VERSION 5.7 ;
  NOWIREEXTENSIONATPIN ON ;
  DIVIDERCHAR "/" ;
  BUSBITCHARS "[]" ;
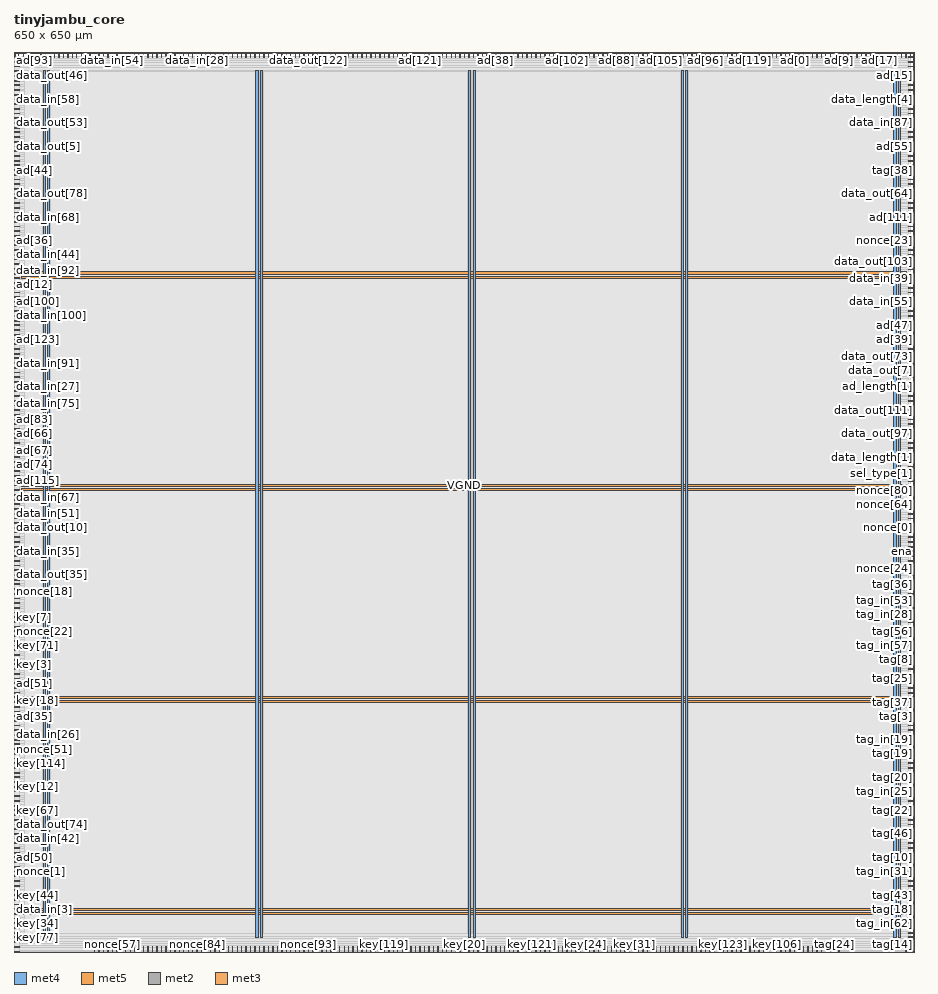
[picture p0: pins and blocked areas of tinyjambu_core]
MACRO tinyjambu_core
  CLASS BLOCK ;
  FOREIGN tinyjambu_core ;
  ORIGIN 0.000 0.000 ;
  SIZE 650.000 BY 650.000 ;
  PIN VGND
    DIRECTION INOUT ;
    USE GROUND ;
    PORT
      LAYER met4 ;
        RECT 24.340 10.640 25.940 636.720 ;
    END
    PORT
      LAYER met4 ;
        RECT 177.940 10.640 179.540 636.720 ;
    END
    PORT
      LAYER met4 ;
        RECT 331.540 10.640 333.140 636.720 ;
    END
    PORT
      LAYER met4 ;
        RECT 485.140 10.640 486.740 636.720 ;
    END
    PORT
      LAYER met4 ;
        RECT 638.740 10.640 640.340 636.720 ;
    END
    PORT
      LAYER met5 ;
        RECT 5.280 30.030 644.700 31.630 ;
    END
    PORT
      LAYER met5 ;
        RECT 5.280 183.210 644.700 184.810 ;
    END
    PORT
      LAYER met5 ;
        RECT 5.280 336.390 644.700 337.990 ;
    END
    PORT
      LAYER met5 ;
        RECT 5.280 489.570 644.700 491.170 ;
    END
  END VGND
  PIN VPWR
    DIRECTION INOUT ;
    USE POWER ;
    PORT
      LAYER met4 ;
        RECT 21.040 10.640 22.640 636.720 ;
    END
    PORT
      LAYER met4 ;
        RECT 174.640 10.640 176.240 636.720 ;
    END
    PORT
      LAYER met4 ;
        RECT 328.240 10.640 329.840 636.720 ;
    END
    PORT
      LAYER met4 ;
        RECT 481.840 10.640 483.440 636.720 ;
    END
    PORT
      LAYER met4 ;
        RECT 635.440 10.640 637.040 636.720 ;
    END
    PORT
      LAYER met5 ;
        RECT 5.280 26.730 644.700 28.330 ;
    END
    PORT
      LAYER met5 ;
        RECT 5.280 179.910 644.700 181.510 ;
    END
    PORT
      LAYER met5 ;
        RECT 5.280 333.090 644.700 334.690 ;
    END
    PORT
      LAYER met5 ;
        RECT 5.280 486.270 644.700 487.870 ;
    END
  END VPWR
  PIN ad[0]
    DIRECTION INPUT ;
    USE SIGNAL ;
    ANTENNAGATEAREA 0.196500 ;
    PORT
      LAYER met2 ;
        RECT 563.590 646.000 563.870 650.000 ;
    END
  END ad[0]
  PIN ad[100]
    DIRECTION INPUT ;
    USE SIGNAL ;
    ANTENNAGATEAREA 0.196500 ;
    PORT
      LAYER met3 ;
        RECT 0.000 469.240 4.000 469.840 ;
    END
  END ad[100]
  PIN ad[101]
    DIRECTION INPUT ;
    USE SIGNAL ;
    ANTENNAGATEAREA 0.196500 ;
    PORT
      LAYER met2 ;
        RECT 45.170 646.000 45.450 650.000 ;
    END
  END ad[101]
  PIN ad[102]
    DIRECTION INPUT ;
    USE SIGNAL ;
    ANTENNAGATEAREA 0.196500 ;
    PORT
      LAYER met2 ;
        RECT 399.370 646.000 399.650 650.000 ;
    END
  END ad[102]
  PIN ad[103]
    DIRECTION INPUT ;
    USE SIGNAL ;
    ANTENNAGATEAREA 0.196500 ;
    PORT
      LAYER met3 ;
        RECT 646.000 544.040 650.000 544.640 ;
    END
  END ad[103]
  PIN ad[104]
    DIRECTION INPUT ;
    USE SIGNAL ;
    ANTENNAGATEAREA 0.196500 ;
    PORT
      LAYER met2 ;
        RECT 444.450 646.000 444.730 650.000 ;
    END
  END ad[104]
  PIN ad[105]
    DIRECTION INPUT ;
    USE SIGNAL ;
    ANTENNAGATEAREA 0.196500 ;
    PORT
      LAYER met2 ;
        RECT 466.990 646.000 467.270 650.000 ;
    END
  END ad[105]
  PIN ad[106]
    DIRECTION INPUT ;
    USE SIGNAL ;
    ANTENNAGATEAREA 0.196500 ;
    PORT
      LAYER met3 ;
        RECT 0.000 411.440 4.000 412.040 ;
    END
  END ad[106]
  PIN ad[107]
    DIRECTION INPUT ;
    USE SIGNAL ;
    ANTENNAGATEAREA 0.196500 ;
    PORT
      LAYER met3 ;
        RECT 0.000 428.440 4.000 429.040 ;
    END
  END ad[107]
  PIN ad[108]
    DIRECTION INPUT ;
    USE SIGNAL ;
    ANTENNAGATEAREA 0.196500 ;
    PORT
      LAYER met3 ;
        RECT 0.000 544.040 4.000 544.640 ;
    END
  END ad[108]
  PIN ad[109]
    DIRECTION INPUT ;
    USE SIGNAL ;
    ANTENNAGATEAREA 0.196500 ;
    PORT
      LAYER met2 ;
        RECT 157.870 646.000 158.150 650.000 ;
    END
  END ad[109]
  PIN ad[10]
    DIRECTION INPUT ;
    USE SIGNAL ;
    ANTENNAGATEAREA 0.213000 ;
    PORT
      LAYER met3 ;
        RECT 0.000 6.840 4.000 7.440 ;
    END
  END ad[10]
  PIN ad[110]
    DIRECTION INPUT ;
    USE SIGNAL ;
    ANTENNAGATEAREA 0.196500 ;
    PORT
      LAYER met2 ;
        RECT 328.530 646.000 328.810 650.000 ;
    END
  END ad[110]
  PIN ad[111]
    DIRECTION INPUT ;
    USE SIGNAL ;
    ANTENNAGATEAREA 0.196500 ;
    PORT
      LAYER met3 ;
        RECT 646.000 530.440 650.000 531.040 ;
    END
  END ad[111]
  PIN ad[112]
    DIRECTION INPUT ;
    USE SIGNAL ;
    ANTENNAGATEAREA 0.196500 ;
    PORT
      LAYER met2 ;
        RECT 418.690 646.000 418.970 650.000 ;
    END
  END ad[112]
  PIN ad[113]
    DIRECTION INPUT ;
    USE SIGNAL ;
    ANTENNAGATEAREA 0.196500 ;
    PORT
      LAYER met2 ;
        RECT 608.670 646.000 608.950 650.000 ;
    END
  END ad[113]
  PIN ad[114]
    DIRECTION INPUT ;
    USE SIGNAL ;
    ANTENNAGATEAREA 0.196500 ;
    PORT
      LAYER met2 ;
        RECT 228.710 646.000 228.990 650.000 ;
    END
  END ad[114]
  PIN ad[115]
    DIRECTION INPUT ;
    USE SIGNAL ;
    ANTENNAGATEAREA 0.196500 ;
    PORT
      LAYER met3 ;
        RECT 0.000 340.040 4.000 340.640 ;
    END
  END ad[115]
  PIN ad[116]
    DIRECTION INPUT ;
    USE SIGNAL ;
    ANTENNAGATEAREA 0.196500 ;
    PORT
      LAYER met2 ;
        RECT 0.090 646.000 0.370 650.000 ;
    END
  END ad[116]
  PIN ad[117]
    DIRECTION INPUT ;
    USE SIGNAL ;
    ANTENNAGATEAREA 0.196500 ;
    PORT
      LAYER met2 ;
        RECT 83.810 646.000 84.090 650.000 ;
    END
  END ad[117]
  PIN ad[118]
    DIRECTION INPUT ;
    USE SIGNAL ;
    ANTENNAGATEAREA 0.196500 ;
    PORT
      LAYER met2 ;
        RECT 344.630 646.000 344.910 650.000 ;
    END
  END ad[118]
  PIN ad[119]
    DIRECTION INPUT ;
    USE SIGNAL ;
    ANTENNAGATEAREA 0.196500 ;
    PORT
      LAYER met2 ;
        RECT 531.390 646.000 531.670 650.000 ;
    END
  END ad[119]
  PIN ad[11]
    DIRECTION INPUT ;
    USE SIGNAL ;
    ANTENNAGATEAREA 0.196500 ;
    PORT
      LAYER met3 ;
        RECT 0.000 414.840 4.000 415.440 ;
    END
  END ad[11]
  PIN ad[120]
    DIRECTION INPUT ;
    USE SIGNAL ;
    ANTENNAGATEAREA 0.196500 ;
    PORT
      LAYER met2 ;
        RECT 412.250 646.000 412.530 650.000 ;
    END
  END ad[120]
  PIN ad[121]
    DIRECTION INPUT ;
    USE SIGNAL ;
    ANTENNAGATEAREA 0.196500 ;
    PORT
      LAYER met2 ;
        RECT 293.110 646.000 293.390 650.000 ;
    END
  END ad[121]
  PIN ad[122]
    DIRECTION INPUT ;
    USE SIGNAL ;
    ANTENNAGATEAREA 0.196500 ;
    PORT
      LAYER met2 ;
        RECT 58.050 646.000 58.330 650.000 ;
    END
  END ad[122]
  PIN ad[123]
    DIRECTION INPUT ;
    USE SIGNAL ;
    ANTENNAGATEAREA 0.196500 ;
    PORT
      LAYER met3 ;
        RECT 0.000 442.040 4.000 442.640 ;
    END
  END ad[123]
  PIN ad[124]
    DIRECTION INPUT ;
    USE SIGNAL ;
    ANTENNAGATEAREA 0.196500 ;
    PORT
      LAYER met2 ;
        RECT 106.350 646.000 106.630 650.000 ;
    END
  END ad[124]
  PIN ad[125]
    DIRECTION INPUT ;
    USE SIGNAL ;
    ANTENNAGATEAREA 0.196500 ;
    PORT
      LAYER met2 ;
        RECT 103.130 646.000 103.410 650.000 ;
    END
  END ad[125]
  PIN ad[126]
    DIRECTION INPUT ;
    USE SIGNAL ;
    ANTENNAGATEAREA 0.196500 ;
    PORT
      LAYER met2 ;
        RECT 373.610 646.000 373.890 650.000 ;
    END
  END ad[126]
  PIN ad[127]
    DIRECTION INPUT ;
    USE SIGNAL ;
    ANTENNAGATEAREA 0.196500 ;
    PORT
      LAYER met2 ;
        RECT 537.830 646.000 538.110 650.000 ;
    END
  END ad[127]
  PIN ad[12]
    DIRECTION INPUT ;
    USE SIGNAL ;
    ANTENNAGATEAREA 0.196500 ;
    PORT
      LAYER met3 ;
        RECT 0.000 476.040 4.000 476.640 ;
    END
  END ad[12]
  PIN ad[13]
    DIRECTION INPUT ;
    USE SIGNAL ;
    ANTENNAGATEAREA 0.196500 ;
    PORT
      LAYER met2 ;
        RECT 99.910 646.000 100.190 650.000 ;
    END
  END ad[13]
  PIN ad[14]
    DIRECTION INPUT ;
    USE SIGNAL ;
    ANTENNAGATEAREA 0.196500 ;
    PORT
      LAYER met2 ;
        RECT 322.090 646.000 322.370 650.000 ;
    END
  END ad[14]
  PIN ad[15]
    DIRECTION INPUT ;
    USE SIGNAL ;
    ANTENNAGATEAREA 0.196500 ;
    PORT
      LAYER met3 ;
        RECT 646.000 632.440 650.000 633.040 ;
    END
  END ad[15]
  PIN ad[16]
    DIRECTION INPUT ;
    USE SIGNAL ;
    ANTENNAGATEAREA 0.196500 ;
    PORT
      LAYER met2 ;
        RECT 576.470 646.000 576.750 650.000 ;
    END
  END ad[16]
  PIN ad[17]
    DIRECTION INPUT ;
    USE SIGNAL ;
    ANTENNAGATEAREA 0.196500 ;
    PORT
      LAYER met2 ;
        RECT 624.770 646.000 625.050 650.000 ;
    END
  END ad[17]
  PIN ad[18]
    DIRECTION INPUT ;
    USE SIGNAL ;
    ANTENNAGATEAREA 0.213000 ;
    PORT
      LAYER met2 ;
        RECT 270.570 646.000 270.850 650.000 ;
    END
  END ad[18]
  PIN ad[19]
    DIRECTION INPUT ;
    USE SIGNAL ;
    ANTENNAGATEAREA 0.196500 ;
    PORT
      LAYER met3 ;
        RECT 0.000 319.640 4.000 320.240 ;
    END
  END ad[19]
  PIN ad[1]
    DIRECTION INPUT ;
    USE SIGNAL ;
    ANTENNAGATEAREA 0.196500 ;
    PORT
      LAYER met2 ;
        RECT 309.210 646.000 309.490 650.000 ;
    END
  END ad[1]
  PIN ad[20]
    DIRECTION INPUT ;
    USE SIGNAL ;
    ANTENNAGATEAREA 0.196500 ;
    PORT
      LAYER met2 ;
        RECT 3.310 646.000 3.590 650.000 ;
    END
  END ad[20]
  PIN ad[21]
    DIRECTION INPUT ;
    USE SIGNAL ;
    ANTENNAGATEAREA 0.196500 ;
    PORT
      LAYER met2 ;
        RECT 183.630 646.000 183.910 650.000 ;
    END
  END ad[21]
  PIN ad[22]
    DIRECTION INPUT ;
    USE SIGNAL ;
    ANTENNAGATEAREA 0.196500 ;
    PORT
      LAYER met2 ;
        RECT 296.330 646.000 296.610 650.000 ;
    END
  END ad[22]
  PIN ad[23]
    DIRECTION INPUT ;
    USE SIGNAL ;
    ANTENNAGATEAREA 0.196500 ;
    PORT
      LAYER met3 ;
        RECT 646.000 642.640 650.000 643.240 ;
    END
  END ad[23]
  PIN ad[24]
    DIRECTION INPUT ;
    USE SIGNAL ;
    ANTENNAGATEAREA 0.196500 ;
    PORT
      LAYER met2 ;
        RECT 528.170 646.000 528.450 650.000 ;
    END
  END ad[24]
  PIN ad[25]
    DIRECTION INPUT ;
    USE SIGNAL ;
    ANTENNAGATEAREA 0.196500 ;
    PORT
      LAYER met2 ;
        RECT 277.010 646.000 277.290 650.000 ;
    END
  END ad[25]
  PIN ad[26]
    DIRECTION INPUT ;
    USE SIGNAL ;
    ANTENNAGATEAREA 0.213000 ;
    PORT
      LAYER met3 ;
        RECT 0.000 0.040 4.000 0.640 ;
    END
  END ad[26]
  PIN ad[27]
    DIRECTION INPUT ;
    USE SIGNAL ;
    ANTENNAGATEAREA 0.196500 ;
    PORT
      LAYER met3 ;
        RECT 0.000 387.640 4.000 388.240 ;
    END
  END ad[27]
  PIN ad[28]
    DIRECTION INPUT ;
    USE SIGNAL ;
    ANTENNAGATEAREA 0.196500 ;
    PORT
      LAYER met2 ;
        RECT 173.970 646.000 174.250 650.000 ;
    END
  END ad[28]
  PIN ad[29]
    DIRECTION INPUT ;
    USE SIGNAL ;
    ANTENNAGATEAREA 0.196500 ;
    PORT
      LAYER met2 ;
        RECT 48.390 646.000 48.670 650.000 ;
    END
  END ad[29]
  PIN ad[2]
    DIRECTION INPUT ;
    USE SIGNAL ;
    ANTENNAGATEAREA 0.196500 ;
    PORT
      LAYER met3 ;
        RECT 0.000 329.840 4.000 330.440 ;
    END
  END ad[2]
  PIN ad[30]
    DIRECTION INPUT ;
    USE SIGNAL ;
    ANTENNAGATEAREA 0.126000 ;
    PORT
      LAYER met2 ;
        RECT 495.970 646.000 496.250 650.000 ;
    END
  END ad[30]
  PIN ad[31]
    DIRECTION INPUT ;
    USE SIGNAL ;
    ANTENNAGATEAREA 0.196500 ;
    PORT
      LAYER met3 ;
        RECT 646.000 635.840 650.000 636.440 ;
    END
  END ad[31]
  PIN ad[32]
    DIRECTION INPUT ;
    USE SIGNAL ;
    ANTENNAGATEAREA 0.196500 ;
    PORT
      LAYER met2 ;
        RECT 460.550 646.000 460.830 650.000 ;
    END
  END ad[32]
  PIN ad[33]
    DIRECTION INPUT ;
    USE SIGNAL ;
    ANTENNAGATEAREA 0.196500 ;
    PORT
      LAYER met2 ;
        RECT 637.650 646.000 637.930 650.000 ;
    END
  END ad[33]
  PIN ad[34]
    DIRECTION INPUT ;
    USE SIGNAL ;
    ANTENNAGATEAREA 0.196500 ;
    PORT
      LAYER met3 ;
        RECT 0.000 326.440 4.000 327.040 ;
    END
  END ad[34]
  PIN ad[35]
    DIRECTION INPUT ;
    USE SIGNAL ;
    ANTENNAGATEAREA 0.196500 ;
    PORT
      LAYER met3 ;
        RECT 0.000 170.040 4.000 170.640 ;
    END
  END ad[35]
  PIN ad[36]
    DIRECTION INPUT ;
    USE SIGNAL ;
    ANTENNAGATEAREA 0.196500 ;
    PORT
      LAYER met3 ;
        RECT 0.000 513.440 4.000 514.040 ;
    END
  END ad[36]
  PIN ad[37]
    DIRECTION INPUT ;
    USE SIGNAL ;
    ANTENNAGATEAREA 0.196500 ;
    PORT
      LAYER met2 ;
        RECT 77.370 646.000 77.650 650.000 ;
    END
  END ad[37]
  PIN ad[38]
    DIRECTION INPUT ;
    USE SIGNAL ;
    ANTENNAGATEAREA 0.196500 ;
    PORT
      LAYER met2 ;
        RECT 347.850 646.000 348.130 650.000 ;
    END
  END ad[38]
  PIN ad[39]
    DIRECTION INPUT ;
    USE SIGNAL ;
    ANTENNAGATEAREA 0.196500 ;
    PORT
      LAYER met3 ;
        RECT 646.000 442.040 650.000 442.640 ;
    END
  END ad[39]
  PIN ad[3]
    DIRECTION INPUT ;
    USE SIGNAL ;
    ANTENNAGATEAREA 0.196500 ;
    PORT
      LAYER met3 ;
        RECT 0.000 278.840 4.000 279.440 ;
    END
  END ad[3]
  PIN ad[40]
    DIRECTION INPUT ;
    USE SIGNAL ;
    ANTENNAGATEAREA 0.196500 ;
    PORT
      LAYER met2 ;
        RECT 524.950 646.000 525.230 650.000 ;
    END
  END ad[40]
  PIN ad[41]
    DIRECTION INPUT ;
    USE SIGNAL ;
    ANTENNAGATEAREA 0.213000 ;
    PORT
      LAYER met2 ;
        RECT 634.430 646.000 634.710 650.000 ;
    END
  END ad[41]
  PIN ad[42]
    DIRECTION INPUT ;
    USE SIGNAL ;
    ANTENNAGATEAREA 0.196500 ;
    PORT
      LAYER met3 ;
        RECT 0.000 343.440 4.000 344.040 ;
    END
  END ad[42]
  PIN ad[43]
    DIRECTION INPUT ;
    USE SIGNAL ;
    ANTENNAGATEAREA 0.126000 ;
    PORT
      LAYER met3 ;
        RECT 0.000 612.040 4.000 612.640 ;
    END
  END ad[43]
  PIN ad[44]
    DIRECTION INPUT ;
    USE SIGNAL ;
    ANTENNAGATEAREA 0.196500 ;
    PORT
      LAYER met3 ;
        RECT 0.000 564.440 4.000 565.040 ;
    END
  END ad[44]
  PIN ad[45]
    DIRECTION INPUT ;
    USE SIGNAL ;
    ANTENNAGATEAREA 0.196500 ;
    PORT
      LAYER met2 ;
        RECT 128.890 646.000 129.170 650.000 ;
    END
  END ad[45]
  PIN ad[46]
    DIRECTION INPUT ;
    USE SIGNAL ;
    ANTENNAGATEAREA 0.196500 ;
    PORT
      LAYER met2 ;
        RECT 206.170 646.000 206.450 650.000 ;
    END
  END ad[46]
  PIN ad[47]
    DIRECTION INPUT ;
    USE SIGNAL ;
    ANTENNAGATEAREA 0.196500 ;
    PORT
      LAYER met3 ;
        RECT 646.000 452.240 650.000 452.840 ;
    END
  END ad[47]
  PIN ad[48]
    DIRECTION INPUT ;
    USE SIGNAL ;
    ANTENNAGATEAREA 0.196500 ;
    PORT
      LAYER met2 ;
        RECT 450.890 646.000 451.170 650.000 ;
    END
  END ad[48]
  PIN ad[49]
    DIRECTION INPUT ;
    USE SIGNAL ;
    ANTENNAGATEAREA 0.196500 ;
    PORT
      LAYER met2 ;
        RECT 508.850 646.000 509.130 650.000 ;
    END
  END ad[49]
  PIN ad[4]
    DIRECTION INPUT ;
    USE SIGNAL ;
    ANTENNAGATEAREA 0.196500 ;
    PORT
      LAYER met3 ;
        RECT 0.000 462.440 4.000 463.040 ;
    END
  END ad[4]
  PIN ad[50]
    DIRECTION INPUT ;
    USE SIGNAL ;
    ANTENNAGATEAREA 0.213000 ;
    PORT
      LAYER met3 ;
        RECT 0.000 68.040 4.000 68.640 ;
    END
  END ad[50]
  PIN ad[51]
    DIRECTION INPUT ;
    USE SIGNAL ;
    ANTENNAGATEAREA 0.196500 ;
    PORT
      LAYER met3 ;
        RECT 0.000 193.840 4.000 194.440 ;
    END
  END ad[51]
  PIN ad[52]
    DIRECTION INPUT ;
    USE SIGNAL ;
    ANTENNAGATEAREA 0.196500 ;
    PORT
      LAYER met2 ;
        RECT 54.830 646.000 55.110 650.000 ;
    END
  END ad[52]
  PIN ad[53]
    DIRECTION INPUT ;
    USE SIGNAL ;
    ANTENNAGATEAREA 0.196500 ;
    PORT
      LAYER met2 ;
        RECT 61.270 646.000 61.550 650.000 ;
    END
  END ad[53]
  PIN ad[54]
    DIRECTION INPUT ;
    USE SIGNAL ;
    ANTENNAGATEAREA 0.196500 ;
    PORT
      LAYER met2 ;
        RECT 22.630 646.000 22.910 650.000 ;
    END
  END ad[54]
  PIN ad[55]
    DIRECTION INPUT ;
    USE SIGNAL ;
    ANTENNAGATEAREA 0.196500 ;
    PORT
      LAYER met3 ;
        RECT 646.000 581.440 650.000 582.040 ;
    END
  END ad[55]
  PIN ad[56]
    DIRECTION INPUT ;
    USE SIGNAL ;
    ANTENNAGATEAREA 0.196500 ;
    PORT
      LAYER met2 ;
        RECT 582.910 646.000 583.190 650.000 ;
    END
  END ad[56]
  PIN ad[57]
    DIRECTION INPUT ;
    USE SIGNAL ;
    ANTENNAGATEAREA 0.196500 ;
    PORT
      LAYER met2 ;
        RECT 222.270 646.000 222.550 650.000 ;
    END
  END ad[57]
  PIN ad[58]
    DIRECTION INPUT ;
    USE SIGNAL ;
    ANTENNAGATEAREA 0.196500 ;
    PORT
      LAYER met3 ;
        RECT 0.000 642.640 4.000 643.240 ;
    END
  END ad[58]
  PIN ad[59]
    DIRECTION INPUT ;
    USE SIGNAL ;
    ANTENNAGATEAREA 0.196500 ;
    PORT
      LAYER met3 ;
        RECT 0.000 448.840 4.000 449.440 ;
    END
  END ad[59]
  PIN ad[5]
    DIRECTION INPUT ;
    USE SIGNAL ;
    ANTENNAGATEAREA 0.196500 ;
    PORT
      LAYER met2 ;
        RECT 19.410 646.000 19.690 650.000 ;
    END
  END ad[5]
  PIN ad[60]
    DIRECTION INPUT ;
    USE SIGNAL ;
    ANTENNAGATEAREA 0.126000 ;
    PORT
      LAYER met2 ;
        RECT 154.650 646.000 154.930 650.000 ;
    END
  END ad[60]
  PIN ad[61]
    DIRECTION INPUT ;
    USE SIGNAL ;
    ANTENNAGATEAREA 0.196500 ;
    PORT
      LAYER met2 ;
        RECT 116.010 646.000 116.290 650.000 ;
    END
  END ad[61]
  PIN ad[62]
    DIRECTION INPUT ;
    USE SIGNAL ;
    ANTENNAGATEAREA 0.196500 ;
    PORT
      LAYER met2 ;
        RECT 392.930 646.000 393.210 650.000 ;
    END
  END ad[62]
  PIN ad[63]
    DIRECTION INPUT ;
    USE SIGNAL ;
    ANTENNAGATEAREA 0.196500 ;
    PORT
      LAYER met2 ;
        RECT 479.870 646.000 480.150 650.000 ;
    END
  END ad[63]
  PIN ad[64]
    DIRECTION INPUT ;
    USE SIGNAL ;
    ANTENNAGATEAREA 0.196500 ;
    PORT
      LAYER met2 ;
        RECT 483.090 646.000 483.370 650.000 ;
    END
  END ad[64]
  PIN ad[65]
    DIRECTION INPUT ;
    USE SIGNAL ;
    ANTENNAGATEAREA 0.196500 ;
    PORT
      LAYER met2 ;
        RECT 315.650 646.000 315.930 650.000 ;
    END
  END ad[65]
  PIN ad[66]
    DIRECTION INPUT ;
    USE SIGNAL ;
    ANTENNAGATEAREA 0.196500 ;
    PORT
      LAYER met3 ;
        RECT 0.000 374.040 4.000 374.640 ;
    END
  END ad[66]
  PIN ad[67]
    DIRECTION INPUT ;
    USE SIGNAL ;
    ANTENNAGATEAREA 0.196500 ;
    PORT
      LAYER met3 ;
        RECT 0.000 367.240 4.000 367.840 ;
    END
  END ad[67]
  PIN ad[68]
    DIRECTION INPUT ;
    USE SIGNAL ;
    ANTENNAGATEAREA 0.196500 ;
    PORT
      LAYER met2 ;
        RECT 67.710 646.000 67.990 650.000 ;
    END
  END ad[68]
  PIN ad[69]
    DIRECTION INPUT ;
    USE SIGNAL ;
    ANTENNAGATEAREA 0.196500 ;
    PORT
      LAYER met2 ;
        RECT 219.050 646.000 219.330 650.000 ;
    END
  END ad[69]
  PIN ad[6]
    DIRECTION INPUT ;
    USE SIGNAL ;
    ANTENNAGATEAREA 0.196500 ;
    PORT
      LAYER met2 ;
        RECT 383.270 646.000 383.550 650.000 ;
    END
  END ad[6]
  PIN ad[70]
    DIRECTION INPUT ;
    USE SIGNAL ;
    ANTENNAGATEAREA 0.196500 ;
    PORT
      LAYER met2 ;
        RECT 354.290 646.000 354.570 650.000 ;
    END
  END ad[70]
  PIN ad[71]
    DIRECTION INPUT ;
    USE SIGNAL ;
    ANTENNAGATEAREA 0.196500 ;
    PORT
      LAYER met3 ;
        RECT 646.000 455.640 650.000 456.240 ;
    END
  END ad[71]
  PIN ad[72]
    DIRECTION INPUT ;
    USE SIGNAL ;
    ANTENNAGATEAREA 0.196500 ;
    PORT
      LAYER met2 ;
        RECT 470.210 646.000 470.490 650.000 ;
    END
  END ad[72]
  PIN ad[73]
    DIRECTION INPUT ;
    USE SIGNAL ;
    ANTENNAGATEAREA 0.196500 ;
    PORT
      LAYER met2 ;
        RECT 547.490 646.000 547.770 650.000 ;
    END
  END ad[73]
  PIN ad[74]
    DIRECTION INPUT ;
    USE SIGNAL ;
    ANTENNAGATEAREA 0.196500 ;
    PORT
      LAYER met3 ;
        RECT 0.000 357.040 4.000 357.640 ;
    END
  END ad[74]
  PIN ad[75]
    DIRECTION INPUT ;
    USE SIGNAL ;
    ANTENNAGATEAREA 0.196500 ;
    PORT
      LAYER met3 ;
        RECT 0.000 554.240 4.000 554.840 ;
    END
  END ad[75]
  PIN ad[76]
    DIRECTION INPUT ;
    USE SIGNAL ;
    ANTENNAGATEAREA 0.196500 ;
    PORT
      LAYER met3 ;
        RECT 0.000 496.440 4.000 497.040 ;
    END
  END ad[76]
  PIN ad[77]
    DIRECTION INPUT ;
    USE SIGNAL ;
    ANTENNAGATEAREA 0.196500 ;
    PORT
      LAYER met2 ;
        RECT 29.070 646.000 29.350 650.000 ;
    END
  END ad[77]
  PIN ad[78]
    DIRECTION INPUT ;
    USE SIGNAL ;
    ANTENNAGATEAREA 0.196500 ;
    PORT
      LAYER met2 ;
        RECT 283.450 646.000 283.730 650.000 ;
    END
  END ad[78]
  PIN ad[79]
    DIRECTION INPUT ;
    USE SIGNAL ;
    ANTENNAGATEAREA 0.196500 ;
    PORT
      LAYER met3 ;
        RECT 646.000 584.840 650.000 585.440 ;
    END
  END ad[79]
  PIN ad[7]
    DIRECTION INPUT ;
    USE SIGNAL ;
    ANTENNAGATEAREA 0.196500 ;
    PORT
      LAYER met3 ;
        RECT 646.000 428.440 650.000 429.040 ;
    END
  END ad[7]
  PIN ad[80]
    DIRECTION INPUT ;
    USE SIGNAL ;
    ANTENNAGATEAREA 0.196500 ;
    PORT
      LAYER met2 ;
        RECT 441.230 646.000 441.510 650.000 ;
    END
  END ad[80]
  PIN ad[81]
    DIRECTION INPUT ;
    USE SIGNAL ;
    ANTENNAGATEAREA 0.196500 ;
    PORT
      LAYER met2 ;
        RECT 605.450 646.000 605.730 650.000 ;
    END
  END ad[81]
  PIN ad[82]
    DIRECTION INPUT ;
    USE SIGNAL ;
    ANTENNAGATEAREA 0.213000 ;
    PORT
      LAYER met2 ;
        RECT 148.210 646.000 148.490 650.000 ;
    END
  END ad[82]
  PIN ad[83]
    DIRECTION INPUT ;
    USE SIGNAL ;
    ANTENNAGATEAREA 0.196500 ;
    PORT
      LAYER met3 ;
        RECT 0.000 384.240 4.000 384.840 ;
    END
  END ad[83]
  PIN ad[84]
    DIRECTION INPUT ;
    USE SIGNAL ;
    ANTENNAGATEAREA 0.196500 ;
    PORT
      LAYER met2 ;
        RECT 74.150 646.000 74.430 650.000 ;
    END
  END ad[84]
  PIN ad[85]
    DIRECTION INPUT ;
    USE SIGNAL ;
    ANTENNAGATEAREA 0.196500 ;
    PORT
      LAYER met2 ;
        RECT 193.290 646.000 193.570 650.000 ;
    END
  END ad[85]
  PIN ad[86]
    DIRECTION INPUT ;
    USE SIGNAL ;
    ANTENNAGATEAREA 0.196500 ;
    PORT
      LAYER met2 ;
        RECT 402.590 646.000 402.870 650.000 ;
    END
  END ad[86]
  PIN ad[87]
    DIRECTION INPUT ;
    USE SIGNAL ;
    ANTENNAGATEAREA 0.196500 ;
    PORT
      LAYER met3 ;
        RECT 646.000 588.240 650.000 588.840 ;
    END
  END ad[87]
  PIN ad[88]
    DIRECTION INPUT ;
    USE SIGNAL ;
    ANTENNAGATEAREA 0.196500 ;
    PORT
      LAYER met2 ;
        RECT 434.790 646.000 435.070 650.000 ;
    END
  END ad[88]
  PIN ad[89]
    DIRECTION INPUT ;
    USE SIGNAL ;
    ANTENNAGATEAREA 0.196500 ;
    PORT
      LAYER met2 ;
        RECT 299.550 646.000 299.830 650.000 ;
    END
  END ad[89]
  PIN ad[8]
    DIRECTION INPUT ;
    USE SIGNAL ;
    ANTENNAGATEAREA 0.196500 ;
    PORT
      LAYER met2 ;
        RECT 454.110 646.000 454.390 650.000 ;
    END
  END ad[8]
  PIN ad[90]
    DIRECTION INPUT ;
    USE SIGNAL ;
    ANTENNAGATEAREA 0.213000 ;
    PORT
      LAYER met2 ;
        RECT 238.370 646.000 238.650 650.000 ;
    END
  END ad[90]
  PIN ad[91]
    DIRECTION INPUT ;
    USE SIGNAL ;
    ANTENNAGATEAREA 0.126000 ;
    PORT
      LAYER met3 ;
        RECT 0.000 605.240 4.000 605.840 ;
    END
  END ad[91]
  PIN ad[92]
    DIRECTION INPUT ;
    USE SIGNAL ;
    ANTENNAGATEAREA 0.196500 ;
    PORT
      LAYER met3 ;
        RECT 0.000 482.840 4.000 483.440 ;
    END
  END ad[92]
  PIN ad[93]
    DIRECTION INPUT ;
    USE SIGNAL ;
    ANTENNAGATEAREA 0.196500 ;
    PORT
      LAYER met2 ;
        RECT 12.970 646.000 13.250 650.000 ;
    END
  END ad[93]
  PIN ad[94]
    DIRECTION INPUT ;
    USE SIGNAL ;
    ANTENNAGATEAREA 0.196500 ;
    PORT
      LAYER met2 ;
        RECT 357.510 646.000 357.790 650.000 ;
    END
  END ad[94]
  PIN ad[95]
    DIRECTION INPUT ;
    USE SIGNAL ;
    ANTENNAGATEAREA 0.196500 ;
    PORT
      LAYER met2 ;
        RECT 560.370 646.000 560.650 650.000 ;
    END
  END ad[95]
  PIN ad[96]
    DIRECTION INPUT ;
    USE SIGNAL ;
    ANTENNAGATEAREA 0.196500 ;
    PORT
      LAYER met2 ;
        RECT 499.190 646.000 499.470 650.000 ;
    END
  END ad[96]
  PIN ad[97]
    DIRECTION INPUT ;
    USE SIGNAL ;
    ANTENNAGATEAREA 0.196500 ;
    PORT
      LAYER met2 ;
        RECT 615.110 646.000 615.390 650.000 ;
    END
  END ad[97]
  PIN ad[98]
    DIRECTION INPUT ;
    USE SIGNAL ;
    ANTENNAGATEAREA 0.126000 ;
    PORT
      LAYER met3 ;
        RECT 0.000 591.640 4.000 592.240 ;
    END
  END ad[98]
  PIN ad[99]
    DIRECTION INPUT ;
    USE SIGNAL ;
    ANTENNAGATEAREA 0.196500 ;
    PORT
      LAYER met3 ;
        RECT 0.000 404.640 4.000 405.240 ;
    END
  END ad[99]
  PIN ad[9]
    DIRECTION INPUT ;
    USE SIGNAL ;
    ANTENNAGATEAREA 0.196500 ;
    PORT
      LAYER met2 ;
        RECT 595.790 646.000 596.070 650.000 ;
    END
  END ad[9]
  PIN ad_length[0]
    DIRECTION INPUT ;
    USE SIGNAL ;
    ANTENNAGATEAREA 0.213000 ;
    PORT
      LAYER met3 ;
        RECT 646.000 608.640 650.000 609.240 ;
    END
  END ad_length[0]
  PIN ad_length[1]
    DIRECTION INPUT ;
    USE SIGNAL ;
    ANTENNAGATEAREA 0.213000 ;
    PORT
      LAYER met3 ;
        RECT 646.000 408.040 650.000 408.640 ;
    END
  END ad_length[1]
  PIN ad_length[2]
    DIRECTION INPUT ;
    USE SIGNAL ;
    ANTENNAGATEAREA 0.213000 ;
    PORT
      LAYER met3 ;
        RECT 646.000 567.840 650.000 568.440 ;
    END
  END ad_length[2]
  PIN ad_length[3]
    DIRECTION INPUT ;
    USE SIGNAL ;
    ANTENNAGATEAREA 0.213000 ;
    PORT
      LAYER met3 ;
        RECT 646.000 377.440 650.000 378.040 ;
    END
  END ad_length[3]
  PIN ad_length[4]
    DIRECTION INPUT ;
    USE SIGNAL ;
    ANTENNAGATEAREA 0.126000 ;
    PORT
      LAYER met3 ;
        RECT 646.000 380.840 650.000 381.440 ;
    END
  END ad_length[4]
  PIN clk
    DIRECTION INPUT ;
    USE SIGNAL ;
    ANTENNAGATEAREA 0.852000 ;
    PORT
      LAYER met2 ;
        RECT 595.790 0.000 596.070 4.000 ;
    END
  END clk
  PIN data_in[0]
    DIRECTION INPUT ;
    USE SIGNAL ;
    ANTENNAGATEAREA 0.196500 ;
    PORT
      LAYER met2 ;
        RECT 541.050 646.000 541.330 650.000 ;
    END
  END data_in[0]
  PIN data_in[100]
    DIRECTION INPUT ;
    USE SIGNAL ;
    ANTENNAGATEAREA 0.196500 ;
    PORT
      LAYER met3 ;
        RECT 0.000 459.040 4.000 459.640 ;
    END
  END data_in[100]
  PIN data_in[101]
    DIRECTION INPUT ;
    USE SIGNAL ;
    ANTENNAGATEAREA 0.196500 ;
    PORT
      LAYER met2 ;
        RECT 186.850 646.000 187.130 650.000 ;
    END
  END data_in[101]
  PIN data_in[102]
    DIRECTION INPUT ;
    USE SIGNAL ;
    ANTENNAGATEAREA 0.196500 ;
    PORT
      LAYER met2 ;
        RECT 370.390 646.000 370.670 650.000 ;
    END
  END data_in[102]
  PIN data_in[103]
    DIRECTION INPUT ;
    USE SIGNAL ;
    ANTENNAGATEAREA 0.196500 ;
    PORT
      LAYER met3 ;
        RECT 646.000 591.640 650.000 592.240 ;
    END
  END data_in[103]
  PIN data_in[104]
    DIRECTION INPUT ;
    USE SIGNAL ;
    ANTENNAGATEAREA 0.196500 ;
    PORT
      LAYER met2 ;
        RECT 447.670 646.000 447.950 650.000 ;
    END
  END data_in[104]
  PIN data_in[105]
    DIRECTION INPUT ;
    USE SIGNAL ;
    ANTENNAGATEAREA 0.196500 ;
    PORT
      LAYER met2 ;
        RECT 589.350 646.000 589.630 650.000 ;
    END
  END data_in[105]
  PIN data_in[106]
    DIRECTION INPUT ;
    USE SIGNAL ;
    ANTENNAGATEAREA 0.196500 ;
    PORT
      LAYER met3 ;
        RECT 0.000 394.440 4.000 395.040 ;
    END
  END data_in[106]
  PIN data_in[107]
    DIRECTION INPUT ;
    USE SIGNAL ;
    ANTENNAGATEAREA 0.196500 ;
    PORT
      LAYER met3 ;
        RECT 0.000 561.040 4.000 561.640 ;
    END
  END data_in[107]
  PIN data_in[108]
    DIRECTION INPUT ;
    USE SIGNAL ;
    ANTENNAGATEAREA 0.196500 ;
    PORT
      LAYER met3 ;
        RECT 0.000 472.640 4.000 473.240 ;
    END
  END data_in[108]
  PIN data_in[109]
    DIRECTION INPUT ;
    USE SIGNAL ;
    ANTENNAGATEAREA 0.196500 ;
    PORT
      LAYER met2 ;
        RECT 251.250 646.000 251.530 650.000 ;
    END
  END data_in[109]
  PIN data_in[10]
    DIRECTION INPUT ;
    USE SIGNAL ;
    ANTENNAGATEAREA 0.213000 ;
    PORT
      LAYER met3 ;
        RECT 0.000 3.440 4.000 4.040 ;
    END
  END data_in[10]
  PIN data_in[110]
    DIRECTION INPUT ;
    USE SIGNAL ;
    ANTENNAGATEAREA 0.213000 ;
    PORT
      LAYER met2 ;
        RECT 518.510 646.000 518.790 650.000 ;
    END
  END data_in[110]
  PIN data_in[111]
    DIRECTION INPUT ;
    USE SIGNAL ;
    ANTENNAGATEAREA 0.196500 ;
    PORT
      LAYER met3 ;
        RECT 646.000 520.240 650.000 520.840 ;
    END
  END data_in[111]
  PIN data_in[112]
    DIRECTION INPUT ;
    USE SIGNAL ;
    ANTENNAGATEAREA 0.196500 ;
    PORT
      LAYER met2 ;
        RECT 473.430 646.000 473.710 650.000 ;
    END
  END data_in[112]
  PIN data_in[113]
    DIRECTION INPUT ;
    USE SIGNAL ;
    ANTENNAGATEAREA 0.196500 ;
    PORT
      LAYER met2 ;
        RECT 573.250 646.000 573.530 650.000 ;
    END
  END data_in[113]
  PIN data_in[114]
    DIRECTION INPUT ;
    USE SIGNAL ;
    ANTENNAGATEAREA 0.213000 ;
    PORT
      LAYER met2 ;
        RECT 264.130 646.000 264.410 650.000 ;
    END
  END data_in[114]
  PIN data_in[115]
    DIRECTION INPUT ;
    USE SIGNAL ;
    ANTENNAGATEAREA 0.196500 ;
    PORT
      LAYER met3 ;
        RECT 0.000 363.840 4.000 364.440 ;
    END
  END data_in[115]
  PIN data_in[116]
    DIRECTION INPUT ;
    USE SIGNAL ;
    ANTENNAGATEAREA 0.196500 ;
    PORT
      LAYER met2 ;
        RECT 138.550 646.000 138.830 650.000 ;
    END
  END data_in[116]
  PIN data_in[117]
    DIRECTION INPUT ;
    USE SIGNAL ;
    ANTENNAGATEAREA 0.196500 ;
    PORT
      LAYER met2 ;
        RECT 125.670 646.000 125.950 650.000 ;
    END
  END data_in[117]
  PIN data_in[118]
    DIRECTION INPUT ;
    USE SIGNAL ;
    ANTENNAGATEAREA 0.196500 ;
    PORT
      LAYER met2 ;
        RECT 334.970 646.000 335.250 650.000 ;
    END
  END data_in[118]
  PIN data_in[119]
    DIRECTION INPUT ;
    USE SIGNAL ;
    ANTENNAGATEAREA 0.196500 ;
    PORT
      LAYER met2 ;
        RECT 534.610 646.000 534.890 650.000 ;
    END
  END data_in[119]
  PIN data_in[11]
    DIRECTION INPUT ;
    USE SIGNAL ;
    ANTENNAGATEAREA 0.126000 ;
    PORT
      LAYER met3 ;
        RECT 0.000 584.840 4.000 585.440 ;
    END
  END data_in[11]
  PIN data_in[120]
    DIRECTION INPUT ;
    USE SIGNAL ;
    ANTENNAGATEAREA 0.196500 ;
    PORT
      LAYER met2 ;
        RECT 409.030 646.000 409.310 650.000 ;
    END
  END data_in[120]
  PIN data_in[121]
    DIRECTION INPUT ;
    USE SIGNAL ;
    ANTENNAGATEAREA 0.196500 ;
    PORT
      LAYER met2 ;
        RECT 286.670 646.000 286.950 650.000 ;
    END
  END data_in[121]
  PIN data_in[122]
    DIRECTION INPUT ;
    USE SIGNAL ;
    ANTENNAGATEAREA 0.196500 ;
    PORT
      LAYER met2 ;
        RECT 199.730 646.000 200.010 650.000 ;
    END
  END data_in[122]
  PIN data_in[123]
    DIRECTION INPUT ;
    USE SIGNAL ;
    ANTENNAGATEAREA 0.196500 ;
    PORT
      LAYER met3 ;
        RECT 0.000 438.640 4.000 439.240 ;
    END
  END data_in[123]
  PIN data_in[124]
    DIRECTION INPUT ;
    USE SIGNAL ;
    ANTENNAGATEAREA 0.196500 ;
    PORT
      LAYER met2 ;
        RECT 112.790 646.000 113.070 650.000 ;
    END
  END data_in[124]
  PIN data_in[125]
    DIRECTION INPUT ;
    USE SIGNAL ;
    ANTENNAGATEAREA 0.196500 ;
    PORT
      LAYER met2 ;
        RECT 215.830 646.000 216.110 650.000 ;
    END
  END data_in[125]
  PIN data_in[126]
    DIRECTION INPUT ;
    USE SIGNAL ;
    ANTENNAGATEAREA 0.196500 ;
    PORT
      LAYER met2 ;
        RECT 363.950 646.000 364.230 650.000 ;
    END
  END data_in[126]
  PIN data_in[127]
    DIRECTION INPUT ;
    USE SIGNAL ;
    ANTENNAGATEAREA 0.196500 ;
    PORT
      LAYER met2 ;
        RECT 415.470 646.000 415.750 650.000 ;
    END
  END data_in[127]
  PIN data_in[12]
    DIRECTION INPUT ;
    USE SIGNAL ;
    ANTENNAGATEAREA 0.196500 ;
    PORT
      LAYER met3 ;
        RECT 0.000 499.840 4.000 500.440 ;
    END
  END data_in[12]
  PIN data_in[13]
    DIRECTION INPUT ;
    USE SIGNAL ;
    ANTENNAGATEAREA 0.126000 ;
    PORT
      LAYER met2 ;
        RECT 51.610 646.000 51.890 650.000 ;
    END
  END data_in[13]
  PIN data_in[14]
    DIRECTION INPUT ;
    USE SIGNAL ;
    ANTENNAGATEAREA 0.196500 ;
    PORT
      LAYER met2 ;
        RECT 260.910 646.000 261.190 650.000 ;
    END
  END data_in[14]
  PIN data_in[15]
    DIRECTION INPUT ;
    USE SIGNAL ;
    ANTENNAGATEAREA 0.196500 ;
    PORT
      LAYER met3 ;
        RECT 646.000 397.840 650.000 398.440 ;
    END
  END data_in[15]
  PIN data_in[16]
    DIRECTION INPUT ;
    USE SIGNAL ;
    ANTENNAGATEAREA 0.196500 ;
    PORT
      LAYER met2 ;
        RECT 579.690 646.000 579.970 650.000 ;
    END
  END data_in[16]
  PIN data_in[17]
    DIRECTION INPUT ;
    USE SIGNAL ;
    ANTENNAGATEAREA 0.196500 ;
    PORT
      LAYER met2 ;
        RECT 640.870 646.000 641.150 650.000 ;
    END
  END data_in[17]
  PIN data_in[18]
    DIRECTION INPUT ;
    USE SIGNAL ;
    ANTENNAGATEAREA 0.213000 ;
    PORT
      LAYER met2 ;
        RECT 289.890 646.000 290.170 650.000 ;
    END
  END data_in[18]
  PIN data_in[19]
    DIRECTION INPUT ;
    USE SIGNAL ;
    ANTENNAGATEAREA 0.196500 ;
    PORT
      LAYER met3 ;
        RECT 0.000 309.440 4.000 310.040 ;
    END
  END data_in[19]
  PIN data_in[1]
    DIRECTION INPUT ;
    USE SIGNAL ;
    ANTENNAGATEAREA 0.196500 ;
    PORT
      LAYER met2 ;
        RECT 267.350 646.000 267.630 650.000 ;
    END
  END data_in[1]
  PIN data_in[20]
    DIRECTION INPUT ;
    USE SIGNAL ;
    ANTENNAGATEAREA 0.196500 ;
    PORT
      LAYER met2 ;
        RECT 80.590 646.000 80.870 650.000 ;
    END
  END data_in[20]
  PIN data_in[21]
    DIRECTION INPUT ;
    USE SIGNAL ;
    ANTENNAGATEAREA 0.196500 ;
    PORT
      LAYER met2 ;
        RECT 196.510 646.000 196.790 650.000 ;
    END
  END data_in[21]
  PIN data_in[22]
    DIRECTION INPUT ;
    USE SIGNAL ;
    ANTENNAGATEAREA 0.196500 ;
    PORT
      LAYER met2 ;
        RECT 280.230 646.000 280.510 650.000 ;
    END
  END data_in[22]
  PIN data_in[23]
    DIRECTION INPUT ;
    USE SIGNAL ;
    ANTENNAGATEAREA 0.196500 ;
    PORT
      LAYER met3 ;
        RECT 646.000 489.640 650.000 490.240 ;
    END
  END data_in[23]
  PIN data_in[24]
    DIRECTION INPUT ;
    USE SIGNAL ;
    ANTENNAGATEAREA 0.196500 ;
    PORT
      LAYER met2 ;
        RECT 438.010 646.000 438.290 650.000 ;
    END
  END data_in[24]
  PIN data_in[25]
    DIRECTION INPUT ;
    USE SIGNAL ;
    ANTENNAGATEAREA 0.196500 ;
    PORT
      LAYER met2 ;
        RECT 241.590 646.000 241.870 650.000 ;
    END
  END data_in[25]
  PIN data_in[26]
    DIRECTION INPUT ;
    USE SIGNAL ;
    ANTENNAGATEAREA 0.196500 ;
    PORT
      LAYER met3 ;
        RECT 0.000 156.440 4.000 157.040 ;
    END
  END data_in[26]
  PIN data_in[27]
    DIRECTION INPUT ;
    USE SIGNAL ;
    ANTENNAGATEAREA 0.196500 ;
    PORT
      LAYER met3 ;
        RECT 0.000 408.040 4.000 408.640 ;
    END
  END data_in[27]
  PIN data_in[28]
    DIRECTION INPUT ;
    USE SIGNAL ;
    ANTENNAGATEAREA 0.196500 ;
    PORT
      LAYER met2 ;
        RECT 132.110 646.000 132.390 650.000 ;
    END
  END data_in[28]
  PIN data_in[29]
    DIRECTION INPUT ;
    USE SIGNAL ;
    ANTENNAGATEAREA 0.196500 ;
    PORT
      LAYER met2 ;
        RECT 190.070 646.000 190.350 650.000 ;
    END
  END data_in[29]
  PIN data_in[2]
    DIRECTION INPUT ;
    USE SIGNAL ;
    ANTENNAGATEAREA 0.196500 ;
    PORT
      LAYER met3 ;
        RECT 0.000 346.840 4.000 347.440 ;
    END
  END data_in[2]
  PIN data_in[30]
    DIRECTION INPUT ;
    USE SIGNAL ;
    ANTENNAGATEAREA 0.196500 ;
    PORT
      LAYER met2 ;
        RECT 331.750 646.000 332.030 650.000 ;
    END
  END data_in[30]
  PIN data_in[31]
    DIRECTION INPUT ;
    USE SIGNAL ;
    ANTENNAGATEAREA 0.196500 ;
    PORT
      LAYER met2 ;
        RECT 476.650 646.000 476.930 650.000 ;
    END
  END data_in[31]
  PIN data_in[32]
    DIRECTION INPUT ;
    USE SIGNAL ;
    ANTENNAGATEAREA 0.196500 ;
    PORT
      LAYER met2 ;
        RECT 463.770 646.000 464.050 650.000 ;
    END
  END data_in[32]
  PIN data_in[33]
    DIRECTION INPUT ;
    USE SIGNAL ;
    ANTENNAGATEAREA 0.196500 ;
    PORT
      LAYER met2 ;
        RECT 644.090 646.000 644.370 650.000 ;
    END
  END data_in[33]
  PIN data_in[34]
    DIRECTION INPUT ;
    USE SIGNAL ;
    ANTENNAGATEAREA 0.213000 ;
    PORT
      LAYER met3 ;
        RECT 0.000 122.440 4.000 123.040 ;
    END
  END data_in[34]
  PIN data_in[35]
    DIRECTION INPUT ;
    USE SIGNAL ;
    ANTENNAGATEAREA 0.196500 ;
    PORT
      LAYER met3 ;
        RECT 0.000 289.040 4.000 289.640 ;
    END
  END data_in[35]
  PIN data_in[36]
    DIRECTION INPUT ;
    USE SIGNAL ;
    ANTENNAGATEAREA 0.196500 ;
    PORT
      LAYER met3 ;
        RECT 0.000 516.840 4.000 517.440 ;
    END
  END data_in[36]
  PIN data_in[37]
    DIRECTION INPUT ;
    USE SIGNAL ;
    ANTENNAGATEAREA 0.196500 ;
    PORT
      LAYER met2 ;
        RECT 6.530 646.000 6.810 650.000 ;
    END
  END data_in[37]
  PIN data_in[38]
    DIRECTION INPUT ;
    USE SIGNAL ;
    ANTENNAGATEAREA 0.196500 ;
    PORT
      LAYER met2 ;
        RECT 341.410 646.000 341.690 650.000 ;
    END
  END data_in[38]
  PIN data_in[39]
    DIRECTION INPUT ;
    USE SIGNAL ;
    ANTENNAGATEAREA 0.196500 ;
    PORT
      LAYER met3 ;
        RECT 646.000 486.240 650.000 486.840 ;
    END
  END data_in[39]
  PIN data_in[3]
    DIRECTION INPUT ;
    USE SIGNAL ;
    ANTENNAGATEAREA 0.213000 ;
    PORT
      LAYER met3 ;
        RECT 0.000 30.640 4.000 31.240 ;
    END
  END data_in[3]
  PIN data_in[40]
    DIRECTION INPUT ;
    USE SIGNAL ;
    ANTENNAGATEAREA 0.196500 ;
    PORT
      LAYER met2 ;
        RECT 557.150 646.000 557.430 650.000 ;
    END
  END data_in[40]
  PIN data_in[41]
    DIRECTION INPUT ;
    USE SIGNAL ;
    ANTENNAGATEAREA 0.196500 ;
    PORT
      LAYER met2 ;
        RECT 312.430 646.000 312.710 650.000 ;
    END
  END data_in[41]
  PIN data_in[42]
    DIRECTION INPUT ;
    USE SIGNAL ;
    ANTENNAGATEAREA 0.213000 ;
    PORT
      LAYER met3 ;
        RECT 0.000 81.640 4.000 82.240 ;
    END
  END data_in[42]
  PIN data_in[43]
    DIRECTION INPUT ;
    USE SIGNAL ;
    ANTENNAGATEAREA 0.196500 ;
    PORT
      LAYER met3 ;
        RECT 0.000 452.240 4.000 452.840 ;
    END
  END data_in[43]
  PIN data_in[44]
    DIRECTION INPUT ;
    USE SIGNAL ;
    ANTENNAGATEAREA 0.196500 ;
    PORT
      LAYER met3 ;
        RECT 0.000 503.240 4.000 503.840 ;
    END
  END data_in[44]
  PIN data_in[45]
    DIRECTION INPUT ;
    USE SIGNAL ;
    ANTENNAGATEAREA 0.196500 ;
    PORT
      LAYER met2 ;
        RECT 257.690 646.000 257.970 650.000 ;
    END
  END data_in[45]
  PIN data_in[46]
    DIRECTION INPUT ;
    USE SIGNAL ;
    ANTENNAGATEAREA 0.196500 ;
    PORT
      LAYER met2 ;
        RECT 144.990 646.000 145.270 650.000 ;
    END
  END data_in[46]
  PIN data_in[47]
    DIRECTION INPUT ;
    USE SIGNAL ;
    ANTENNAGATEAREA 0.196500 ;
    PORT
      LAYER met3 ;
        RECT 646.000 571.240 650.000 571.840 ;
    END
  END data_in[47]
  PIN data_in[48]
    DIRECTION INPUT ;
    USE SIGNAL ;
    ANTENNAGATEAREA 0.196500 ;
    PORT
      LAYER met2 ;
        RECT 521.730 646.000 522.010 650.000 ;
    END
  END data_in[48]
  PIN data_in[49]
    DIRECTION INPUT ;
    USE SIGNAL ;
    ANTENNAGATEAREA 0.196500 ;
    PORT
      LAYER met2 ;
        RECT 611.890 646.000 612.170 650.000 ;
    END
  END data_in[49]
  PIN data_in[4]
    DIRECTION INPUT ;
    USE SIGNAL ;
    ANTENNAGATEAREA 0.196500 ;
    PORT
      LAYER met3 ;
        RECT 0.000 455.640 4.000 456.240 ;
    END
  END data_in[4]
  PIN data_in[50]
    DIRECTION INPUT ;
    USE SIGNAL ;
    ANTENNAGATEAREA 0.159000 ;
    PORT
      LAYER met3 ;
        RECT 0.000 17.040 4.000 17.640 ;
    END
  END data_in[50]
  PIN data_in[51]
    DIRECTION INPUT ;
    USE SIGNAL ;
    ANTENNAGATEAREA 0.196500 ;
    PORT
      LAYER met3 ;
        RECT 0.000 316.240 4.000 316.840 ;
    END
  END data_in[51]
  PIN data_in[52]
    DIRECTION INPUT ;
    USE SIGNAL ;
    ANTENNAGATEAREA 0.196500 ;
    PORT
      LAYER met2 ;
        RECT 32.290 646.000 32.570 650.000 ;
    END
  END data_in[52]
  PIN data_in[53]
    DIRECTION INPUT ;
    USE SIGNAL ;
    ANTENNAGATEAREA 0.126000 ;
    PORT
      LAYER met2 ;
        RECT 209.390 646.000 209.670 650.000 ;
    END
  END data_in[53]
  PIN data_in[54]
    DIRECTION INPUT ;
    USE SIGNAL ;
    ANTENNAGATEAREA 0.196500 ;
    PORT
      LAYER met2 ;
        RECT 70.930 646.000 71.210 650.000 ;
    END
  END data_in[54]
  PIN data_in[55]
    DIRECTION INPUT ;
    USE SIGNAL ;
    ANTENNAGATEAREA 0.196500 ;
    PORT
      LAYER met3 ;
        RECT 646.000 469.240 650.000 469.840 ;
    END
  END data_in[55]
  PIN data_in[56]
    DIRECTION INPUT ;
    USE SIGNAL ;
    ANTENNAGATEAREA 0.126000 ;
    PORT
      LAYER met2 ;
        RECT 431.570 646.000 431.850 650.000 ;
    END
  END data_in[56]
  PIN data_in[57]
    DIRECTION INPUT ;
    USE SIGNAL ;
    ANTENNAGATEAREA 0.196500 ;
    PORT
      LAYER met2 ;
        RECT 96.690 646.000 96.970 650.000 ;
    END
  END data_in[57]
  PIN data_in[58]
    DIRECTION INPUT ;
    USE SIGNAL ;
    ANTENNAGATEAREA 0.196500 ;
    PORT
      LAYER met3 ;
        RECT 0.000 615.440 4.000 616.040 ;
    END
  END data_in[58]
  PIN data_in[59]
    DIRECTION INPUT ;
    USE SIGNAL ;
    ANTENNAGATEAREA 0.196500 ;
    PORT
      LAYER met3 ;
        RECT 0.000 578.040 4.000 578.640 ;
    END
  END data_in[59]
  PIN data_in[5]
    DIRECTION INPUT ;
    USE SIGNAL ;
    ANTENNAGATEAREA 0.196500 ;
    PORT
      LAYER met2 ;
        RECT 93.470 646.000 93.750 650.000 ;
    END
  END data_in[5]
  PIN data_in[60]
    DIRECTION INPUT ;
    USE SIGNAL ;
    ANTENNAGATEAREA 0.213000 ;
    PORT
      LAYER met2 ;
        RECT 167.530 646.000 167.810 650.000 ;
    END
  END data_in[60]
  PIN data_in[61]
    DIRECTION INPUT ;
    USE SIGNAL ;
    ANTENNAGATEAREA 0.196500 ;
    PORT
      LAYER met2 ;
        RECT 177.190 646.000 177.470 650.000 ;
    END
  END data_in[61]
  PIN data_in[62]
    DIRECTION INPUT ;
    USE SIGNAL ;
    ANTENNAGATEAREA 0.196500 ;
    PORT
      LAYER met2 ;
        RECT 396.150 646.000 396.430 650.000 ;
    END
  END data_in[62]
  PIN data_in[63]
    DIRECTION INPUT ;
    USE SIGNAL ;
    ANTENNAGATEAREA 0.196500 ;
    PORT
      LAYER met2 ;
        RECT 502.410 646.000 502.690 650.000 ;
    END
  END data_in[63]
  PIN data_in[64]
    DIRECTION INPUT ;
    USE SIGNAL ;
    ANTENNAGATEAREA 0.196500 ;
    PORT
      LAYER met2 ;
        RECT 505.630 646.000 505.910 650.000 ;
    END
  END data_in[64]
  PIN data_in[65]
    DIRECTION INPUT ;
    USE SIGNAL ;
    ANTENNAGATEAREA 0.196500 ;
    PORT
      LAYER met2 ;
        RECT 305.990 646.000 306.270 650.000 ;
    END
  END data_in[65]
  PIN data_in[66]
    DIRECTION INPUT ;
    USE SIGNAL ;
    ANTENNAGATEAREA 0.213000 ;
    PORT
      LAYER met3 ;
        RECT 0.000 34.040 4.000 34.640 ;
    END
  END data_in[66]
  PIN data_in[67]
    DIRECTION INPUT ;
    USE SIGNAL ;
    ANTENNAGATEAREA 0.196500 ;
    PORT
      LAYER met3 ;
        RECT 0.000 333.240 4.000 333.840 ;
    END
  END data_in[67]
  PIN data_in[68]
    DIRECTION INPUT ;
    USE SIGNAL ;
    ANTENNAGATEAREA 0.196500 ;
    PORT
      LAYER met3 ;
        RECT 0.000 530.440 4.000 531.040 ;
    END
  END data_in[68]
  PIN data_in[69]
    DIRECTION INPUT ;
    USE SIGNAL ;
    ANTENNAGATEAREA 0.196500 ;
    PORT
      LAYER met2 ;
        RECT 119.230 646.000 119.510 650.000 ;
    END
  END data_in[69]
  PIN data_in[6]
    DIRECTION INPUT ;
    USE SIGNAL ;
    ANTENNAGATEAREA 0.196500 ;
    PORT
      LAYER met2 ;
        RECT 376.830 646.000 377.110 650.000 ;
    END
  END data_in[6]
  PIN data_in[70]
    DIRECTION INPUT ;
    USE SIGNAL ;
    ANTENNAGATEAREA 0.196500 ;
    PORT
      LAYER met2 ;
        RECT 367.170 646.000 367.450 650.000 ;
    END
  END data_in[70]
  PIN data_in[71]
    DIRECTION INPUT ;
    USE SIGNAL ;
    ANTENNAGATEAREA 0.196500 ;
    PORT
      LAYER met3 ;
        RECT 646.000 540.640 650.000 541.240 ;
    END
  END data_in[71]
  PIN data_in[72]
    DIRECTION INPUT ;
    USE SIGNAL ;
    ANTENNAGATEAREA 0.196500 ;
    PORT
      LAYER met2 ;
        RECT 592.570 646.000 592.850 650.000 ;
    END
  END data_in[72]
  PIN data_in[73]
    DIRECTION INPUT ;
    USE SIGNAL ;
    ANTENNAGATEAREA 0.196500 ;
    PORT
      LAYER met2 ;
        RECT 586.130 646.000 586.410 650.000 ;
    END
  END data_in[73]
  PIN data_in[74]
    DIRECTION INPUT ;
    USE SIGNAL ;
    ANTENNAGATEAREA 0.196500 ;
    PORT
      LAYER met3 ;
        RECT 0.000 350.240 4.000 350.840 ;
    END
  END data_in[74]
  PIN data_in[75]
    DIRECTION INPUT ;
    USE SIGNAL ;
    ANTENNAGATEAREA 0.196500 ;
    PORT
      LAYER met3 ;
        RECT 0.000 401.240 4.000 401.840 ;
    END
  END data_in[75]
  PIN data_in[76]
    DIRECTION INPUT ;
    USE SIGNAL ;
    ANTENNAGATEAREA 0.196500 ;
    PORT
      LAYER met3 ;
        RECT 0.000 489.640 4.000 490.240 ;
    END
  END data_in[76]
  PIN data_in[77]
    DIRECTION INPUT ;
    USE SIGNAL ;
    ANTENNAGATEAREA 0.196500 ;
    PORT
      LAYER met2 ;
        RECT 231.930 646.000 232.210 650.000 ;
    END
  END data_in[77]
  PIN data_in[78]
    DIRECTION INPUT ;
    USE SIGNAL ;
    ANTENNAGATEAREA 0.196500 ;
    PORT
      LAYER met2 ;
        RECT 235.150 646.000 235.430 650.000 ;
    END
  END data_in[78]
  PIN data_in[79]
    DIRECTION INPUT ;
    USE SIGNAL ;
    ANTENNAGATEAREA 0.196500 ;
    PORT
      LAYER met3 ;
        RECT 646.000 448.840 650.000 449.440 ;
    END
  END data_in[79]
  PIN data_in[7]
    DIRECTION INPUT ;
    USE SIGNAL ;
    ANTENNAGATEAREA 0.196500 ;
    PORT
      LAYER met3 ;
        RECT 646.000 421.640 650.000 422.240 ;
    END
  END data_in[7]
  PIN data_in[80]
    DIRECTION INPUT ;
    USE SIGNAL ;
    ANTENNAGATEAREA 0.196500 ;
    PORT
      LAYER met2 ;
        RECT 425.130 646.000 425.410 650.000 ;
    END
  END data_in[80]
  PIN data_in[81]
    DIRECTION INPUT ;
    USE SIGNAL ;
    ANTENNAGATEAREA 0.196500 ;
    PORT
      LAYER met2 ;
        RECT 512.070 646.000 512.350 650.000 ;
    END
  END data_in[81]
  PIN data_in[82]
    DIRECTION INPUT ;
    USE SIGNAL ;
    ANTENNAGATEAREA 0.159000 ;
    PORT
      LAYER met2 ;
        RECT 244.810 646.000 245.090 650.000 ;
    END
  END data_in[82]
  PIN data_in[83]
    DIRECTION INPUT ;
    USE SIGNAL ;
    ANTENNAGATEAREA 0.196500 ;
    PORT
      LAYER met3 ;
        RECT 0.000 377.440 4.000 378.040 ;
    END
  END data_in[83]
  PIN data_in[84]
    DIRECTION INPUT ;
    USE SIGNAL ;
    ANTENNAGATEAREA 0.196500 ;
    PORT
      LAYER met2 ;
        RECT 90.250 646.000 90.530 650.000 ;
    END
  END data_in[84]
  PIN data_in[85]
    DIRECTION INPUT ;
    USE SIGNAL ;
    ANTENNAGATEAREA 0.196500 ;
    PORT
      LAYER met2 ;
        RECT 122.450 646.000 122.730 650.000 ;
    END
  END data_in[85]
  PIN data_in[86]
    DIRECTION INPUT ;
    USE SIGNAL ;
    ANTENNAGATEAREA 0.196500 ;
    PORT
      LAYER met2 ;
        RECT 318.870 646.000 319.150 650.000 ;
    END
  END data_in[86]
  PIN data_in[87]
    DIRECTION INPUT ;
    USE SIGNAL ;
    ANTENNAGATEAREA 0.196500 ;
    PORT
      LAYER met3 ;
        RECT 646.000 598.440 650.000 599.040 ;
    END
  END data_in[87]
  PIN data_in[88]
    DIRECTION INPUT ;
    USE SIGNAL ;
    ANTENNAGATEAREA 0.196500 ;
    PORT
      LAYER met2 ;
        RECT 428.350 646.000 428.630 650.000 ;
    END
  END data_in[88]
  PIN data_in[89]
    DIRECTION INPUT ;
    USE SIGNAL ;
    ANTENNAGATEAREA 0.196500 ;
    PORT
      LAYER met2 ;
        RECT 273.790 646.000 274.070 650.000 ;
    END
  END data_in[89]
  PIN data_in[8]
    DIRECTION INPUT ;
    USE SIGNAL ;
    ANTENNAGATEAREA 0.196500 ;
    PORT
      LAYER met2 ;
        RECT 457.330 646.000 457.610 650.000 ;
    END
  END data_in[8]
  PIN data_in[90]
    DIRECTION INPUT ;
    USE SIGNAL ;
    ANTENNAGATEAREA 0.196500 ;
    PORT
      LAYER met2 ;
        RECT 38.730 646.000 39.010 650.000 ;
    END
  END data_in[90]
  PIN data_in[91]
    DIRECTION INPUT ;
    USE SIGNAL ;
    ANTENNAGATEAREA 0.196500 ;
    PORT
      LAYER met3 ;
        RECT 0.000 425.040 4.000 425.640 ;
    END
  END data_in[91]
  PIN data_in[92]
    DIRECTION INPUT ;
    USE SIGNAL ;
    ANTENNAGATEAREA 0.196500 ;
    PORT
      LAYER met3 ;
        RECT 0.000 486.240 4.000 486.840 ;
    END
  END data_in[92]
  PIN data_in[93]
    DIRECTION INPUT ;
    USE SIGNAL ;
    ANTENNAGATEAREA 0.196500 ;
    PORT
      LAYER met2 ;
        RECT 161.090 646.000 161.370 650.000 ;
    END
  END data_in[93]
  PIN data_in[94]
    DIRECTION INPUT ;
    USE SIGNAL ;
    ANTENNAGATEAREA 0.196500 ;
    PORT
      LAYER met2 ;
        RECT 360.730 646.000 361.010 650.000 ;
    END
  END data_in[94]
  PIN data_in[95]
    DIRECTION INPUT ;
    USE SIGNAL ;
    ANTENNAGATEAREA 0.196500 ;
    PORT
      LAYER met2 ;
        RECT 544.270 646.000 544.550 650.000 ;
    END
  END data_in[95]
  PIN data_in[96]
    DIRECTION INPUT ;
    USE SIGNAL ;
    ANTENNAGATEAREA 0.196500 ;
    PORT
      LAYER met2 ;
        RECT 621.550 646.000 621.830 650.000 ;
    END
  END data_in[96]
  PIN data_in[97]
    DIRECTION INPUT ;
    USE SIGNAL ;
    ANTENNAGATEAREA 0.196500 ;
    PORT
      LAYER met2 ;
        RECT 627.990 646.000 628.270 650.000 ;
    END
  END data_in[97]
  PIN data_in[98]
    DIRECTION INPUT ;
    USE SIGNAL ;
    ANTENNAGATEAREA 0.196500 ;
    PORT
      LAYER met3 ;
        RECT 0.000 380.840 4.000 381.440 ;
    END
  END data_in[98]
  PIN data_in[99]
    DIRECTION INPUT ;
    USE SIGNAL ;
    ANTENNAGATEAREA 0.196500 ;
    PORT
      LAYER met3 ;
        RECT 0.000 391.040 4.000 391.640 ;
    END
  END data_in[99]
  PIN data_in[9]
    DIRECTION INPUT ;
    USE SIGNAL ;
    ANTENNAGATEAREA 0.196500 ;
    PORT
      LAYER met2 ;
        RECT 486.310 646.000 486.590 650.000 ;
    END
  END data_in[9]
  PIN data_length[0]
    DIRECTION INPUT ;
    USE SIGNAL ;
    ANTENNAGATEAREA 0.213000 ;
    PORT
      LAYER met3 ;
        RECT 646.000 353.640 650.000 354.240 ;
    END
  END data_length[0]
  PIN data_length[1]
    DIRECTION INPUT ;
    USE SIGNAL ;
    ANTENNAGATEAREA 0.126000 ;
    PORT
      LAYER met3 ;
        RECT 646.000 357.040 650.000 357.640 ;
    END
  END data_length[1]
  PIN data_length[2]
    DIRECTION INPUT ;
    USE SIGNAL ;
    ANTENNAGATEAREA 0.213000 ;
    PORT
      LAYER met3 ;
        RECT 646.000 465.840 650.000 466.440 ;
    END
  END data_length[2]
  PIN data_length[3]
    DIRECTION INPUT ;
    USE SIGNAL ;
    ANTENNAGATEAREA 0.213000 ;
    PORT
      LAYER met3 ;
        RECT 646.000 360.440 650.000 361.040 ;
    END
  END data_length[3]
  PIN data_length[4]
    DIRECTION INPUT ;
    USE SIGNAL ;
    ANTENNAGATEAREA 0.213000 ;
    PORT
      LAYER met3 ;
        RECT 646.000 615.440 650.000 616.040 ;
    END
  END data_length[4]
  PIN data_out[0]
    DIRECTION OUTPUT ;
    USE SIGNAL ;
    ANTENNADIFFAREA 0.445500 ;
    PORT
      LAYER met2 ;
        RECT 489.530 646.000 489.810 650.000 ;
    END
  END data_out[0]
  PIN data_out[100]
    DIRECTION OUTPUT ;
    USE SIGNAL ;
    ANTENNADIFFAREA 0.445500 ;
    PORT
      LAYER met3 ;
        RECT 0.000 608.640 4.000 609.240 ;
    END
  END data_out[100]
  PIN data_out[101]
    DIRECTION OUTPUT ;
    USE SIGNAL ;
    ANTENNADIFFAREA 0.445500 ;
    PORT
      LAYER met2 ;
        RECT 202.950 646.000 203.230 650.000 ;
    END
  END data_out[101]
  PIN data_out[102]
    DIRECTION OUTPUT ;
    USE SIGNAL ;
    ANTENNADIFFAREA 0.445500 ;
    PORT
      LAYER met2 ;
        RECT 380.050 646.000 380.330 650.000 ;
    END
  END data_out[102]
  PIN data_out[103]
    DIRECTION OUTPUT ;
    USE SIGNAL ;
    ANTENNADIFFAREA 0.445500 ;
    PORT
      LAYER met3 ;
        RECT 646.000 493.040 650.000 493.640 ;
    END
  END data_out[103]
  PIN data_out[104]
    DIRECTION OUTPUT ;
    USE SIGNAL ;
    ANTENNADIFFAREA 0.445500 ;
    PORT
      LAYER met2 ;
        RECT 515.290 646.000 515.570 650.000 ;
    END
  END data_out[104]
  PIN data_out[105]
    DIRECTION OUTPUT ;
    USE SIGNAL ;
    ANTENNADIFFAREA 0.445500 ;
    PORT
      LAYER met2 ;
        RECT 492.750 646.000 493.030 650.000 ;
    END
  END data_out[105]
  PIN data_out[106]
    DIRECTION OUTPUT ;
    USE SIGNAL ;
    ANTENNADIFFAREA 0.445500 ;
    PORT
      LAYER met3 ;
        RECT 0.000 312.840 4.000 313.440 ;
    END
  END data_out[106]
  PIN data_out[107]
    DIRECTION OUTPUT ;
    USE SIGNAL ;
    ANTENNADIFFAREA 0.445500 ;
    PORT
      LAYER met3 ;
        RECT 0.000 431.840 4.000 432.440 ;
    END
  END data_out[107]
  PIN data_out[108]
    DIRECTION OUTPUT ;
    USE SIGNAL ;
    ANTENNADIFFAREA 0.445500 ;
    PORT
      LAYER met3 ;
        RECT 0.000 479.440 4.000 480.040 ;
    END
  END data_out[108]
  PIN data_out[109]
    DIRECTION OUTPUT ;
    USE SIGNAL ;
    ANTENNADIFFAREA 0.445500 ;
    PORT
      LAYER met2 ;
        RECT 135.330 646.000 135.610 650.000 ;
    END
  END data_out[109]
  PIN data_out[10]
    DIRECTION OUTPUT ;
    USE SIGNAL ;
    ANTENNADIFFAREA 0.445500 ;
    PORT
      LAYER met3 ;
        RECT 0.000 306.040 4.000 306.640 ;
    END
  END data_out[10]
  PIN data_out[110]
    DIRECTION OUTPUT ;
    USE SIGNAL ;
    ANTENNADIFFAREA 0.445500 ;
    PORT
      LAYER met2 ;
        RECT 325.310 646.000 325.590 650.000 ;
    END
  END data_out[110]
  PIN data_out[111]
    DIRECTION OUTPUT ;
    USE SIGNAL ;
    ANTENNADIFFAREA 0.445500 ;
    PORT
      LAYER met3 ;
        RECT 646.000 391.040 650.000 391.640 ;
    END
  END data_out[111]
  PIN data_out[112]
    DIRECTION OUTPUT ;
    USE SIGNAL ;
    ANTENNADIFFAREA 0.445500 ;
    PORT
      LAYER met2 ;
        RECT 570.030 646.000 570.310 650.000 ;
    END
  END data_out[112]
  PIN data_out[113]
    DIRECTION OUTPUT ;
    USE SIGNAL ;
    ANTENNADIFFAREA 0.445500 ;
    PORT
      LAYER met2 ;
        RECT 618.330 646.000 618.610 650.000 ;
    END
  END data_out[113]
  PIN data_out[114]
    DIRECTION OUTPUT ;
    USE SIGNAL ;
    ANTENNADIFFAREA 0.445500 ;
    PORT
      LAYER met2 ;
        RECT 25.850 646.000 26.130 650.000 ;
    END
  END data_out[114]
  PIN data_out[115]
    DIRECTION OUTPUT ;
    USE SIGNAL ;
    ANTENNADIFFAREA 0.445500 ;
    PORT
      LAYER met3 ;
        RECT 0.000 71.440 4.000 72.040 ;
    END
  END data_out[115]
  PIN data_out[116]
    DIRECTION OUTPUT ;
    USE SIGNAL ;
    ANTENNADIFFAREA 0.445500 ;
    PORT
      LAYER met2 ;
        RECT 151.430 646.000 151.710 650.000 ;
    END
  END data_out[116]
  PIN data_out[117]
    DIRECTION OUTPUT ;
    USE SIGNAL ;
    ANTENNADIFFAREA 0.445500 ;
    PORT
      LAYER met2 ;
        RECT 170.750 646.000 171.030 650.000 ;
    END
  END data_out[117]
  PIN data_out[118]
    DIRECTION OUTPUT ;
    USE SIGNAL ;
    ANTENNADIFFAREA 0.445500 ;
    PORT
      LAYER met2 ;
        RECT 389.710 646.000 389.990 650.000 ;
    END
  END data_out[118]
  PIN data_out[119]
    DIRECTION OUTPUT ;
    USE SIGNAL ;
    ANTENNADIFFAREA 0.445500 ;
    PORT
      LAYER met2 ;
        RECT 599.010 646.000 599.290 650.000 ;
    END
  END data_out[119]
  PIN data_out[11]
    DIRECTION OUTPUT ;
    USE SIGNAL ;
    ANTENNADIFFAREA 0.445500 ;
    PORT
      LAYER met3 ;
        RECT 0.000 421.640 4.000 422.240 ;
    END
  END data_out[11]
  PIN data_out[120]
    DIRECTION OUTPUT ;
    USE SIGNAL ;
    ANTENNADIFFAREA 0.445500 ;
    PORT
      LAYER met2 ;
        RECT 405.810 646.000 406.090 650.000 ;
    END
  END data_out[120]
  PIN data_out[121]
    DIRECTION OUTPUT ;
    USE SIGNAL ;
    ANTENNADIFFAREA 0.445500 ;
    PORT
      LAYER met2 ;
        RECT 254.470 646.000 254.750 650.000 ;
    END
  END data_out[121]
  PIN data_out[122]
    DIRECTION OUTPUT ;
    USE SIGNAL ;
    ANTENNADIFFAREA 0.445500 ;
    PORT
      LAYER met2 ;
        RECT 212.610 646.000 212.890 650.000 ;
    END
  END data_out[122]
  PIN data_out[123]
    DIRECTION OUTPUT ;
    USE SIGNAL ;
    ANTENNADIFFAREA 0.445500 ;
    PORT
      LAYER met3 ;
        RECT 0.000 622.240 4.000 622.840 ;
    END
  END data_out[123]
  PIN data_out[124]
    DIRECTION OUTPUT ;
    USE SIGNAL ;
    ANTENNADIFFAREA 0.445500 ;
    PORT
      LAYER met2 ;
        RECT 35.510 646.000 35.790 650.000 ;
    END
  END data_out[124]
  PIN data_out[125]
    DIRECTION OUTPUT ;
    USE SIGNAL ;
    ANTENNADIFFAREA 0.445500 ;
    PORT
      LAYER met2 ;
        RECT 87.030 646.000 87.310 650.000 ;
    END
  END data_out[125]
  PIN data_out[126]
    DIRECTION OUTPUT ;
    USE SIGNAL ;
    ANTENNADIFFAREA 0.445500 ;
    PORT
      LAYER met2 ;
        RECT 386.490 646.000 386.770 650.000 ;
    END
  END data_out[126]
  PIN data_out[127]
    DIRECTION OUTPUT ;
    USE SIGNAL ;
    ANTENNADIFFAREA 0.445500 ;
    PORT
      LAYER met2 ;
        RECT 602.230 646.000 602.510 650.000 ;
    END
  END data_out[127]
  PIN data_out[12]
    DIRECTION OUTPUT ;
    USE SIGNAL ;
    ANTENNADIFFAREA 0.445500 ;
    PORT
      LAYER met3 ;
        RECT 0.000 523.640 4.000 524.240 ;
    END
  END data_out[12]
  PIN data_out[13]
    DIRECTION OUTPUT ;
    USE SIGNAL ;
    ANTENNADIFFAREA 0.445500 ;
    PORT
      LAYER met2 ;
        RECT 225.490 646.000 225.770 650.000 ;
    END
  END data_out[13]
  PIN data_out[14]
    DIRECTION OUTPUT ;
    USE SIGNAL ;
    ANTENNADIFFAREA 0.445500 ;
    PORT
      LAYER met2 ;
        RECT 16.190 646.000 16.470 650.000 ;
    END
  END data_out[14]
  PIN data_out[15]
    DIRECTION OUTPUT ;
    USE SIGNAL ;
    ANTENNADIFFAREA 0.445500 ;
    PORT
      LAYER met3 ;
        RECT 646.000 523.640 650.000 524.240 ;
    END
  END data_out[15]
  PIN data_out[16]
    DIRECTION OUTPUT ;
    USE SIGNAL ;
    ANTENNADIFFAREA 0.445500 ;
    PORT
      LAYER met2 ;
        RECT 421.910 646.000 422.190 650.000 ;
    END
  END data_out[16]
  PIN data_out[17]
    DIRECTION OUTPUT ;
    USE SIGNAL ;
    ANTENNADIFFAREA 0.445500 ;
    PORT
      LAYER met2 ;
        RECT 631.210 646.000 631.490 650.000 ;
    END
  END data_out[17]
  PIN data_out[18]
    DIRECTION OUTPUT ;
    USE SIGNAL ;
    ANTENNADIFFAREA 0.445500 ;
    PORT
      LAYER met2 ;
        RECT 9.750 646.000 10.030 650.000 ;
    END
  END data_out[18]
  PIN data_out[19]
    DIRECTION OUTPUT ;
    USE SIGNAL ;
    ANTENNADIFFAREA 0.445500 ;
    PORT
      LAYER met3 ;
        RECT 0.000 44.240 4.000 44.840 ;
    END
  END data_out[19]
  PIN data_out[1]
    DIRECTION OUTPUT ;
    USE SIGNAL ;
    ANTENNADIFFAREA 0.445500 ;
    PORT
      LAYER met2 ;
        RECT 302.770 646.000 303.050 650.000 ;
    END
  END data_out[1]
  PIN data_out[20]
    DIRECTION OUTPUT ;
    USE SIGNAL ;
    ANTENNADIFFAREA 0.445500 ;
    PORT
      LAYER met2 ;
        RECT 164.310 646.000 164.590 650.000 ;
    END
  END data_out[20]
  PIN data_out[21]
    DIRECTION OUTPUT ;
    USE SIGNAL ;
    ANTENNADIFFAREA 0.445500 ;
    PORT
      LAYER met2 ;
        RECT 64.490 646.000 64.770 650.000 ;
    END
  END data_out[21]
  PIN data_out[22]
    DIRECTION OUTPUT ;
    USE SIGNAL ;
    ANTENNADIFFAREA 0.445500 ;
    PORT
      LAYER met2 ;
        RECT 109.570 646.000 109.850 650.000 ;
    END
  END data_out[22]
  PIN data_out[23]
    DIRECTION OUTPUT ;
    USE SIGNAL ;
    ANTENNADIFFAREA 0.445500 ;
    PORT
      LAYER met3 ;
        RECT 646.000 431.840 650.000 432.440 ;
    END
  END data_out[23]
  PIN data_out[24]
    DIRECTION OUTPUT ;
    USE SIGNAL ;
    ANTENNADIFFAREA 0.445500 ;
    PORT
      LAYER met2 ;
        RECT 566.810 646.000 567.090 650.000 ;
    END
  END data_out[24]
  PIN data_out[25]
    DIRECTION OUTPUT ;
    USE SIGNAL ;
    ANTENNADIFFAREA 0.445500 ;
    PORT
      LAYER met2 ;
        RECT 248.030 646.000 248.310 650.000 ;
    END
  END data_out[25]
  PIN data_out[26]
    DIRECTION OUTPUT ;
    USE SIGNAL ;
    ANTENNADIFFAREA 0.445500 ;
    PORT
      LAYER met3 ;
        RECT 0.000 295.840 4.000 296.440 ;
    END
  END data_out[26]
  PIN data_out[27]
    DIRECTION OUTPUT ;
    USE SIGNAL ;
    ANTENNADIFFAREA 0.445500 ;
    PORT
      LAYER met3 ;
        RECT 0.000 601.840 4.000 602.440 ;
    END
  END data_out[27]
  PIN data_out[28]
    DIRECTION OUTPUT ;
    USE SIGNAL ;
    ANTENNADIFFAREA 0.445500 ;
    PORT
      LAYER met2 ;
        RECT 141.770 646.000 142.050 650.000 ;
    END
  END data_out[28]
  PIN data_out[29]
    DIRECTION OUTPUT ;
    USE SIGNAL ;
    ANTENNADIFFAREA 0.445500 ;
    PORT
      LAYER met2 ;
        RECT 180.410 646.000 180.690 650.000 ;
    END
  END data_out[29]
  PIN data_out[2]
    DIRECTION OUTPUT ;
    USE SIGNAL ;
    ANTENNADIFFAREA 0.445500 ;
    PORT
      LAYER met3 ;
        RECT 0.000 285.640 4.000 286.240 ;
    END
  END data_out[2]
  PIN data_out[30]
    DIRECTION OUTPUT ;
    USE SIGNAL ;
    ANTENNADIFFAREA 0.445500 ;
    PORT
      LAYER met2 ;
        RECT 338.190 646.000 338.470 650.000 ;
    END
  END data_out[30]
  PIN data_out[31]
    DIRECTION OUTPUT ;
    USE SIGNAL ;
    ANTENNADIFFAREA 0.445500 ;
    PORT
      LAYER met2 ;
        RECT 553.930 646.000 554.210 650.000 ;
    END
  END data_out[31]
  PIN data_out[32]
    DIRECTION OUTPUT ;
    USE SIGNAL ;
    ANTENNADIFFAREA 0.445500 ;
    PORT
      LAYER met2 ;
        RECT 550.710 646.000 550.990 650.000 ;
    END
  END data_out[32]
  PIN data_out[33]
    DIRECTION OUTPUT ;
    USE SIGNAL ;
    ANTENNADIFFAREA 0.445500 ;
    PORT
      LAYER met2 ;
        RECT 647.310 646.000 647.590 650.000 ;
    END
  END data_out[33]
  PIN data_out[34]
    DIRECTION OUTPUT ;
    USE SIGNAL ;
    ANTENNADIFFAREA 0.445500 ;
    PORT
      LAYER met3 ;
        RECT 0.000 336.640 4.000 337.240 ;
    END
  END data_out[34]
  PIN data_out[35]
    DIRECTION OUTPUT ;
    USE SIGNAL ;
    ANTENNADIFFAREA 0.445500 ;
    PORT
      LAYER met3 ;
        RECT 0.000 272.040 4.000 272.640 ;
    END
  END data_out[35]
  PIN data_out[36]
    DIRECTION OUTPUT ;
    USE SIGNAL ;
    ANTENNADIFFAREA 0.445500 ;
    PORT
      LAYER met3 ;
        RECT 0.000 520.240 4.000 520.840 ;
    END
  END data_out[36]
  PIN data_out[37]
    DIRECTION OUTPUT ;
    USE SIGNAL ;
    ANTENNADIFFAREA 0.445500 ;
    PORT
      LAYER met2 ;
        RECT 41.950 646.000 42.230 650.000 ;
    END
  END data_out[37]
  PIN data_out[38]
    DIRECTION OUTPUT ;
    USE SIGNAL ;
    ANTENNADIFFAREA 0.445500 ;
    PORT
      LAYER met2 ;
        RECT 351.070 646.000 351.350 650.000 ;
    END
  END data_out[38]
  PIN data_out[39]
    DIRECTION OUTPUT ;
    USE SIGNAL ;
    ANTENNADIFFAREA 0.445500 ;
    PORT
      LAYER met3 ;
        RECT 646.000 445.440 650.000 446.040 ;
    END
  END data_out[39]
  PIN data_out[3]
    DIRECTION OUTPUT ;
    USE SIGNAL ;
    ANTENNADIFFAREA 0.445500 ;
    PORT
      LAYER met3 ;
        RECT 0.000 323.040 4.000 323.640 ;
    END
  END data_out[3]
  PIN data_out[40]
    DIRECTION OUTPUT ;
    USE SIGNAL ;
    ANTENNADIFFAREA 0.445500 ;
    PORT
      LAYER met3 ;
        RECT 646.000 499.840 650.000 500.440 ;
    END
  END data_out[40]
  PIN data_out[41]
    DIRECTION OUTPUT ;
    USE SIGNAL ;
    ANTENNADIFFAREA 0.445500 ;
    PORT
      LAYER met3 ;
        RECT 0.000 635.840 4.000 636.440 ;
    END
  END data_out[41]
  PIN data_out[42]
    DIRECTION OUTPUT ;
    USE SIGNAL ;
    ANTENNADIFFAREA 0.445500 ;
    PORT
      LAYER met3 ;
        RECT 0.000 299.240 4.000 299.840 ;
    END
  END data_out[42]
  PIN data_out[43]
    DIRECTION OUTPUT ;
    USE SIGNAL ;
    ANTENNADIFFAREA 0.445500 ;
    PORT
      LAYER met3 ;
        RECT 0.000 435.240 4.000 435.840 ;
    END
  END data_out[43]
  PIN data_out[44]
    DIRECTION OUTPUT ;
    USE SIGNAL ;
    ANTENNADIFFAREA 0.445500 ;
    PORT
      LAYER met3 ;
        RECT 0.000 506.640 4.000 507.240 ;
    END
  END data_out[44]
  PIN data_out[45]
    DIRECTION OUTPUT ;
    USE SIGNAL ;
    ANTENNADIFFAREA 0.445500 ;
    PORT
      LAYER met3 ;
        RECT 0.000 571.240 4.000 571.840 ;
    END
  END data_out[45]
  PIN data_out[46]
    DIRECTION OUTPUT ;
    USE SIGNAL ;
    ANTENNADIFFAREA 0.445500 ;
    PORT
      LAYER met3 ;
        RECT 0.000 632.440 4.000 633.040 ;
    END
  END data_out[46]
  PIN data_out[47]
    DIRECTION OUTPUT ;
    USE SIGNAL ;
    ANTENNADIFFAREA 0.445500 ;
    PORT
      LAYER met3 ;
        RECT 646.000 404.640 650.000 405.240 ;
    END
  END data_out[47]
  PIN data_out[48]
    DIRECTION OUTPUT ;
    USE SIGNAL ;
    ANTENNADIFFAREA 0.445500 ;
    PORT
      LAYER met3 ;
        RECT 646.000 557.640 650.000 558.240 ;
    END
  END data_out[48]
  PIN data_out[49]
    DIRECTION OUTPUT ;
    USE SIGNAL ;
    ANTENNADIFFAREA 0.445500 ;
    PORT
      LAYER met3 ;
        RECT 646.000 401.240 650.000 401.840 ;
    END
  END data_out[49]
  PIN data_out[4]
    DIRECTION OUTPUT ;
    USE SIGNAL ;
    ANTENNADIFFAREA 0.445500 ;
    PORT
      LAYER met3 ;
        RECT 0.000 465.840 4.000 466.440 ;
    END
  END data_out[4]
  PIN data_out[50]
    DIRECTION OUTPUT ;
    USE SIGNAL ;
    ANTENNADIFFAREA 0.445500 ;
    PORT
      LAYER met3 ;
        RECT 0.000 360.440 4.000 361.040 ;
    END
  END data_out[50]
  PIN data_out[51]
    DIRECTION OUTPUT ;
    USE SIGNAL ;
    ANTENNADIFFAREA 0.445500 ;
    PORT
      LAYER met3 ;
        RECT 0.000 64.640 4.000 65.240 ;
    END
  END data_out[51]
  PIN data_out[52]
    DIRECTION OUTPUT ;
    USE SIGNAL ;
    ANTENNADIFFAREA 0.445500 ;
    PORT
      LAYER met3 ;
        RECT 0.000 537.240 4.000 537.840 ;
    END
  END data_out[52]
  PIN data_out[53]
    DIRECTION OUTPUT ;
    USE SIGNAL ;
    ANTENNADIFFAREA 0.445500 ;
    PORT
      LAYER met3 ;
        RECT 0.000 598.440 4.000 599.040 ;
    END
  END data_out[53]
  PIN data_out[54]
    DIRECTION OUTPUT ;
    USE SIGNAL ;
    ANTENNADIFFAREA 0.445500 ;
    PORT
      LAYER met3 ;
        RECT 0.000 557.640 4.000 558.240 ;
    END
  END data_out[54]
  PIN data_out[55]
    DIRECTION OUTPUT ;
    USE SIGNAL ;
    ANTENNADIFFAREA 0.445500 ;
    PORT
      LAYER met3 ;
        RECT 646.000 537.240 650.000 537.840 ;
    END
  END data_out[55]
  PIN data_out[56]
    DIRECTION OUTPUT ;
    USE SIGNAL ;
    ANTENNADIFFAREA 0.445500 ;
    PORT
      LAYER met3 ;
        RECT 646.000 503.240 650.000 503.840 ;
    END
  END data_out[56]
  PIN data_out[57]
    DIRECTION OUTPUT ;
    USE SIGNAL ;
    ANTENNADIFFAREA 0.445500 ;
    PORT
      LAYER met3 ;
        RECT 0.000 639.240 4.000 639.840 ;
    END
  END data_out[57]
  PIN data_out[58]
    DIRECTION OUTPUT ;
    USE SIGNAL ;
    ANTENNADIFFAREA 0.445500 ;
    PORT
      LAYER met3 ;
        RECT 0.000 618.840 4.000 619.440 ;
    END
  END data_out[58]
  PIN data_out[59]
    DIRECTION OUTPUT ;
    USE SIGNAL ;
    ANTENNADIFFAREA 0.445500 ;
    PORT
      LAYER met3 ;
        RECT 0.000 445.440 4.000 446.040 ;
    END
  END data_out[59]
  PIN data_out[5]
    DIRECTION OUTPUT ;
    USE SIGNAL ;
    ANTENNADIFFAREA 0.445500 ;
    PORT
      LAYER met3 ;
        RECT 0.000 581.440 4.000 582.040 ;
    END
  END data_out[5]
  PIN data_out[60]
    DIRECTION OUTPUT ;
    USE SIGNAL ;
    ANTENNADIFFAREA 0.445500 ;
    PORT
      LAYER met3 ;
        RECT 0.000 510.040 4.000 510.640 ;
    END
  END data_out[60]
  PIN data_out[61]
    DIRECTION OUTPUT ;
    USE SIGNAL ;
    ANTENNADIFFAREA 0.445500 ;
    PORT
      LAYER met3 ;
        RECT 0.000 567.840 4.000 568.440 ;
    END
  END data_out[61]
  PIN data_out[62]
    DIRECTION OUTPUT ;
    USE SIGNAL ;
    ANTENNADIFFAREA 0.445500 ;
    PORT
      LAYER met3 ;
        RECT 646.000 482.840 650.000 483.440 ;
    END
  END data_out[62]
  PIN data_out[63]
    DIRECTION OUTPUT ;
    USE SIGNAL ;
    ANTENNADIFFAREA 0.445500 ;
    PORT
      LAYER met3 ;
        RECT 646.000 601.840 650.000 602.440 ;
    END
  END data_out[63]
  PIN data_out[64]
    DIRECTION OUTPUT ;
    USE SIGNAL ;
    ANTENNADIFFAREA 0.445500 ;
    PORT
      LAYER met3 ;
        RECT 646.000 547.440 650.000 548.040 ;
    END
  END data_out[64]
  PIN data_out[65]
    DIRECTION OUTPUT ;
    USE SIGNAL ;
    ANTENNADIFFAREA 0.445500 ;
    PORT
      LAYER met3 ;
        RECT 0.000 370.640 4.000 371.240 ;
    END
  END data_out[65]
  PIN data_out[66]
    DIRECTION OUTPUT ;
    USE SIGNAL ;
    ANTENNADIFFAREA 0.445500 ;
    PORT
      LAYER met3 ;
        RECT 0.000 95.240 4.000 95.840 ;
    END
  END data_out[66]
  PIN data_out[67]
    DIRECTION OUTPUT ;
    USE SIGNAL ;
    ANTENNADIFFAREA 0.445500 ;
    PORT
      LAYER met3 ;
        RECT 0.000 54.440 4.000 55.040 ;
    END
  END data_out[67]
  PIN data_out[68]
    DIRECTION OUTPUT ;
    USE SIGNAL ;
    ANTENNADIFFAREA 0.445500 ;
    PORT
      LAYER met3 ;
        RECT 0.000 533.840 4.000 534.440 ;
    END
  END data_out[68]
  PIN data_out[69]
    DIRECTION OUTPUT ;
    USE SIGNAL ;
    ANTENNADIFFAREA 0.445500 ;
    PORT
      LAYER met3 ;
        RECT 0.000 588.240 4.000 588.840 ;
    END
  END data_out[69]
  PIN data_out[6]
    DIRECTION OUTPUT ;
    USE SIGNAL ;
    ANTENNADIFFAREA 0.445500 ;
    PORT
      LAYER met3 ;
        RECT 646.000 605.240 650.000 605.840 ;
    END
  END data_out[6]
  PIN data_out[70]
    DIRECTION OUTPUT ;
    USE SIGNAL ;
    ANTENNADIFFAREA 0.445500 ;
    PORT
      LAYER met3 ;
        RECT 646.000 550.840 650.000 551.440 ;
    END
  END data_out[70]
  PIN data_out[71]
    DIRECTION OUTPUT ;
    USE SIGNAL ;
    ANTENNADIFFAREA 0.445500 ;
    PORT
      LAYER met3 ;
        RECT 646.000 438.640 650.000 439.240 ;
    END
  END data_out[71]
  PIN data_out[72]
    DIRECTION OUTPUT ;
    USE SIGNAL ;
    ANTENNADIFFAREA 0.445500 ;
    PORT
      LAYER met3 ;
        RECT 646.000 510.040 650.000 510.640 ;
    END
  END data_out[72]
  PIN data_out[73]
    DIRECTION OUTPUT ;
    USE SIGNAL ;
    ANTENNADIFFAREA 0.445500 ;
    PORT
      LAYER met3 ;
        RECT 646.000 435.240 650.000 435.840 ;
    END
  END data_out[73]
  PIN data_out[74]
    DIRECTION OUTPUT ;
    USE SIGNAL ;
    ANTENNADIFFAREA 0.445500 ;
    PORT
      LAYER met3 ;
        RECT 0.000 91.840 4.000 92.440 ;
    END
  END data_out[74]
  PIN data_out[75]
    DIRECTION OUTPUT ;
    USE SIGNAL ;
    ANTENNADIFFAREA 0.445500 ;
    PORT
      LAYER met3 ;
        RECT 0.000 397.840 4.000 398.440 ;
    END
  END data_out[75]
  PIN data_out[76]
    DIRECTION OUTPUT ;
    USE SIGNAL ;
    ANTENNADIFFAREA 0.445500 ;
    PORT
      LAYER met3 ;
        RECT 0.000 493.040 4.000 493.640 ;
    END
  END data_out[76]
  PIN data_out[77]
    DIRECTION OUTPUT ;
    USE SIGNAL ;
    ANTENNADIFFAREA 0.445500 ;
    PORT
      LAYER met3 ;
        RECT 0.000 625.640 4.000 626.240 ;
    END
  END data_out[77]
  PIN data_out[78]
    DIRECTION OUTPUT ;
    USE SIGNAL ;
    ANTENNADIFFAREA 0.445500 ;
    PORT
      LAYER met3 ;
        RECT 0.000 547.440 4.000 548.040 ;
    END
  END data_out[78]
  PIN data_out[79]
    DIRECTION OUTPUT ;
    USE SIGNAL ;
    ANTENNADIFFAREA 0.445500 ;
    PORT
      LAYER met3 ;
        RECT 646.000 612.040 650.000 612.640 ;
    END
  END data_out[79]
  PIN data_out[7]
    DIRECTION OUTPUT ;
    USE SIGNAL ;
    ANTENNADIFFAREA 0.445500 ;
    PORT
      LAYER met3 ;
        RECT 646.000 425.040 650.000 425.640 ;
    END
  END data_out[7]
  PIN data_out[80]
    DIRECTION OUTPUT ;
    USE SIGNAL ;
    ANTENNADIFFAREA 0.445500 ;
    PORT
      LAYER met3 ;
        RECT 646.000 554.240 650.000 554.840 ;
    END
  END data_out[80]
  PIN data_out[81]
    DIRECTION OUTPUT ;
    USE SIGNAL ;
    ANTENNADIFFAREA 0.445500 ;
    PORT
      LAYER met3 ;
        RECT 646.000 411.440 650.000 412.040 ;
    END
  END data_out[81]
  PIN data_out[82]
    DIRECTION OUTPUT ;
    USE SIGNAL ;
    ANTENNADIFFAREA 0.445500 ;
    PORT
      LAYER met3 ;
        RECT 0.000 353.640 4.000 354.240 ;
    END
  END data_out[82]
  PIN data_out[83]
    DIRECTION OUTPUT ;
    USE SIGNAL ;
    ANTENNADIFFAREA 0.445500 ;
    PORT
      LAYER met3 ;
        RECT 0.000 61.240 4.000 61.840 ;
    END
  END data_out[83]
  PIN data_out[84]
    DIRECTION OUTPUT ;
    USE SIGNAL ;
    ANTENNADIFFAREA 0.445500 ;
    PORT
      LAYER met3 ;
        RECT 0.000 574.640 4.000 575.240 ;
    END
  END data_out[84]
  PIN data_out[85]
    DIRECTION OUTPUT ;
    USE SIGNAL ;
    ANTENNADIFFAREA 0.445500 ;
    PORT
      LAYER met3 ;
        RECT 0.000 540.640 4.000 541.240 ;
    END
  END data_out[85]
  PIN data_out[86]
    DIRECTION OUTPUT ;
    USE SIGNAL ;
    ANTENNADIFFAREA 0.445500 ;
    PORT
      LAYER met3 ;
        RECT 0.000 629.040 4.000 629.640 ;
    END
  END data_out[86]
  PIN data_out[87]
    DIRECTION OUTPUT ;
    USE SIGNAL ;
    ANTENNADIFFAREA 0.445500 ;
    PORT
      LAYER met3 ;
        RECT 646.000 476.040 650.000 476.640 ;
    END
  END data_out[87]
  PIN data_out[88]
    DIRECTION OUTPUT ;
    USE SIGNAL ;
    ANTENNADIFFAREA 0.445500 ;
    PORT
      LAYER met3 ;
        RECT 646.000 516.840 650.000 517.440 ;
    END
  END data_out[88]
  PIN data_out[89]
    DIRECTION OUTPUT ;
    USE SIGNAL ;
    ANTENNADIFFAREA 0.445500 ;
    PORT
      LAYER met3 ;
        RECT 0.000 646.040 4.000 646.640 ;
    END
  END data_out[89]
  PIN data_out[8]
    DIRECTION OUTPUT ;
    USE SIGNAL ;
    ANTENNADIFFAREA 0.445500 ;
    PORT
      LAYER met3 ;
        RECT 646.000 629.040 650.000 629.640 ;
    END
  END data_out[8]
  PIN data_out[90]
    DIRECTION OUTPUT ;
    USE SIGNAL ;
    ANTENNADIFFAREA 0.445500 ;
    PORT
      LAYER met3 ;
        RECT 0.000 550.840 4.000 551.440 ;
    END
  END data_out[90]
  PIN data_out[91]
    DIRECTION OUTPUT ;
    USE SIGNAL ;
    ANTENNADIFFAREA 0.445500 ;
    PORT
      LAYER met3 ;
        RECT 0.000 418.240 4.000 418.840 ;
    END
  END data_out[91]
  PIN data_out[92]
    DIRECTION OUTPUT ;
    USE SIGNAL ;
    ANTENNADIFFAREA 0.445500 ;
    PORT
      LAYER met3 ;
        RECT 0.000 527.040 4.000 527.640 ;
    END
  END data_out[92]
  PIN data_out[93]
    DIRECTION OUTPUT ;
    USE SIGNAL ;
    ANTENNADIFFAREA 0.445500 ;
    PORT
      LAYER met3 ;
        RECT 0.000 595.040 4.000 595.640 ;
    END
  END data_out[93]
  PIN data_out[94]
    DIRECTION OUTPUT ;
    USE SIGNAL ;
    ANTENNADIFFAREA 0.445500 ;
    PORT
      LAYER met3 ;
        RECT 646.000 506.640 650.000 507.240 ;
    END
  END data_out[94]
  PIN data_out[95]
    DIRECTION OUTPUT ;
    USE SIGNAL ;
    ANTENNADIFFAREA 0.445500 ;
    PORT
      LAYER met3 ;
        RECT 646.000 459.040 650.000 459.640 ;
    END
  END data_out[95]
  PIN data_out[96]
    DIRECTION OUTPUT ;
    USE SIGNAL ;
    ANTENNADIFFAREA 0.445500 ;
    PORT
      LAYER met3 ;
        RECT 646.000 527.040 650.000 527.640 ;
    END
  END data_out[96]
  PIN data_out[97]
    DIRECTION OUTPUT ;
    USE SIGNAL ;
    ANTENNADIFFAREA 0.445500 ;
    PORT
      LAYER met3 ;
        RECT 646.000 374.040 650.000 374.640 ;
    END
  END data_out[97]
  PIN data_out[98]
    DIRECTION OUTPUT ;
    USE SIGNAL ;
    ANTENNADIFFAREA 0.445500 ;
    PORT
      LAYER met3 ;
        RECT 0.000 261.840 4.000 262.440 ;
    END
  END data_out[98]
  PIN data_out[99]
    DIRECTION OUTPUT ;
    USE SIGNAL ;
    ANTENNADIFFAREA 0.445500 ;
    PORT
      LAYER met3 ;
        RECT 0.000 13.640 4.000 14.240 ;
    END
  END data_out[99]
  PIN data_out[9]
    DIRECTION OUTPUT ;
    USE SIGNAL ;
    ANTENNADIFFAREA 0.445500 ;
    PORT
      LAYER met3 ;
        RECT 646.000 462.440 650.000 463.040 ;
    END
  END data_out[9]
  PIN done
    DIRECTION OUTPUT ;
    USE SIGNAL ;
    ANTENNADIFFAREA 0.445500 ;
    PORT
      LAYER met3 ;
        RECT 646.000 312.840 650.000 313.440 ;
    END
  END done
  PIN ena
    DIRECTION INPUT ;
    USE SIGNAL ;
    ANTENNAGATEAREA 0.213000 ;
    PORT
      LAYER met3 ;
        RECT 646.000 289.040 650.000 289.640 ;
    END
  END ena
  PIN key[0]
    DIRECTION INPUT ;
    USE SIGNAL ;
    ANTENNAGATEAREA 0.213000 ;
    PORT
      LAYER met2 ;
        RECT 582.910 0.000 583.190 4.000 ;
    END
  END key[0]
  PIN key[100]
    DIRECTION INPUT ;
    USE SIGNAL ;
    ANTENNAGATEAREA 0.196500 ;
    PORT
      LAYER met2 ;
        RECT 58.050 0.000 58.330 4.000 ;
    END
  END key[100]
  PIN key[101]
    DIRECTION INPUT ;
    USE SIGNAL ;
    ANTENNAGATEAREA 0.196500 ;
    PORT
      LAYER met2 ;
        RECT 370.390 0.000 370.670 4.000 ;
    END
  END key[101]
  PIN key[102]
    DIRECTION INPUT ;
    USE SIGNAL ;
    ANTENNAGATEAREA 0.196500 ;
    PORT
      LAYER met2 ;
        RECT 231.930 0.000 232.210 4.000 ;
    END
  END key[102]
  PIN key[103]
    DIRECTION INPUT ;
    USE SIGNAL ;
    ANTENNAGATEAREA 0.213000 ;
    PORT
      LAYER met3 ;
        RECT 0.000 27.240 4.000 27.840 ;
    END
  END key[103]
  PIN key[104]
    DIRECTION INPUT ;
    USE SIGNAL ;
    ANTENNAGATEAREA 0.213000 ;
    PORT
      LAYER met2 ;
        RECT 80.590 0.000 80.870 4.000 ;
    END
  END key[104]
  PIN key[105]
    DIRECTION INPUT ;
    USE SIGNAL ;
    ANTENNAGATEAREA 0.196500 ;
    PORT
      LAYER met2 ;
        RECT 254.470 0.000 254.750 4.000 ;
    END
  END key[105]
  PIN key[106]
    DIRECTION INPUT ;
    USE SIGNAL ;
    ANTENNAGATEAREA 0.196500 ;
    PORT
      LAYER met2 ;
        RECT 550.710 0.000 550.990 4.000 ;
    END
  END key[106]
  PIN key[107]
    DIRECTION INPUT ;
    USE SIGNAL ;
    ANTENNAGATEAREA 0.196500 ;
    PORT
      LAYER met2 ;
        RECT 157.870 0.000 158.150 4.000 ;
    END
  END key[107]
  PIN key[108]
    DIRECTION INPUT ;
    USE SIGNAL ;
    ANTENNAGATEAREA 0.196500 ;
    PORT
      LAYER met3 ;
        RECT 0.000 149.640 4.000 150.240 ;
    END
  END key[108]
  PIN key[109]
    DIRECTION INPUT ;
    USE SIGNAL ;
    ANTENNAGATEAREA 0.196500 ;
    PORT
      LAYER met3 ;
        RECT 0.000 85.040 4.000 85.640 ;
    END
  END key[109]
  PIN key[10]
    DIRECTION INPUT ;
    USE SIGNAL ;
    ANTENNAGATEAREA 0.196500 ;
    PORT
      LAYER met2 ;
        RECT 425.130 0.000 425.410 4.000 ;
    END
  END key[10]
  PIN key[110]
    DIRECTION INPUT ;
    USE SIGNAL ;
    ANTENNAGATEAREA 0.196500 ;
    PORT
      LAYER met2 ;
        RECT 322.090 0.000 322.370 4.000 ;
    END
  END key[110]
  PIN key[111]
    DIRECTION INPUT ;
    USE SIGNAL ;
    ANTENNAGATEAREA 0.213000 ;
    PORT
      LAYER met2 ;
        RECT 563.590 0.000 563.870 4.000 ;
    END
  END key[111]
  PIN key[112]
    DIRECTION INPUT ;
    USE SIGNAL ;
    ANTENNAGATEAREA 0.196500 ;
    PORT
      LAYER met2 ;
        RECT 541.050 0.000 541.330 4.000 ;
    END
  END key[112]
  PIN key[113]
    DIRECTION INPUT ;
    USE SIGNAL ;
    ANTENNAGATEAREA 0.196500 ;
    PORT
      LAYER met2 ;
        RECT 125.670 0.000 125.950 4.000 ;
    END
  END key[113]
  PIN key[114]
    DIRECTION INPUT ;
    USE SIGNAL ;
    ANTENNAGATEAREA 0.196500 ;
    PORT
      LAYER met3 ;
        RECT 0.000 136.040 4.000 136.640 ;
    END
  END key[114]
  PIN key[115]
    DIRECTION INPUT ;
    USE SIGNAL ;
    ANTENNAGATEAREA 0.196500 ;
    PORT
      LAYER met2 ;
        RECT 196.510 0.000 196.790 4.000 ;
    END
  END key[115]
  PIN key[116]
    DIRECTION INPUT ;
    USE SIGNAL ;
    ANTENNAGATEAREA 0.196500 ;
    PORT
      LAYER met2 ;
        RECT 363.950 0.000 364.230 4.000 ;
    END
  END key[116]
  PIN key[117]
    DIRECTION INPUT ;
    USE SIGNAL ;
    ANTENNAGATEAREA 0.196500 ;
    PORT
      LAYER met2 ;
        RECT 302.770 0.000 303.050 4.000 ;
    END
  END key[117]
  PIN key[118]
    DIRECTION INPUT ;
    USE SIGNAL ;
    ANTENNAGATEAREA 0.196500 ;
    PORT
      LAYER met2 ;
        RECT 177.190 0.000 177.470 4.000 ;
    END
  END key[118]
  PIN key[119]
    DIRECTION INPUT ;
    USE SIGNAL ;
    ANTENNAGATEAREA 0.196500 ;
    PORT
      LAYER met2 ;
        RECT 267.350 0.000 267.630 4.000 ;
    END
  END key[119]
  PIN key[11]
    DIRECTION INPUT ;
    USE SIGNAL ;
    ANTENNAGATEAREA 0.196500 ;
    PORT
      LAYER met2 ;
        RECT 164.310 0.000 164.590 4.000 ;
    END
  END key[11]
  PIN key[120]
    DIRECTION INPUT ;
    USE SIGNAL ;
    ANTENNAGATEAREA 0.196500 ;
    PORT
      LAYER met2 ;
        RECT 576.470 0.000 576.750 4.000 ;
    END
  END key[120]
  PIN key[121]
    DIRECTION INPUT ;
    USE SIGNAL ;
    ANTENNAGATEAREA 0.196500 ;
    PORT
      LAYER met2 ;
        RECT 373.610 0.000 373.890 4.000 ;
    END
  END key[121]
  PIN key[122]
    DIRECTION INPUT ;
    USE SIGNAL ;
    ANTENNAGATEAREA 0.126000 ;
    PORT
      LAYER met2 ;
        RECT 90.250 0.000 90.530 4.000 ;
    END
  END key[122]
  PIN key[123]
    DIRECTION INPUT ;
    USE SIGNAL ;
    ANTENNAGATEAREA 0.196500 ;
    PORT
      LAYER met2 ;
        RECT 512.070 0.000 512.350 4.000 ;
    END
  END key[123]
  PIN key[124]
    DIRECTION INPUT ;
    USE SIGNAL ;
    ANTENNAGATEAREA 0.213000 ;
    PORT
      LAYER met2 ;
        RECT 170.750 0.000 171.030 4.000 ;
    END
  END key[124]
  PIN key[125]
    DIRECTION INPUT ;
    USE SIGNAL ;
    ANTENNAGATEAREA 0.196500 ;
    PORT
      LAYER met3 ;
        RECT 0.000 173.440 4.000 174.040 ;
    END
  END key[125]
  PIN key[126]
    DIRECTION INPUT ;
    USE SIGNAL ;
    ANTENNAGATEAREA 0.196500 ;
    PORT
      LAYER met2 ;
        RECT 418.690 0.000 418.970 4.000 ;
    END
  END key[126]
  PIN key[127]
    DIRECTION INPUT ;
    USE SIGNAL ;
    ANTENNAGATEAREA 0.196500 ;
    PORT
      LAYER met2 ;
        RECT 450.890 0.000 451.170 4.000 ;
    END
  END key[127]
  PIN key[12]
    DIRECTION INPUT ;
    USE SIGNAL ;
    ANTENNAGATEAREA 0.196500 ;
    PORT
      LAYER met3 ;
        RECT 0.000 119.040 4.000 119.640 ;
    END
  END key[12]
  PIN key[13]
    DIRECTION INPUT ;
    USE SIGNAL ;
    ANTENNAGATEAREA 0.196500 ;
    PORT
      LAYER met3 ;
        RECT 0.000 190.440 4.000 191.040 ;
    END
  END key[13]
  PIN key[14]
    DIRECTION INPUT ;
    USE SIGNAL ;
    ANTENNAGATEAREA 0.213000 ;
    PORT
      LAYER met2 ;
        RECT 77.370 0.000 77.650 4.000 ;
    END
  END key[14]
  PIN key[15]
    DIRECTION INPUT ;
    USE SIGNAL ;
    ANTENNAGATEAREA 0.196500 ;
    PORT
      LAYER met2 ;
        RECT 396.150 0.000 396.430 4.000 ;
    END
  END key[15]
  PIN key[16]
    DIRECTION INPUT ;
    USE SIGNAL ;
    ANTENNAGATEAREA 0.196500 ;
    PORT
      LAYER met2 ;
        RECT 431.570 0.000 431.850 4.000 ;
    END
  END key[16]
  PIN key[17]
    DIRECTION INPUT ;
    USE SIGNAL ;
    ANTENNAGATEAREA 0.196500 ;
    PORT
      LAYER met2 ;
        RECT 228.710 0.000 228.990 4.000 ;
    END
  END key[17]
  PIN key[18]
    DIRECTION INPUT ;
    USE SIGNAL ;
    ANTENNAGATEAREA 0.196500 ;
    PORT
      LAYER met3 ;
        RECT 0.000 187.040 4.000 187.640 ;
    END
  END key[18]
  PIN key[19]
    DIRECTION INPUT ;
    USE SIGNAL ;
    ANTENNAGATEAREA 0.196500 ;
    PORT
      LAYER met2 ;
        RECT 190.070 0.000 190.350 4.000 ;
    END
  END key[19]
  PIN key[1]
    DIRECTION INPUT ;
    USE SIGNAL ;
    ANTENNAGATEAREA 0.196500 ;
    PORT
      LAYER met3 ;
        RECT 0.000 78.240 4.000 78.840 ;
    END
  END key[1]
  PIN key[20]
    DIRECTION INPUT ;
    USE SIGNAL ;
    ANTENNAGATEAREA 0.196500 ;
    PORT
      LAYER met2 ;
        RECT 325.310 0.000 325.590 4.000 ;
    END
  END key[20]
  PIN key[21]
    DIRECTION INPUT ;
    USE SIGNAL ;
    ANTENNAGATEAREA 0.196500 ;
    PORT
      LAYER met2 ;
        RECT 283.450 0.000 283.730 4.000 ;
    END
  END key[21]
  PIN key[22]
    DIRECTION INPUT ;
    USE SIGNAL ;
    ANTENNAGATEAREA 0.196500 ;
    PORT
      LAYER met2 ;
        RECT 202.950 0.000 203.230 4.000 ;
    END
  END key[22]
  PIN key[23]
    DIRECTION INPUT ;
    USE SIGNAL ;
    ANTENNAGATEAREA 0.196500 ;
    PORT
      LAYER met2 ;
        RECT 135.330 0.000 135.610 4.000 ;
    END
  END key[23]
  PIN key[24]
    DIRECTION INPUT ;
    USE SIGNAL ;
    ANTENNAGATEAREA 0.196500 ;
    PORT
      LAYER met2 ;
        RECT 412.250 0.000 412.530 4.000 ;
    END
  END key[24]
  PIN key[25]
    DIRECTION INPUT ;
    USE SIGNAL ;
    ANTENNAGATEAREA 0.213000 ;
    PORT
      LAYER met2 ;
        RECT 64.490 0.000 64.770 4.000 ;
    END
  END key[25]
  PIN key[26]
    DIRECTION INPUT ;
    USE SIGNAL ;
    ANTENNAGATEAREA 0.196500 ;
    PORT
      LAYER met2 ;
        RECT 273.790 0.000 274.070 4.000 ;
    END
  END key[26]
  PIN key[27]
    DIRECTION INPUT ;
    USE SIGNAL ;
    ANTENNAGATEAREA 0.196500 ;
    PORT
      LAYER met2 ;
        RECT 428.350 0.000 428.630 4.000 ;
    END
  END key[27]
  PIN key[28]
    DIRECTION INPUT ;
    USE SIGNAL ;
    ANTENNAGATEAREA 0.196500 ;
    PORT
      LAYER met3 ;
        RECT 0.000 159.840 4.000 160.440 ;
    END
  END key[28]
  PIN key[29]
    DIRECTION INPUT ;
    USE SIGNAL ;
    ANTENNAGATEAREA 0.196500 ;
    PORT
      LAYER met3 ;
        RECT 0.000 200.640 4.000 201.240 ;
    END
  END key[29]
  PIN key[2]
    DIRECTION INPUT ;
    USE SIGNAL ;
    ANTENNAGATEAREA 0.196500 ;
    PORT
      LAYER met3 ;
        RECT 0.000 183.640 4.000 184.240 ;
    END
  END key[2]
  PIN key[30]
    DIRECTION INPUT ;
    USE SIGNAL ;
    ANTENNAGATEAREA 0.196500 ;
    PORT
      LAYER met2 ;
        RECT 354.290 0.000 354.570 4.000 ;
    END
  END key[30]
  PIN key[31]
    DIRECTION INPUT ;
    USE SIGNAL ;
    ANTENNAGATEAREA 0.196500 ;
    PORT
      LAYER met2 ;
        RECT 447.670 0.000 447.950 4.000 ;
    END
  END key[31]
  PIN key[32]
    DIRECTION INPUT ;
    USE SIGNAL ;
    ANTENNAGATEAREA 0.196500 ;
    PORT
      LAYER met2 ;
        RECT 389.710 0.000 389.990 4.000 ;
    END
  END key[32]
  PIN key[33]
    DIRECTION INPUT ;
    USE SIGNAL ;
    ANTENNAGATEAREA 0.196500 ;
    PORT
      LAYER met3 ;
        RECT 0.000 112.240 4.000 112.840 ;
    END
  END key[33]
  PIN key[34]
    DIRECTION INPUT ;
    USE SIGNAL ;
    ANTENNAGATEAREA 0.196500 ;
    PORT
      LAYER met3 ;
        RECT 0.000 20.440 4.000 21.040 ;
    END
  END key[34]
  PIN key[35]
    DIRECTION INPUT ;
    USE SIGNAL ;
    ANTENNAGATEAREA 0.196500 ;
    PORT
      LAYER met3 ;
        RECT 0.000 129.240 4.000 129.840 ;
    END
  END key[35]
  PIN key[36]
    DIRECTION INPUT ;
    USE SIGNAL ;
    ANTENNAGATEAREA 0.196500 ;
    PORT
      LAYER met3 ;
        RECT 0.000 37.440 4.000 38.040 ;
    END
  END key[36]
  PIN key[37]
    DIRECTION INPUT ;
    USE SIGNAL ;
    ANTENNAGATEAREA 0.196500 ;
    PORT
      LAYER met2 ;
        RECT 357.510 0.000 357.790 4.000 ;
    END
  END key[37]
  PIN key[38]
    DIRECTION INPUT ;
    USE SIGNAL ;
    ANTENNAGATEAREA 0.196500 ;
    PORT
      LAYER met2 ;
        RECT 219.050 0.000 219.330 4.000 ;
    END
  END key[38]
  PIN key[39]
    DIRECTION INPUT ;
    USE SIGNAL ;
    ANTENNAGATEAREA 0.196500 ;
    PORT
      LAYER met3 ;
        RECT 0.000 139.440 4.000 140.040 ;
    END
  END key[39]
  PIN key[3]
    DIRECTION INPUT ;
    USE SIGNAL ;
    ANTENNAGATEAREA 0.196500 ;
    PORT
      LAYER met3 ;
        RECT 0.000 207.440 4.000 208.040 ;
    END
  END key[3]
  PIN key[40]
    DIRECTION INPUT ;
    USE SIGNAL ;
    ANTENNAGATEAREA 0.196500 ;
    PORT
      LAYER met2 ;
        RECT 286.670 0.000 286.950 4.000 ;
    END
  END key[40]
  PIN key[41]
    DIRECTION INPUT ;
    USE SIGNAL ;
    ANTENNAGATEAREA 0.196500 ;
    PORT
      LAYER met2 ;
        RECT 128.890 0.000 129.170 4.000 ;
    END
  END key[41]
  PIN key[42]
    DIRECTION INPUT ;
    USE SIGNAL ;
    ANTENNAGATEAREA 0.196500 ;
    PORT
      LAYER met2 ;
        RECT 470.210 0.000 470.490 4.000 ;
    END
  END key[42]
  PIN key[43]
    DIRECTION INPUT ;
    USE SIGNAL ;
    ANTENNAGATEAREA 0.196500 ;
    PORT
      LAYER met2 ;
        RECT 167.530 0.000 167.810 4.000 ;
    END
  END key[43]
  PIN key[44]
    DIRECTION INPUT ;
    USE SIGNAL ;
    ANTENNAGATEAREA 0.196500 ;
    PORT
      LAYER met3 ;
        RECT 0.000 40.840 4.000 41.440 ;
    END
  END key[44]
  PIN key[45]
    DIRECTION INPUT ;
    USE SIGNAL ;
    ANTENNAGATEAREA 0.196500 ;
    PORT
      LAYER met3 ;
        RECT 0.000 115.640 4.000 116.240 ;
    END
  END key[45]
  PIN key[46]
    DIRECTION INPUT ;
    USE SIGNAL ;
    ANTENNAGATEAREA 0.196500 ;
    PORT
      LAYER met2 ;
        RECT 305.990 0.000 306.270 4.000 ;
    END
  END key[46]
  PIN key[47]
    DIRECTION INPUT ;
    USE SIGNAL ;
    ANTENNAGATEAREA 0.196500 ;
    PORT
      LAYER met2 ;
        RECT 376.830 0.000 377.110 4.000 ;
    END
  END key[47]
  PIN key[48]
    DIRECTION INPUT ;
    USE SIGNAL ;
    ANTENNAGATEAREA 0.196500 ;
    PORT
      LAYER met2 ;
        RECT 463.770 0.000 464.050 4.000 ;
    END
  END key[48]
  PIN key[49]
    DIRECTION INPUT ;
    USE SIGNAL ;
    ANTENNAGATEAREA 0.196500 ;
    PORT
      LAYER met2 ;
        RECT 144.990 0.000 145.270 4.000 ;
    END
  END key[49]
  PIN key[4]
    DIRECTION INPUT ;
    USE SIGNAL ;
    ANTENNAGATEAREA 0.196500 ;
    PORT
      LAYER met2 ;
        RECT 141.770 0.000 142.050 4.000 ;
    END
  END key[4]
  PIN key[50]
    DIRECTION INPUT ;
    USE SIGNAL ;
    ANTENNAGATEAREA 0.196500 ;
    PORT
      LAYER met3 ;
        RECT 0.000 51.040 4.000 51.640 ;
    END
  END key[50]
  PIN key[51]
    DIRECTION INPUT ;
    USE SIGNAL ;
    ANTENNAGATEAREA 0.196500 ;
    PORT
      LAYER met2 ;
        RECT 183.630 0.000 183.910 4.000 ;
    END
  END key[51]
  PIN key[52]
    DIRECTION INPUT ;
    USE SIGNAL ;
    ANTENNAGATEAREA 0.196500 ;
    PORT
      LAYER met2 ;
        RECT 318.870 0.000 319.150 4.000 ;
    END
  END key[52]
  PIN key[53]
    DIRECTION INPUT ;
    USE SIGNAL ;
    ANTENNAGATEAREA 0.196500 ;
    PORT
      LAYER met2 ;
        RECT 280.230 0.000 280.510 4.000 ;
    END
  END key[53]
  PIN key[54]
    DIRECTION INPUT ;
    USE SIGNAL ;
    ANTENNAGATEAREA 0.196500 ;
    PORT
      LAYER met2 ;
        RECT 199.730 0.000 200.010 4.000 ;
    END
  END key[54]
  PIN key[55]
    DIRECTION INPUT ;
    USE SIGNAL ;
    ANTENNAGATEAREA 0.196500 ;
    PORT
      LAYER met2 ;
        RECT 241.590 0.000 241.870 4.000 ;
    END
  END key[55]
  PIN key[56]
    DIRECTION INPUT ;
    USE SIGNAL ;
    ANTENNAGATEAREA 0.196500 ;
    PORT
      LAYER met2 ;
        RECT 399.370 0.000 399.650 4.000 ;
    END
  END key[56]
  PIN key[57]
    DIRECTION INPUT ;
    USE SIGNAL ;
    ANTENNAGATEAREA 0.196500 ;
    PORT
      LAYER met2 ;
        RECT 315.650 0.000 315.930 4.000 ;
    END
  END key[57]
  PIN key[58]
    DIRECTION INPUT ;
    USE SIGNAL ;
    ANTENNAGATEAREA 0.196500 ;
    PORT
      LAYER met2 ;
        RECT 122.450 0.000 122.730 4.000 ;
    END
  END key[58]
  PIN key[59]
    DIRECTION INPUT ;
    USE SIGNAL ;
    ANTENNAGATEAREA 0.196500 ;
    PORT
      LAYER met2 ;
        RECT 560.370 0.000 560.650 4.000 ;
    END
  END key[59]
  PIN key[5]
    DIRECTION INPUT ;
    USE SIGNAL ;
    ANTENNAGATEAREA 0.196500 ;
    PORT
      LAYER met2 ;
        RECT 392.930 0.000 393.210 4.000 ;
    END
  END key[5]
  PIN key[60]
    DIRECTION INPUT ;
    USE SIGNAL ;
    ANTENNAGATEAREA 0.196500 ;
    PORT
      LAYER met3 ;
        RECT 0.000 166.640 4.000 167.240 ;
    END
  END key[60]
  PIN key[61]
    DIRECTION INPUT ;
    USE SIGNAL ;
    ANTENNAGATEAREA 0.196500 ;
    PORT
      LAYER met3 ;
        RECT 0.000 74.840 4.000 75.440 ;
    END
  END key[61]
  PIN key[62]
    DIRECTION INPUT ;
    USE SIGNAL ;
    ANTENNAGATEAREA 0.196500 ;
    PORT
      LAYER met2 ;
        RECT 341.410 0.000 341.690 4.000 ;
    END
  END key[62]
  PIN key[63]
    DIRECTION INPUT ;
    USE SIGNAL ;
    ANTENNAGATEAREA 0.196500 ;
    PORT
      LAYER met2 ;
        RECT 421.910 0.000 422.190 4.000 ;
    END
  END key[63]
  PIN key[64]
    DIRECTION INPUT ;
    USE SIGNAL ;
    ANTENNAGATEAREA 0.196500 ;
    PORT
      LAYER met2 ;
        RECT 402.590 0.000 402.870 4.000 ;
    END
  END key[64]
  PIN key[65]
    DIRECTION INPUT ;
    USE SIGNAL ;
    ANTENNAGATEAREA 0.196500 ;
    PORT
      LAYER met3 ;
        RECT 0.000 163.240 4.000 163.840 ;
    END
  END key[65]
  PIN key[66]
    DIRECTION INPUT ;
    USE SIGNAL ;
    ANTENNAGATEAREA 0.196500 ;
    PORT
      LAYER met3 ;
        RECT 0.000 125.840 4.000 126.440 ;
    END
  END key[66]
  PIN key[67]
    DIRECTION INPUT ;
    USE SIGNAL ;
    ANTENNAGATEAREA 0.196500 ;
    PORT
      LAYER met3 ;
        RECT 0.000 102.040 4.000 102.640 ;
    END
  END key[67]
  PIN key[68]
    DIRECTION INPUT ;
    USE SIGNAL ;
    ANTENNAGATEAREA 0.196500 ;
    PORT
      LAYER met2 ;
        RECT 148.210 0.000 148.490 4.000 ;
    END
  END key[68]
  PIN key[69]
    DIRECTION INPUT ;
    USE SIGNAL ;
    ANTENNAGATEAREA 0.196500 ;
    PORT
      LAYER met2 ;
        RECT 383.270 0.000 383.550 4.000 ;
    END
  END key[69]
  PIN key[6]
    DIRECTION INPUT ;
    USE SIGNAL ;
    ANTENNAGATEAREA 0.196500 ;
    PORT
      LAYER met2 ;
        RECT 225.490 0.000 225.770 4.000 ;
    END
  END key[6]
  PIN key[70]
    DIRECTION INPUT ;
    USE SIGNAL ;
    ANTENNAGATEAREA 0.196500 ;
    PORT
      LAYER met2 ;
        RECT 222.270 0.000 222.550 4.000 ;
    END
  END key[70]
  PIN key[71]
    DIRECTION INPUT ;
    USE SIGNAL ;
    ANTENNAGATEAREA 0.196500 ;
    PORT
      LAYER met3 ;
        RECT 0.000 221.040 4.000 221.640 ;
    END
  END key[71]
  PIN key[72]
    DIRECTION INPUT ;
    USE SIGNAL ;
    ANTENNAGATEAREA 0.196500 ;
    PORT
      LAYER met2 ;
        RECT 299.550 0.000 299.830 4.000 ;
    END
  END key[72]
  PIN key[73]
    DIRECTION INPUT ;
    USE SIGNAL ;
    ANTENNAGATEAREA 0.196500 ;
    PORT
      LAYER met2 ;
        RECT 264.130 0.000 264.410 4.000 ;
    END
  END key[73]
  PIN key[74]
    DIRECTION INPUT ;
    USE SIGNAL ;
    ANTENNAGATEAREA 0.196500 ;
    PORT
      LAYER met2 ;
        RECT 409.030 0.000 409.310 4.000 ;
    END
  END key[74]
  PIN key[75]
    DIRECTION INPUT ;
    USE SIGNAL ;
    ANTENNAGATEAREA 0.196500 ;
    PORT
      LAYER met2 ;
        RECT 180.410 0.000 180.690 4.000 ;
    END
  END key[75]
  PIN key[76]
    DIRECTION INPUT ;
    USE SIGNAL ;
    ANTENNAGATEAREA 0.196500 ;
    PORT
      LAYER met3 ;
        RECT 0.000 197.240 4.000 197.840 ;
    END
  END key[76]
  PIN key[77]
    DIRECTION INPUT ;
    USE SIGNAL ;
    ANTENNAGATEAREA 0.196500 ;
    PORT
      LAYER met3 ;
        RECT 0.000 10.240 4.000 10.840 ;
    END
  END key[77]
  PIN key[78]
    DIRECTION INPUT ;
    USE SIGNAL ;
    ANTENNAGATEAREA 0.213000 ;
    PORT
      LAYER met2 ;
        RECT 67.710 0.000 67.990 4.000 ;
    END
  END key[78]
  PIN key[79]
    DIRECTION INPUT ;
    USE SIGNAL ;
    ANTENNAGATEAREA 0.196500 ;
    PORT
      LAYER met2 ;
        RECT 380.050 0.000 380.330 4.000 ;
    END
  END key[79]
  PIN key[7]
    DIRECTION INPUT ;
    USE SIGNAL ;
    ANTENNAGATEAREA 0.196500 ;
    PORT
      LAYER met3 ;
        RECT 0.000 241.440 4.000 242.040 ;
    END
  END key[7]
  PIN key[80]
    DIRECTION INPUT ;
    USE SIGNAL ;
    ANTENNAGATEAREA 0.196500 ;
    PORT
      LAYER met2 ;
        RECT 495.970 0.000 496.250 4.000 ;
    END
  END key[80]
  PIN key[81]
    DIRECTION INPUT ;
    USE SIGNAL ;
    ANTENNAGATEAREA 0.196500 ;
    PORT
      LAYER met2 ;
        RECT 248.030 0.000 248.310 4.000 ;
    END
  END key[81]
  PIN key[82]
    DIRECTION INPUT ;
    USE SIGNAL ;
    ANTENNAGATEAREA 0.196500 ;
    PORT
      LAYER met3 ;
        RECT 0.000 98.640 4.000 99.240 ;
    END
  END key[82]
  PIN key[83]
    DIRECTION INPUT ;
    USE SIGNAL ;
    ANTENNAGATEAREA 0.196500 ;
    PORT
      LAYER met2 ;
        RECT 206.170 0.000 206.450 4.000 ;
    END
  END key[83]
  PIN key[84]
    DIRECTION INPUT ;
    USE SIGNAL ;
    ANTENNAGATEAREA 0.196500 ;
    PORT
      LAYER met2 ;
        RECT 331.750 0.000 332.030 4.000 ;
    END
  END key[84]
  PIN key[85]
    DIRECTION INPUT ;
    USE SIGNAL ;
    ANTENNAGATEAREA 0.213000 ;
    PORT
      LAYER met2 ;
        RECT 83.810 0.000 84.090 4.000 ;
    END
  END key[85]
  PIN key[86]
    DIRECTION INPUT ;
    USE SIGNAL ;
    ANTENNAGATEAREA 0.196500 ;
    PORT
      LAYER met2 ;
        RECT 209.390 0.000 209.670 4.000 ;
    END
  END key[86]
  PIN key[87]
    DIRECTION INPUT ;
    USE SIGNAL ;
    ANTENNAGATEAREA 0.196500 ;
    PORT
      LAYER met2 ;
        RECT 257.690 0.000 257.970 4.000 ;
    END
  END key[87]
  PIN key[88]
    DIRECTION INPUT ;
    USE SIGNAL ;
    ANTENNAGATEAREA 0.196500 ;
    PORT
      LAYER met2 ;
        RECT 483.090 0.000 483.370 4.000 ;
    END
  END key[88]
  PIN key[89]
    DIRECTION INPUT ;
    USE SIGNAL ;
    ANTENNAGATEAREA 0.159000 ;
    PORT
      LAYER met2 ;
        RECT 61.270 0.000 61.550 4.000 ;
    END
  END key[89]
  PIN key[8]
    DIRECTION INPUT ;
    USE SIGNAL ;
    ANTENNAGATEAREA 0.213000 ;
    PORT
      LAYER met2 ;
        RECT 99.910 0.000 100.190 4.000 ;
    END
  END key[8]
  PIN key[90]
    DIRECTION INPUT ;
    USE SIGNAL ;
    ANTENNAGATEAREA 0.196500 ;
    PORT
      LAYER met2 ;
        RECT 277.010 0.000 277.290 4.000 ;
    END
  END key[90]
  PIN key[91]
    DIRECTION INPUT ;
    USE SIGNAL ;
    ANTENNAGATEAREA 0.196500 ;
    PORT
      LAYER met2 ;
        RECT 444.450 0.000 444.730 4.000 ;
    END
  END key[91]
  PIN key[92]
    DIRECTION INPUT ;
    USE SIGNAL ;
    ANTENNAGATEAREA 0.196500 ;
    PORT
      LAYER met3 ;
        RECT 0.000 132.640 4.000 133.240 ;
    END
  END key[92]
  PIN key[93]
    DIRECTION INPUT ;
    USE SIGNAL ;
    ANTENNAGATEAREA 0.196500 ;
    PORT
      LAYER met3 ;
        RECT 0.000 176.840 4.000 177.440 ;
    END
  END key[93]
  PIN key[94]
    DIRECTION INPUT ;
    USE SIGNAL ;
    ANTENNAGATEAREA 0.196500 ;
    PORT
      LAYER met2 ;
        RECT 386.490 0.000 386.770 4.000 ;
    END
  END key[94]
  PIN key[95]
    DIRECTION INPUT ;
    USE SIGNAL ;
    ANTENNAGATEAREA 0.196500 ;
    PORT
      LAYER met2 ;
        RECT 438.010 0.000 438.290 4.000 ;
    END
  END key[95]
  PIN key[96]
    DIRECTION INPUT ;
    USE SIGNAL ;
    ANTENNAGATEAREA 0.196500 ;
    PORT
      LAYER met2 ;
        RECT 492.750 0.000 493.030 4.000 ;
    END
  END key[96]
  PIN key[97]
    DIRECTION INPUT ;
    USE SIGNAL ;
    ANTENNAGATEAREA 0.196500 ;
    PORT
      LAYER met3 ;
        RECT 0.000 105.440 4.000 106.040 ;
    END
  END key[97]
  PIN key[98]
    DIRECTION INPUT ;
    USE SIGNAL ;
    ANTENNAGATEAREA 0.196500 ;
    PORT
      LAYER met3 ;
        RECT 0.000 153.040 4.000 153.640 ;
    END
  END key[98]
  PIN key[99]
    DIRECTION INPUT ;
    USE SIGNAL ;
    ANTENNAGATEAREA 0.196500 ;
    PORT
      LAYER met3 ;
        RECT 0.000 142.840 4.000 143.440 ;
    END
  END key[99]
  PIN key[9]
    DIRECTION INPUT ;
    USE SIGNAL ;
    ANTENNAGATEAREA 0.196500 ;
    PORT
      LAYER met2 ;
        RECT 244.810 0.000 245.090 4.000 ;
    END
  END key[9]
  PIN nonce[0]
    DIRECTION INPUT ;
    USE SIGNAL ;
    ANTENNAGATEAREA 0.196500 ;
    PORT
      LAYER met3 ;
        RECT 646.000 306.040 650.000 306.640 ;
    END
  END nonce[0]
  PIN nonce[10]
    DIRECTION INPUT ;
    USE SIGNAL ;
    ANTENNAGATEAREA 0.196500 ;
    PORT
      LAYER met2 ;
        RECT 289.890 0.000 290.170 4.000 ;
    END
  END nonce[10]
  PIN nonce[11]
    DIRECTION INPUT ;
    USE SIGNAL ;
    ANTENNAGATEAREA 0.196500 ;
    PORT
      LAYER met3 ;
        RECT 0.000 282.240 4.000 282.840 ;
    END
  END nonce[11]
  PIN nonce[12]
    DIRECTION INPUT ;
    USE SIGNAL ;
    ANTENNAGATEAREA 0.196500 ;
    PORT
      LAYER met3 ;
        RECT 0.000 258.440 4.000 259.040 ;
    END
  END nonce[12]
  PIN nonce[13]
    DIRECTION INPUT ;
    USE SIGNAL ;
    ANTENNAGATEAREA 0.196500 ;
    PORT
      LAYER met3 ;
        RECT 0.000 251.640 4.000 252.240 ;
    END
  END nonce[13]
  PIN nonce[14]
    DIRECTION INPUT ;
    USE SIGNAL ;
    ANTENNAGATEAREA 0.196500 ;
    PORT
      LAYER met2 ;
        RECT 328.530 0.000 328.810 4.000 ;
    END
  END nonce[14]
  PIN nonce[15]
    DIRECTION INPUT ;
    USE SIGNAL ;
    ANTENNAGATEAREA 0.196500 ;
    PORT
      LAYER met2 ;
        RECT 460.550 0.000 460.830 4.000 ;
    END
  END nonce[15]
  PIN nonce[16]
    DIRECTION INPUT ;
    USE SIGNAL ;
    ANTENNAGATEAREA 0.196500 ;
    PORT
      LAYER met3 ;
        RECT 646.000 319.640 650.000 320.240 ;
    END
  END nonce[16]
  PIN nonce[17]
    DIRECTION INPUT ;
    USE SIGNAL ;
    ANTENNAGATEAREA 0.196500 ;
    PORT
      LAYER met2 ;
        RECT 351.070 0.000 351.350 4.000 ;
    END
  END nonce[17]
  PIN nonce[18]
    DIRECTION INPUT ;
    USE SIGNAL ;
    ANTENNAGATEAREA 0.196500 ;
    PORT
      LAYER met3 ;
        RECT 0.000 265.240 4.000 265.840 ;
    END
  END nonce[18]
  PIN nonce[19]
    DIRECTION INPUT ;
    USE SIGNAL ;
    ANTENNAGATEAREA 0.196500 ;
    PORT
      LAYER met3 ;
        RECT 0.000 224.440 4.000 225.040 ;
    END
  END nonce[19]
  PIN nonce[1]
    DIRECTION INPUT ;
    USE SIGNAL ;
    ANTENNAGATEAREA 0.196500 ;
    PORT
      LAYER met3 ;
        RECT 0.000 57.840 4.000 58.440 ;
    END
  END nonce[1]
  PIN nonce[20]
    DIRECTION INPUT ;
    USE SIGNAL ;
    ANTENNAGATEAREA 0.196500 ;
    PORT
      LAYER met3 ;
        RECT 0.000 268.640 4.000 269.240 ;
    END
  END nonce[20]
  PIN nonce[21]
    DIRECTION INPUT ;
    USE SIGNAL ;
    ANTENNAGATEAREA 0.196500 ;
    PORT
      LAYER met2 ;
        RECT 119.230 0.000 119.510 4.000 ;
    END
  END nonce[21]
  PIN nonce[22]
    DIRECTION INPUT ;
    USE SIGNAL ;
    ANTENNAGATEAREA 0.196500 ;
    PORT
      LAYER met3 ;
        RECT 0.000 231.240 4.000 231.840 ;
    END
  END nonce[22]
  PIN nonce[23]
    DIRECTION INPUT ;
    USE SIGNAL ;
    ANTENNAGATEAREA 0.196500 ;
    PORT
      LAYER met3 ;
        RECT 646.000 513.440 650.000 514.040 ;
    END
  END nonce[23]
  PIN nonce[24]
    DIRECTION INPUT ;
    USE SIGNAL ;
    ANTENNAGATEAREA 0.196500 ;
    PORT
      LAYER met3 ;
        RECT 646.000 282.240 650.000 282.840 ;
    END
  END nonce[24]
  PIN nonce[25]
    DIRECTION INPUT ;
    USE SIGNAL ;
    ANTENNAGATEAREA 0.196500 ;
    PORT
      LAYER met2 ;
        RECT 74.150 0.000 74.430 4.000 ;
    END
  END nonce[25]
  PIN nonce[26]
    DIRECTION INPUT ;
    USE SIGNAL ;
    ANTENNAGATEAREA 0.196500 ;
    PORT
      LAYER met3 ;
        RECT 0.000 255.040 4.000 255.640 ;
    END
  END nonce[26]
  PIN nonce[27]
    DIRECTION INPUT ;
    USE SIGNAL ;
    ANTENNAGATEAREA 0.196500 ;
    PORT
      LAYER met3 ;
        RECT 0.000 302.640 4.000 303.240 ;
    END
  END nonce[27]
  PIN nonce[28]
    DIRECTION INPUT ;
    USE SIGNAL ;
    ANTENNAGATEAREA 0.196500 ;
    PORT
      LAYER met3 ;
        RECT 0.000 292.440 4.000 293.040 ;
    END
  END nonce[28]
  PIN nonce[29]
    DIRECTION INPUT ;
    USE SIGNAL ;
    ANTENNAGATEAREA 0.196500 ;
    PORT
      LAYER met3 ;
        RECT 0.000 47.640 4.000 48.240 ;
    END
  END nonce[29]
  PIN nonce[2]
    DIRECTION INPUT ;
    USE SIGNAL ;
    ANTENNAGATEAREA 0.196500 ;
    PORT
      LAYER met3 ;
        RECT 0.000 275.440 4.000 276.040 ;
    END
  END nonce[2]
  PIN nonce[30]
    DIRECTION INPUT ;
    USE SIGNAL ;
    ANTENNAGATEAREA 0.196500 ;
    PORT
      LAYER met2 ;
        RECT 537.830 0.000 538.110 4.000 ;
    END
  END nonce[30]
  PIN nonce[31]
    DIRECTION INPUT ;
    USE SIGNAL ;
    ANTENNAGATEAREA 0.196500 ;
    PORT
      LAYER met3 ;
        RECT 646.000 0.040 650.000 0.640 ;
    END
  END nonce[31]
  PIN nonce[32]
    DIRECTION INPUT ;
    USE SIGNAL ;
    ANTENNAGATEAREA 0.196500 ;
    PORT
      LAYER met3 ;
        RECT 646.000 346.840 650.000 347.440 ;
    END
  END nonce[32]
  PIN nonce[33]
    DIRECTION INPUT ;
    USE SIGNAL ;
    ANTENNAGATEAREA 0.196500 ;
    PORT
      LAYER met3 ;
        RECT 0.000 210.840 4.000 211.440 ;
    END
  END nonce[33]
  PIN nonce[34]
    DIRECTION INPUT ;
    USE SIGNAL ;
    ANTENNAGATEAREA 0.196500 ;
    PORT
      LAYER met3 ;
        RECT 0.000 238.040 4.000 238.640 ;
    END
  END nonce[34]
  PIN nonce[35]
    DIRECTION INPUT ;
    USE SIGNAL ;
    ANTENNAGATEAREA 0.196500 ;
    PORT
      LAYER met3 ;
        RECT 0.000 234.640 4.000 235.240 ;
    END
  END nonce[35]
  PIN nonce[36]
    DIRECTION INPUT ;
    USE SIGNAL ;
    ANTENNAGATEAREA 0.196500 ;
    PORT
      LAYER met3 ;
        RECT 0.000 244.840 4.000 245.440 ;
    END
  END nonce[36]
  PIN nonce[37]
    DIRECTION INPUT ;
    USE SIGNAL ;
    ANTENNAGATEAREA 0.159000 ;
    PORT
      LAYER met3 ;
        RECT 0.000 204.040 4.000 204.640 ;
    END
  END nonce[37]
  PIN nonce[38]
    DIRECTION INPUT ;
    USE SIGNAL ;
    ANTENNAGATEAREA 0.213000 ;
    PORT
      LAYER met2 ;
        RECT 570.030 0.000 570.310 4.000 ;
    END
  END nonce[38]
  PIN nonce[39]
    DIRECTION INPUT ;
    USE SIGNAL ;
    ANTENNAGATEAREA 0.196500 ;
    PORT
      LAYER met2 ;
        RECT 489.530 0.000 489.810 4.000 ;
    END
  END nonce[39]
  PIN nonce[3]
    DIRECTION INPUT ;
    USE SIGNAL ;
    ANTENNAGATEAREA 0.196500 ;
    PORT
      LAYER met3 ;
        RECT 0.000 214.240 4.000 214.840 ;
    END
  END nonce[3]
  PIN nonce[40]
    DIRECTION INPUT ;
    USE SIGNAL ;
    ANTENNAGATEAREA 0.196500 ;
    PORT
      LAYER met3 ;
        RECT 646.000 299.240 650.000 299.840 ;
    END
  END nonce[40]
  PIN nonce[41]
    DIRECTION INPUT ;
    USE SIGNAL ;
    ANTENNAGATEAREA 0.196500 ;
    PORT
      LAYER met2 ;
        RECT 521.730 0.000 522.010 4.000 ;
    END
  END nonce[41]
  PIN nonce[42]
    DIRECTION INPUT ;
    USE SIGNAL ;
    ANTENNAGATEAREA 0.196500 ;
    PORT
      LAYER met2 ;
        RECT 293.110 0.000 293.390 4.000 ;
    END
  END nonce[42]
  PIN nonce[43]
    DIRECTION INPUT ;
    USE SIGNAL ;
    ANTENNAGATEAREA 0.196500 ;
    PORT
      LAYER met3 ;
        RECT 0.000 248.240 4.000 248.840 ;
    END
  END nonce[43]
  PIN nonce[44]
    DIRECTION INPUT ;
    USE SIGNAL ;
    ANTENNAGATEAREA 0.196500 ;
    PORT
      LAYER met3 ;
        RECT 0.000 217.640 4.000 218.240 ;
    END
  END nonce[44]
  PIN nonce[45]
    DIRECTION INPUT ;
    USE SIGNAL ;
    ANTENNAGATEAREA 0.126000 ;
    PORT
      LAYER met3 ;
        RECT 0.000 23.840 4.000 24.440 ;
    END
  END nonce[45]
  PIN nonce[46]
    DIRECTION INPUT ;
    USE SIGNAL ;
    ANTENNAGATEAREA 0.196500 ;
    PORT
      LAYER met2 ;
        RECT 334.970 0.000 335.250 4.000 ;
    END
  END nonce[46]
  PIN nonce[47]
    DIRECTION INPUT ;
    USE SIGNAL ;
    ANTENNAGATEAREA 0.196500 ;
    PORT
      LAYER met2 ;
        RECT 415.470 0.000 415.750 4.000 ;
    END
  END nonce[47]
  PIN nonce[48]
    DIRECTION INPUT ;
    USE SIGNAL ;
    ANTENNAGATEAREA 0.196500 ;
    PORT
      LAYER met3 ;
        RECT 646.000 343.440 650.000 344.040 ;
    END
  END nonce[48]
  PIN nonce[49]
    DIRECTION INPUT ;
    USE SIGNAL ;
    ANTENNAGATEAREA 0.196500 ;
    PORT
      LAYER met2 ;
        RECT 347.850 0.000 348.130 4.000 ;
    END
  END nonce[49]
  PIN nonce[4]
    DIRECTION INPUT ;
    USE SIGNAL ;
    ANTENNAGATEAREA 0.196500 ;
    PORT
      LAYER met3 ;
        RECT 0.000 180.240 4.000 180.840 ;
    END
  END nonce[4]
  PIN nonce[50]
    DIRECTION INPUT ;
    USE SIGNAL ;
    ANTENNAGATEAREA 0.196500 ;
    PORT
      LAYER met3 ;
        RECT 0.000 108.840 4.000 109.440 ;
    END
  END nonce[50]
  PIN nonce[51]
    DIRECTION INPUT ;
    USE SIGNAL ;
    ANTENNAGATEAREA 0.196500 ;
    PORT
      LAYER met3 ;
        RECT 0.000 146.240 4.000 146.840 ;
    END
  END nonce[51]
  PIN nonce[52]
    DIRECTION INPUT ;
    USE SIGNAL ;
    ANTENNAGATEAREA 0.196500 ;
    PORT
      LAYER met3 ;
        RECT 0.000 227.840 4.000 228.440 ;
    END
  END nonce[52]
  PIN nonce[53]
    DIRECTION INPUT ;
    USE SIGNAL ;
    ANTENNAGATEAREA 0.196500 ;
    PORT
      LAYER met2 ;
        RECT 103.130 0.000 103.410 4.000 ;
    END
  END nonce[53]
  PIN nonce[54]
    DIRECTION INPUT ;
    USE SIGNAL ;
    ANTENNAGATEAREA 0.196500 ;
    PORT
      LAYER met3 ;
        RECT 0.000 88.440 4.000 89.040 ;
    END
  END nonce[54]
  PIN nonce[55]
    DIRECTION INPUT ;
    USE SIGNAL ;
    ANTENNAGATEAREA 0.196500 ;
    PORT
      LAYER met3 ;
        RECT 646.000 329.840 650.000 330.440 ;
    END
  END nonce[55]
  PIN nonce[56]
    DIRECTION INPUT ;
    USE SIGNAL ;
    ANTENNAGATEAREA 0.196500 ;
    PORT
      LAYER met3 ;
        RECT 646.000 326.440 650.000 327.040 ;
    END
  END nonce[56]
  PIN nonce[57]
    DIRECTION INPUT ;
    USE SIGNAL ;
    ANTENNAGATEAREA 0.196500 ;
    PORT
      LAYER met2 ;
        RECT 70.930 0.000 71.210 4.000 ;
    END
  END nonce[57]
  PIN nonce[58]
    DIRECTION INPUT ;
    USE SIGNAL ;
    ANTENNAGATEAREA 0.213000 ;
    PORT
      LAYER met2 ;
        RECT 154.650 0.000 154.930 4.000 ;
    END
  END nonce[58]
  PIN nonce[59]
    DIRECTION INPUT ;
    USE SIGNAL ;
    ANTENNAGATEAREA 0.213000 ;
    PORT
      LAYER met2 ;
        RECT 93.470 0.000 93.750 4.000 ;
    END
  END nonce[59]
  PIN nonce[5]
    DIRECTION INPUT ;
    USE SIGNAL ;
    ANTENNAGATEAREA 0.196500 ;
    PORT
      LAYER met2 ;
        RECT 251.250 0.000 251.530 4.000 ;
    END
  END nonce[5]
  PIN nonce[60]
    DIRECTION INPUT ;
    USE SIGNAL ;
    ANTENNAGATEAREA 0.213000 ;
    PORT
      LAYER met2 ;
        RECT 96.690 0.000 96.970 4.000 ;
    END
  END nonce[60]
  PIN nonce[61]
    DIRECTION INPUT ;
    USE SIGNAL ;
    ANTENNAGATEAREA 0.196500 ;
    PORT
      LAYER met2 ;
        RECT 215.830 0.000 216.110 4.000 ;
    END
  END nonce[61]
  PIN nonce[62]
    DIRECTION INPUT ;
    USE SIGNAL ;
    ANTENNAGATEAREA 0.196500 ;
    PORT
      LAYER met2 ;
        RECT 405.810 0.000 406.090 4.000 ;
    END
  END nonce[62]
  PIN nonce[63]
    DIRECTION INPUT ;
    USE SIGNAL ;
    ANTENNAGATEAREA 0.196500 ;
    PORT
      LAYER met3 ;
        RECT 646.000 3.440 650.000 4.040 ;
    END
  END nonce[63]
  PIN nonce[64]
    DIRECTION INPUT ;
    USE SIGNAL ;
    ANTENNAGATEAREA 0.196500 ;
    PORT
      LAYER met3 ;
        RECT 646.000 323.040 650.000 323.640 ;
    END
  END nonce[64]
  PIN nonce[65]
    DIRECTION INPUT ;
    USE SIGNAL ;
    ANTENNAGATEAREA 0.196500 ;
    PORT
      LAYER met2 ;
        RECT 260.910 0.000 261.190 4.000 ;
    END
  END nonce[65]
  PIN nonce[66]
    DIRECTION INPUT ;
    USE SIGNAL ;
    ANTENNAGATEAREA 0.213000 ;
    PORT
      LAYER met2 ;
        RECT 186.850 0.000 187.130 4.000 ;
    END
  END nonce[66]
  PIN nonce[67]
    DIRECTION INPUT ;
    USE SIGNAL ;
    ANTENNAGATEAREA 0.213000 ;
    PORT
      LAYER met2 ;
        RECT 106.350 0.000 106.630 4.000 ;
    END
  END nonce[67]
  PIN nonce[68]
    DIRECTION INPUT ;
    USE SIGNAL ;
    ANTENNAGATEAREA 0.126000 ;
    PORT
      LAYER met2 ;
        RECT 173.970 0.000 174.250 4.000 ;
    END
  END nonce[68]
  PIN nonce[69]
    DIRECTION INPUT ;
    USE SIGNAL ;
    ANTENNAGATEAREA 0.196500 ;
    PORT
      LAYER met2 ;
        RECT 238.370 0.000 238.650 4.000 ;
    END
  END nonce[69]
  PIN nonce[6]
    DIRECTION INPUT ;
    USE SIGNAL ;
    ANTENNAGATEAREA 0.196500 ;
    PORT
      LAYER met2 ;
        RECT 367.170 0.000 367.450 4.000 ;
    END
  END nonce[6]
  PIN nonce[70]
    DIRECTION INPUT ;
    USE SIGNAL ;
    ANTENNAGATEAREA 0.213000 ;
    PORT
      LAYER met3 ;
        RECT 646.000 302.640 650.000 303.240 ;
    END
  END nonce[70]
  PIN nonce[71]
    DIRECTION INPUT ;
    USE SIGNAL ;
    ANTENNAGATEAREA 0.196500 ;
    PORT
      LAYER met3 ;
        RECT 646.000 258.440 650.000 259.040 ;
    END
  END nonce[71]
  PIN nonce[72]
    DIRECTION INPUT ;
    USE SIGNAL ;
    ANTENNAGATEAREA 0.196500 ;
    PORT
      LAYER met3 ;
        RECT 646.000 363.840 650.000 364.440 ;
    END
  END nonce[72]
  PIN nonce[73]
    DIRECTION INPUT ;
    USE SIGNAL ;
    ANTENNAGATEAREA 0.196500 ;
    PORT
      LAYER met2 ;
        RECT 360.730 0.000 361.010 4.000 ;
    END
  END nonce[73]
  PIN nonce[74]
    DIRECTION INPUT ;
    USE SIGNAL ;
    ANTENNAGATEAREA 0.196500 ;
    PORT
      LAYER met2 ;
        RECT 296.330 0.000 296.610 4.000 ;
    END
  END nonce[74]
  PIN nonce[75]
    DIRECTION INPUT ;
    USE SIGNAL ;
    ANTENNAGATEAREA 0.213000 ;
    PORT
      LAYER met2 ;
        RECT 151.430 0.000 151.710 4.000 ;
    END
  END nonce[75]
  PIN nonce[76]
    DIRECTION INPUT ;
    USE SIGNAL ;
    ANTENNAGATEAREA 0.213000 ;
    PORT
      LAYER met2 ;
        RECT 161.090 0.000 161.370 4.000 ;
    END
  END nonce[76]
  PIN nonce[77]
    DIRECTION INPUT ;
    USE SIGNAL ;
    ANTENNAGATEAREA 0.196500 ;
    PORT
      LAYER met2 ;
        RECT 193.290 0.000 193.570 4.000 ;
    END
  END nonce[77]
  PIN nonce[78]
    DIRECTION INPUT ;
    USE SIGNAL ;
    ANTENNAGATEAREA 0.196500 ;
    PORT
      LAYER met2 ;
        RECT 309.210 0.000 309.490 4.000 ;
    END
  END nonce[78]
  PIN nonce[79]
    DIRECTION INPUT ;
    USE SIGNAL ;
    ANTENNAGATEAREA 0.196500 ;
    PORT
      LAYER met2 ;
        RECT 515.290 0.000 515.570 4.000 ;
    END
  END nonce[79]
  PIN nonce[7]
    DIRECTION INPUT ;
    USE SIGNAL ;
    ANTENNAGATEAREA 0.196500 ;
    PORT
      LAYER met2 ;
        RECT 441.230 0.000 441.510 4.000 ;
    END
  END nonce[7]
  PIN nonce[80]
    DIRECTION INPUT ;
    USE SIGNAL ;
    ANTENNAGATEAREA 0.196500 ;
    PORT
      LAYER met3 ;
        RECT 646.000 333.240 650.000 333.840 ;
    END
  END nonce[80]
  PIN nonce[81]
    DIRECTION INPUT ;
    USE SIGNAL ;
    ANTENNAGATEAREA 0.196500 ;
    PORT
      LAYER met2 ;
        RECT 338.190 0.000 338.470 4.000 ;
    END
  END nonce[81]
  PIN nonce[82]
    DIRECTION INPUT ;
    USE SIGNAL ;
    ANTENNAGATEAREA 0.213000 ;
    PORT
      LAYER met2 ;
        RECT 112.790 0.000 113.070 4.000 ;
    END
  END nonce[82]
  PIN nonce[83]
    DIRECTION INPUT ;
    USE SIGNAL ;
    ANTENNAGATEAREA 0.126000 ;
    PORT
      LAYER met2 ;
        RECT 138.550 0.000 138.830 4.000 ;
    END
  END nonce[83]
  PIN nonce[84]
    DIRECTION INPUT ;
    USE SIGNAL ;
    ANTENNAGATEAREA 0.213000 ;
    PORT
      LAYER met2 ;
        RECT 132.110 0.000 132.390 4.000 ;
    END
  END nonce[84]
  PIN nonce[85]
    DIRECTION INPUT ;
    USE SIGNAL ;
    ANTENNAGATEAREA 0.196500 ;
    PORT
      LAYER met2 ;
        RECT 270.570 0.000 270.850 4.000 ;
    END
  END nonce[85]
  PIN nonce[86]
    DIRECTION INPUT ;
    USE SIGNAL ;
    ANTENNAGATEAREA 0.196500 ;
    PORT
      LAYER met2 ;
        RECT 87.030 0.000 87.310 4.000 ;
    END
  END nonce[86]
  PIN nonce[87]
    DIRECTION INPUT ;
    USE SIGNAL ;
    ANTENNAGATEAREA 0.196500 ;
    PORT
      LAYER met3 ;
        RECT 646.000 418.240 650.000 418.840 ;
    END
  END nonce[87]
  PIN nonce[88]
    DIRECTION INPUT ;
    USE SIGNAL ;
    ANTENNAGATEAREA 0.213000 ;
    PORT
      LAYER met3 ;
        RECT 646.000 622.240 650.000 622.840 ;
    END
  END nonce[88]
  PIN nonce[89]
    DIRECTION INPUT ;
    USE SIGNAL ;
    ANTENNAGATEAREA 0.196500 ;
    PORT
      LAYER met2 ;
        RECT 312.430 0.000 312.710 4.000 ;
    END
  END nonce[89]
  PIN nonce[8]
    DIRECTION INPUT ;
    USE SIGNAL ;
    ANTENNAGATEAREA 0.196500 ;
    PORT
      LAYER met3 ;
        RECT 646.000 275.440 650.000 276.040 ;
    END
  END nonce[8]
  PIN nonce[90]
    DIRECTION INPUT ;
    USE SIGNAL ;
    ANTENNAGATEAREA 0.213000 ;
    PORT
      LAYER met2 ;
        RECT 235.150 0.000 235.430 4.000 ;
    END
  END nonce[90]
  PIN nonce[91]
    DIRECTION INPUT ;
    USE SIGNAL ;
    ANTENNAGATEAREA 0.213000 ;
    PORT
      LAYER met2 ;
        RECT 109.570 0.000 109.850 4.000 ;
    END
  END nonce[91]
  PIN nonce[92]
    DIRECTION INPUT ;
    USE SIGNAL ;
    ANTENNAGATEAREA 0.213000 ;
    PORT
      LAYER met2 ;
        RECT 116.010 0.000 116.290 4.000 ;
    END
  END nonce[92]
  PIN nonce[93]
    DIRECTION INPUT ;
    USE SIGNAL ;
    ANTENNAGATEAREA 0.196500 ;
    PORT
      LAYER met2 ;
        RECT 212.610 0.000 212.890 4.000 ;
    END
  END nonce[93]
  PIN nonce[94]
    DIRECTION INPUT ;
    USE SIGNAL ;
    ANTENNAGATEAREA 0.196500 ;
    PORT
      LAYER met3 ;
        RECT 646.000 285.640 650.000 286.240 ;
    END
  END nonce[94]
  PIN nonce[95]
    DIRECTION INPUT ;
    USE SIGNAL ;
    ANTENNAGATEAREA 0.196500 ;
    PORT
      LAYER met3 ;
        RECT 646.000 17.040 650.000 17.640 ;
    END
  END nonce[95]
  PIN nonce[9]
    DIRECTION INPUT ;
    USE SIGNAL ;
    ANTENNAGATEAREA 0.196500 ;
    PORT
      LAYER met2 ;
        RECT 344.630 0.000 344.910 4.000 ;
    END
  END nonce[9]
  PIN rst_n
    DIRECTION INPUT ;
    USE SIGNAL ;
    ANTENNAGATEAREA 0.247500 ;
    PORT
      LAYER met3 ;
        RECT 646.000 574.640 650.000 575.240 ;
    END
  END rst_n
  PIN sel_type[0]
    DIRECTION INPUT ;
    USE SIGNAL ;
    ANTENNAGATEAREA 0.196500 ;
    PORT
      LAYER met3 ;
        RECT 646.000 367.240 650.000 367.840 ;
    END
  END sel_type[0]
  PIN sel_type[1]
    DIRECTION INPUT ;
    USE SIGNAL ;
    ANTENNAGATEAREA 0.196500 ;
    PORT
      LAYER met3 ;
        RECT 646.000 340.040 650.000 340.640 ;
    END
  END sel_type[1]
  PIN sel_type[2]
    DIRECTION INPUT ;
    USE SIGNAL ;
    ANTENNAGATEAREA 0.196500 ;
    PORT
      LAYER met3 ;
        RECT 646.000 479.440 650.000 480.040 ;
    END
  END sel_type[2]
  PIN tag[0]
    DIRECTION OUTPUT ;
    USE SIGNAL ;
    ANTENNADIFFAREA 0.445500 ;
    PORT
      LAYER met3 ;
        RECT 646.000 578.040 650.000 578.640 ;
    END
  END tag[0]
  PIN tag[10]
    DIRECTION OUTPUT ;
    USE SIGNAL ;
    ANTENNADIFFAREA 0.445500 ;
    PORT
      LAYER met3 ;
        RECT 646.000 68.040 650.000 68.640 ;
    END
  END tag[10]
  PIN tag[11]
    DIRECTION OUTPUT ;
    USE SIGNAL ;
    ANTENNADIFFAREA 0.445500 ;
    PORT
      LAYER met3 ;
        RECT 646.000 37.440 650.000 38.040 ;
    END
  END tag[11]
  PIN tag[12]
    DIRECTION OUTPUT ;
    USE SIGNAL ;
    ANTENNADIFFAREA 0.445500 ;
    PORT
      LAYER met2 ;
        RECT 505.630 0.000 505.910 4.000 ;
    END
  END tag[12]
  PIN tag[13]
    DIRECTION OUTPUT ;
    USE SIGNAL ;
    ANTENNADIFFAREA 0.445500 ;
    PORT
      LAYER met2 ;
        RECT 647.310 0.000 647.590 4.000 ;
    END
  END tag[13]
  PIN tag[14]
    DIRECTION OUTPUT ;
    USE SIGNAL ;
    ANTENNADIFFAREA 0.445500 ;
    PORT
      LAYER met2 ;
        RECT 644.090 0.000 644.370 4.000 ;
    END
  END tag[14]
  PIN tag[15]
    DIRECTION OUTPUT ;
    USE SIGNAL ;
    ANTENNADIFFAREA 0.445500 ;
    PORT
      LAYER met2 ;
        RECT 473.430 0.000 473.710 4.000 ;
    END
  END tag[15]
  PIN tag[16]
    DIRECTION OUTPUT ;
    USE SIGNAL ;
    ANTENNADIFFAREA 0.445500 ;
    PORT
      LAYER met2 ;
        RECT 518.510 0.000 518.790 4.000 ;
    END
  END tag[16]
  PIN tag[17]
    DIRECTION OUTPUT ;
    USE SIGNAL ;
    ANTENNADIFFAREA 0.445500 ;
    PORT
      LAYER met3 ;
        RECT 646.000 88.440 650.000 89.040 ;
    END
  END tag[17]
  PIN tag[18]
    DIRECTION OUTPUT ;
    USE SIGNAL ;
    ANTENNADIFFAREA 0.445500 ;
    PORT
      LAYER met3 ;
        RECT 646.000 30.640 650.000 31.240 ;
    END
  END tag[18]
  PIN tag[19]
    DIRECTION OUTPUT ;
    USE SIGNAL ;
    ANTENNADIFFAREA 0.445500 ;
    PORT
      LAYER met3 ;
        RECT 646.000 142.840 650.000 143.440 ;
    END
  END tag[19]
  PIN tag[1]
    DIRECTION OUTPUT ;
    USE SIGNAL ;
    ANTENNADIFFAREA 0.445500 ;
    PORT
      LAYER met2 ;
        RECT 434.790 0.000 435.070 4.000 ;
    END
  END tag[1]
  PIN tag[20]
    DIRECTION OUTPUT ;
    USE SIGNAL ;
    ANTENNADIFFAREA 0.445500 ;
    PORT
      LAYER met3 ;
        RECT 646.000 125.840 650.000 126.440 ;
    END
  END tag[20]
  PIN tag[21]
    DIRECTION OUTPUT ;
    USE SIGNAL ;
    ANTENNADIFFAREA 0.445500 ;
    PORT
      LAYER met3 ;
        RECT 646.000 122.440 650.000 123.040 ;
    END
  END tag[21]
  PIN tag[22]
    DIRECTION OUTPUT ;
    USE SIGNAL ;
    ANTENNADIFFAREA 0.445500 ;
    PORT
      LAYER met3 ;
        RECT 646.000 102.040 650.000 102.640 ;
    END
  END tag[22]
  PIN tag[23]
    DIRECTION OUTPUT ;
    USE SIGNAL ;
    ANTENNADIFFAREA 0.445500 ;
    PORT
      LAYER met3 ;
        RECT 646.000 394.440 650.000 395.040 ;
    END
  END tag[23]
  PIN tag[24]
    DIRECTION OUTPUT ;
    USE SIGNAL ;
    ANTENNADIFFAREA 0.445500 ;
    PORT
      LAYER met2 ;
        RECT 592.570 0.000 592.850 4.000 ;
    END
  END tag[24]
  PIN tag[25]
    DIRECTION OUTPUT ;
    USE SIGNAL ;
    ANTENNADIFFAREA 0.445500 ;
    PORT
      LAYER met3 ;
        RECT 646.000 197.240 650.000 197.840 ;
    END
  END tag[25]
  PIN tag[26]
    DIRECTION OUTPUT ;
    USE SIGNAL ;
    ANTENNADIFFAREA 0.445500 ;
    PORT
      LAYER met2 ;
        RECT 544.270 0.000 544.550 4.000 ;
    END
  END tag[26]
  PIN tag[27]
    DIRECTION OUTPUT ;
    USE SIGNAL ;
    ANTENNADIFFAREA 0.445500 ;
    PORT
      LAYER met2 ;
        RECT 566.810 0.000 567.090 4.000 ;
    END
  END tag[27]
  PIN tag[28]
    DIRECTION OUTPUT ;
    USE SIGNAL ;
    ANTENNADIFFAREA 0.445500 ;
    PORT
      LAYER met3 ;
        RECT 646.000 561.040 650.000 561.640 ;
    END
  END tag[28]
  PIN tag[29]
    DIRECTION OUTPUT ;
    USE SIGNAL ;
    ANTENNADIFFAREA 0.445500 ;
    PORT
      LAYER met3 ;
        RECT 646.000 292.440 650.000 293.040 ;
    END
  END tag[29]
  PIN tag[2]
    DIRECTION OUTPUT ;
    USE SIGNAL ;
    ANTENNADIFFAREA 0.445500 ;
    PORT
      LAYER met3 ;
        RECT 646.000 44.240 650.000 44.840 ;
    END
  END tag[2]
  PIN tag[30]
    DIRECTION OUTPUT ;
    USE SIGNAL ;
    ANTENNADIFFAREA 0.445500 ;
    PORT
      LAYER met3 ;
        RECT 646.000 370.640 650.000 371.240 ;
    END
  END tag[30]
  PIN tag[31]
    DIRECTION OUTPUT ;
    USE SIGNAL ;
    ANTENNADIFFAREA 0.445500 ;
    PORT
      LAYER met3 ;
        RECT 646.000 496.440 650.000 497.040 ;
    END
  END tag[31]
  PIN tag[32]
    DIRECTION OUTPUT ;
    USE SIGNAL ;
    ANTENNADIFFAREA 0.445500 ;
    PORT
      LAYER met2 ;
        RECT 524.950 0.000 525.230 4.000 ;
    END
  END tag[32]
  PIN tag[33]
    DIRECTION OUTPUT ;
    USE SIGNAL ;
    ANTENNADIFFAREA 0.445500 ;
    PORT
      LAYER met3 ;
        RECT 646.000 387.640 650.000 388.240 ;
    END
  END tag[33]
  PIN tag[34]
    DIRECTION OUTPUT ;
    USE SIGNAL ;
    ANTENNADIFFAREA 0.445500 ;
    PORT
      LAYER met3 ;
        RECT 646.000 10.240 650.000 10.840 ;
    END
  END tag[34]
  PIN tag[35]
    DIRECTION OUTPUT ;
    USE SIGNAL ;
    ANTENNADIFFAREA 0.445500 ;
    PORT
      LAYER met3 ;
        RECT 646.000 595.040 650.000 595.640 ;
    END
  END tag[35]
  PIN tag[36]
    DIRECTION OUTPUT ;
    USE SIGNAL ;
    ANTENNADIFFAREA 0.445500 ;
    PORT
      LAYER met3 ;
        RECT 646.000 265.240 650.000 265.840 ;
    END
  END tag[36]
  PIN tag[37]
    DIRECTION OUTPUT ;
    USE SIGNAL ;
    ANTENNADIFFAREA 0.445500 ;
    PORT
      LAYER met3 ;
        RECT 646.000 180.240 650.000 180.840 ;
    END
  END tag[37]
  PIN tag[38]
    DIRECTION OUTPUT ;
    USE SIGNAL ;
    ANTENNADIFFAREA 0.445500 ;
    PORT
      LAYER met3 ;
        RECT 646.000 564.440 650.000 565.040 ;
    END
  END tag[38]
  PIN tag[39]
    DIRECTION OUTPUT ;
    USE SIGNAL ;
    ANTENNADIFFAREA 0.445500 ;
    PORT
      LAYER met3 ;
        RECT 646.000 27.240 650.000 27.840 ;
    END
  END tag[39]
  PIN tag[3]
    DIRECTION OUTPUT ;
    USE SIGNAL ;
    ANTENNADIFFAREA 0.445500 ;
    PORT
      LAYER met3 ;
        RECT 646.000 170.040 650.000 170.640 ;
    END
  END tag[3]
  PIN tag[40]
    DIRECTION OUTPUT ;
    USE SIGNAL ;
    ANTENNADIFFAREA 0.445500 ;
    PORT
      LAYER met3 ;
        RECT 646.000 95.240 650.000 95.840 ;
    END
  END tag[40]
  PIN tag[41]
    DIRECTION OUTPUT ;
    USE SIGNAL ;
    ANTENNADIFFAREA 0.445500 ;
    PORT
      LAYER met2 ;
        RECT 476.650 0.000 476.930 4.000 ;
    END
  END tag[41]
  PIN tag[42]
    DIRECTION OUTPUT ;
    USE SIGNAL ;
    ANTENNADIFFAREA 0.445500 ;
    PORT
      LAYER met2 ;
        RECT 534.610 0.000 534.890 4.000 ;
    END
  END tag[42]
  PIN tag[43]
    DIRECTION OUTPUT ;
    USE SIGNAL ;
    ANTENNADIFFAREA 0.445500 ;
    PORT
      LAYER met3 ;
        RECT 646.000 40.840 650.000 41.440 ;
    END
  END tag[43]
  PIN tag[44]
    DIRECTION OUTPUT ;
    USE SIGNAL ;
    ANTENNADIFFAREA 0.445500 ;
    PORT
      LAYER met2 ;
        RECT 528.170 0.000 528.450 4.000 ;
    END
  END tag[44]
  PIN tag[45]
    DIRECTION OUTPUT ;
    USE SIGNAL ;
    ANTENNADIFFAREA 0.445500 ;
    PORT
      LAYER met2 ;
        RECT 508.850 0.000 509.130 4.000 ;
    END
  END tag[45]
  PIN tag[46]
    DIRECTION OUTPUT ;
    USE SIGNAL ;
    ANTENNADIFFAREA 0.445500 ;
    PORT
      LAYER met3 ;
        RECT 646.000 85.040 650.000 85.640 ;
    END
  END tag[46]
  PIN tag[47]
    DIRECTION OUTPUT ;
    USE SIGNAL ;
    ANTENNADIFFAREA 0.445500 ;
    PORT
      LAYER met3 ;
        RECT 646.000 61.240 650.000 61.840 ;
    END
  END tag[47]
  PIN tag[48]
    DIRECTION OUTPUT ;
    USE SIGNAL ;
    ANTENNADIFFAREA 0.445500 ;
    PORT
      LAYER met3 ;
        RECT 646.000 54.440 650.000 55.040 ;
    END
  END tag[48]
  PIN tag[49]
    DIRECTION OUTPUT ;
    USE SIGNAL ;
    ANTENNADIFFAREA 0.445500 ;
    PORT
      LAYER met3 ;
        RECT 646.000 64.640 650.000 65.240 ;
    END
  END tag[49]
  PIN tag[4]
    DIRECTION OUTPUT ;
    USE SIGNAL ;
    ANTENNADIFFAREA 0.445500 ;
    PORT
      LAYER met3 ;
        RECT 646.000 251.640 650.000 252.240 ;
    END
  END tag[4]
  PIN tag[50]
    DIRECTION OUTPUT ;
    USE SIGNAL ;
    ANTENNADIFFAREA 0.445500 ;
    PORT
      LAYER met2 ;
        RECT 579.690 0.000 579.970 4.000 ;
    END
  END tag[50]
  PIN tag[51]
    DIRECTION OUTPUT ;
    USE SIGNAL ;
    ANTENNADIFFAREA 0.445500 ;
    PORT
      LAYER met3 ;
        RECT 646.000 190.440 650.000 191.040 ;
    END
  END tag[51]
  PIN tag[52]
    DIRECTION OUTPUT ;
    USE SIGNAL ;
    ANTENNADIFFAREA 0.445500 ;
    PORT
      LAYER met3 ;
        RECT 646.000 6.840 650.000 7.440 ;
    END
  END tag[52]
  PIN tag[53]
    DIRECTION OUTPUT ;
    USE SIGNAL ;
    ANTENNADIFFAREA 0.445500 ;
    PORT
      LAYER met3 ;
        RECT 646.000 278.840 650.000 279.440 ;
    END
  END tag[53]
  PIN tag[54]
    DIRECTION OUTPUT ;
    USE SIGNAL ;
    ANTENNADIFFAREA 0.445500 ;
    PORT
      LAYER met3 ;
        RECT 646.000 268.640 650.000 269.240 ;
    END
  END tag[54]
  PIN tag[55]
    DIRECTION OUTPUT ;
    USE SIGNAL ;
    ANTENNADIFFAREA 0.445500 ;
    PORT
      LAYER met3 ;
        RECT 646.000 183.640 650.000 184.240 ;
    END
  END tag[55]
  PIN tag[56]
    DIRECTION OUTPUT ;
    USE SIGNAL ;
    ANTENNADIFFAREA 0.445500 ;
    PORT
      LAYER met3 ;
        RECT 646.000 231.240 650.000 231.840 ;
    END
  END tag[56]
  PIN tag[57]
    DIRECTION OUTPUT ;
    USE SIGNAL ;
    ANTENNADIFFAREA 0.445500 ;
    PORT
      LAYER met3 ;
        RECT 646.000 234.640 650.000 235.240 ;
    END
  END tag[57]
  PIN tag[58]
    DIRECTION OUTPUT ;
    USE SIGNAL ;
    ANTENNADIFFAREA 0.445500 ;
    PORT
      LAYER met3 ;
        RECT 646.000 176.840 650.000 177.440 ;
    END
  END tag[58]
  PIN tag[59]
    DIRECTION OUTPUT ;
    USE SIGNAL ;
    ANTENNADIFFAREA 0.445500 ;
    PORT
      LAYER met3 ;
        RECT 646.000 336.640 650.000 337.240 ;
    END
  END tag[59]
  PIN tag[5]
    DIRECTION OUTPUT ;
    USE SIGNAL ;
    ANTENNADIFFAREA 0.445500 ;
    PORT
      LAYER met3 ;
        RECT 646.000 129.240 650.000 129.840 ;
    END
  END tag[5]
  PIN tag[60]
    DIRECTION OUTPUT ;
    USE SIGNAL ;
    ANTENNADIFFAREA 0.445500 ;
    PORT
      LAYER met3 ;
        RECT 646.000 309.440 650.000 310.040 ;
    END
  END tag[60]
  PIN tag[61]
    DIRECTION OUTPUT ;
    USE SIGNAL ;
    ANTENNADIFFAREA 0.445500 ;
    PORT
      LAYER met3 ;
        RECT 646.000 639.240 650.000 639.840 ;
    END
  END tag[61]
  PIN tag[62]
    DIRECTION OUTPUT ;
    USE SIGNAL ;
    ANTENNADIFFAREA 0.445500 ;
    PORT
      LAYER met3 ;
        RECT 646.000 91.840 650.000 92.440 ;
    END
  END tag[62]
  PIN tag[63]
    DIRECTION OUTPUT ;
    USE SIGNAL ;
    ANTENNADIFFAREA 0.445500 ;
    PORT
      LAYER met3 ;
        RECT 646.000 71.440 650.000 72.040 ;
    END
  END tag[63]
  PIN tag[6]
    DIRECTION OUTPUT ;
    USE SIGNAL ;
    ANTENNADIFFAREA 0.445500 ;
    PORT
      LAYER met3 ;
        RECT 646.000 618.840 650.000 619.440 ;
    END
  END tag[6]
  PIN tag[7]
    DIRECTION OUTPUT ;
    USE SIGNAL ;
    ANTENNADIFFAREA 0.445500 ;
    PORT
      LAYER met2 ;
        RECT 457.330 0.000 457.610 4.000 ;
    END
  END tag[7]
  PIN tag[8]
    DIRECTION OUTPUT ;
    USE SIGNAL ;
    ANTENNADIFFAREA 0.445500 ;
    PORT
      LAYER met3 ;
        RECT 646.000 210.840 650.000 211.440 ;
    END
  END tag[8]
  PIN tag[9]
    DIRECTION OUTPUT ;
    USE SIGNAL ;
    ANTENNADIFFAREA 0.445500 ;
    PORT
      LAYER met2 ;
        RECT 553.930 0.000 554.210 4.000 ;
    END
  END tag[9]
  PIN tag_in[0]
    DIRECTION INPUT ;
    USE SIGNAL ;
    ANTENNAGATEAREA 0.196500 ;
    PORT
      LAYER met2 ;
        RECT 547.490 0.000 547.770 4.000 ;
    END
  END tag_in[0]
  PIN tag_in[10]
    DIRECTION INPUT ;
    USE SIGNAL ;
    ANTENNAGATEAREA 0.196500 ;
    PORT
      LAYER met3 ;
        RECT 646.000 166.640 650.000 167.240 ;
    END
  END tag_in[10]
  PIN tag_in[11]
    DIRECTION INPUT ;
    USE SIGNAL ;
    ANTENNAGATEAREA 0.196500 ;
    PORT
      LAYER met3 ;
        RECT 646.000 227.840 650.000 228.440 ;
    END
  END tag_in[11]
  PIN tag_in[12]
    DIRECTION INPUT ;
    USE SIGNAL ;
    ANTENNAGATEAREA 0.196500 ;
    PORT
      LAYER met2 ;
        RECT 499.190 0.000 499.470 4.000 ;
    END
  END tag_in[12]
  PIN tag_in[13]
    DIRECTION INPUT ;
    USE SIGNAL ;
    ANTENNAGATEAREA 0.196500 ;
    PORT
      LAYER met3 ;
        RECT 646.000 136.040 650.000 136.640 ;
    END
  END tag_in[13]
  PIN tag_in[14]
    DIRECTION INPUT ;
    USE SIGNAL ;
    ANTENNAGATEAREA 0.196500 ;
    PORT
      LAYER met2 ;
        RECT 502.410 0.000 502.690 4.000 ;
    END
  END tag_in[14]
  PIN tag_in[15]
    DIRECTION INPUT ;
    USE SIGNAL ;
    ANTENNAGATEAREA 0.196500 ;
    PORT
      LAYER met3 ;
        RECT 646.000 214.240 650.000 214.840 ;
    END
  END tag_in[15]
  PIN tag_in[16]
    DIRECTION INPUT ;
    USE SIGNAL ;
    ANTENNAGATEAREA 0.196500 ;
    PORT
      LAYER met3 ;
        RECT 646.000 384.240 650.000 384.840 ;
    END
  END tag_in[16]
  PIN tag_in[17]
    DIRECTION INPUT ;
    USE SIGNAL ;
    ANTENNAGATEAREA 0.196500 ;
    PORT
      LAYER met3 ;
        RECT 646.000 51.040 650.000 51.640 ;
    END
  END tag_in[17]
  PIN tag_in[18]
    DIRECTION INPUT ;
    USE SIGNAL ;
    ANTENNAGATEAREA 0.196500 ;
    PORT
      LAYER met3 ;
        RECT 646.000 149.640 650.000 150.240 ;
    END
  END tag_in[18]
  PIN tag_in[19]
    DIRECTION INPUT ;
    USE SIGNAL ;
    ANTENNAGATEAREA 0.196500 ;
    PORT
      LAYER met3 ;
        RECT 646.000 153.040 650.000 153.640 ;
    END
  END tag_in[19]
  PIN tag_in[1]
    DIRECTION INPUT ;
    USE SIGNAL ;
    ANTENNAGATEAREA 0.196500 ;
    PORT
      LAYER met2 ;
        RECT 589.350 0.000 589.630 4.000 ;
    END
  END tag_in[1]
  PIN tag_in[20]
    DIRECTION INPUT ;
    USE SIGNAL ;
    ANTENNAGATEAREA 0.196500 ;
    PORT
      LAYER met3 ;
        RECT 646.000 139.440 650.000 140.040 ;
    END
  END tag_in[20]
  PIN tag_in[21]
    DIRECTION INPUT ;
    USE SIGNAL ;
    ANTENNAGATEAREA 0.196500 ;
    PORT
      LAYER met3 ;
        RECT 646.000 146.240 650.000 146.840 ;
    END
  END tag_in[21]
  PIN tag_in[22]
    DIRECTION INPUT ;
    USE SIGNAL ;
    ANTENNAGATEAREA 0.196500 ;
    PORT
      LAYER met3 ;
        RECT 646.000 200.640 650.000 201.240 ;
    END
  END tag_in[22]
  PIN tag_in[23]
    DIRECTION INPUT ;
    USE SIGNAL ;
    ANTENNAGATEAREA 0.196500 ;
    PORT
      LAYER met3 ;
        RECT 646.000 533.840 650.000 534.440 ;
    END
  END tag_in[23]
  PIN tag_in[24]
    DIRECTION INPUT ;
    USE SIGNAL ;
    ANTENNAGATEAREA 0.196500 ;
    PORT
      LAYER met2 ;
        RECT 466.990 0.000 467.270 4.000 ;
    END
  END tag_in[24]
  PIN tag_in[25]
    DIRECTION INPUT ;
    USE SIGNAL ;
    ANTENNAGATEAREA 0.196500 ;
    PORT
      LAYER met3 ;
        RECT 646.000 115.640 650.000 116.240 ;
    END
  END tag_in[25]
  PIN tag_in[26]
    DIRECTION INPUT ;
    USE SIGNAL ;
    ANTENNAGATEAREA 0.196500 ;
    PORT
      LAYER met3 ;
        RECT 646.000 98.640 650.000 99.240 ;
    END
  END tag_in[26]
  PIN tag_in[27]
    DIRECTION INPUT ;
    USE SIGNAL ;
    ANTENNAGATEAREA 0.196500 ;
    PORT
      LAYER met3 ;
        RECT 646.000 316.240 650.000 316.840 ;
    END
  END tag_in[27]
  PIN tag_in[28]
    DIRECTION INPUT ;
    USE SIGNAL ;
    ANTENNAGATEAREA 0.196500 ;
    PORT
      LAYER met3 ;
        RECT 646.000 238.040 650.000 238.640 ;
    END
  END tag_in[28]
  PIN tag_in[29]
    DIRECTION INPUT ;
    USE SIGNAL ;
    ANTENNAGATEAREA 0.196500 ;
    PORT
      LAYER met3 ;
        RECT 646.000 217.640 650.000 218.240 ;
    END
  END tag_in[29]
  PIN tag_in[2]
    DIRECTION INPUT ;
    USE SIGNAL ;
    ANTENNAGATEAREA 0.196500 ;
    PORT
      LAYER met3 ;
        RECT 646.000 78.240 650.000 78.840 ;
    END
  END tag_in[2]
  PIN tag_in[30]
    DIRECTION INPUT ;
    USE SIGNAL ;
    ANTENNAGATEAREA 0.196500 ;
    PORT
      LAYER met3 ;
        RECT 646.000 187.040 650.000 187.640 ;
    END
  END tag_in[30]
  PIN tag_in[31]
    DIRECTION INPUT ;
    USE SIGNAL ;
    ANTENNAGATEAREA 0.196500 ;
    PORT
      LAYER met3 ;
        RECT 646.000 57.840 650.000 58.440 ;
    END
  END tag_in[31]
  PIN tag_in[32]
    DIRECTION INPUT ;
    USE SIGNAL ;
    ANTENNAGATEAREA 0.196500 ;
    PORT
      LAYER met3 ;
        RECT 646.000 34.040 650.000 34.640 ;
    END
  END tag_in[32]
  PIN tag_in[33]
    DIRECTION INPUT ;
    USE SIGNAL ;
    ANTENNAGATEAREA 0.213000 ;
    PORT
      LAYER met3 ;
        RECT 646.000 13.640 650.000 14.240 ;
    END
  END tag_in[33]
  PIN tag_in[34]
    DIRECTION INPUT ;
    USE SIGNAL ;
    ANTENNAGATEAREA 0.196500 ;
    PORT
      LAYER met3 ;
        RECT 646.000 47.640 650.000 48.240 ;
    END
  END tag_in[34]
  PIN tag_in[35]
    DIRECTION INPUT ;
    USE SIGNAL ;
    ANTENNAGATEAREA 0.196500 ;
    PORT
      LAYER met3 ;
        RECT 646.000 261.840 650.000 262.440 ;
    END
  END tag_in[35]
  PIN tag_in[36]
    DIRECTION INPUT ;
    USE SIGNAL ;
    ANTENNAGATEAREA 0.196500 ;
    PORT
      LAYER met3 ;
        RECT 646.000 81.640 650.000 82.240 ;
    END
  END tag_in[36]
  PIN tag_in[37]
    DIRECTION INPUT ;
    USE SIGNAL ;
    ANTENNAGATEAREA 0.196500 ;
    PORT
      LAYER met3 ;
        RECT 646.000 204.040 650.000 204.640 ;
    END
  END tag_in[37]
  PIN tag_in[38]
    DIRECTION INPUT ;
    USE SIGNAL ;
    ANTENNAGATEAREA 0.196500 ;
    PORT
      LAYER met3 ;
        RECT 646.000 472.640 650.000 473.240 ;
    END
  END tag_in[38]
  PIN tag_in[39]
    DIRECTION INPUT ;
    USE SIGNAL ;
    ANTENNAGATEAREA 0.196500 ;
    PORT
      LAYER met3 ;
        RECT 646.000 272.040 650.000 272.640 ;
    END
  END tag_in[39]
  PIN tag_in[3]
    DIRECTION INPUT ;
    USE SIGNAL ;
    ANTENNAGATEAREA 0.196500 ;
    PORT
      LAYER met3 ;
        RECT 646.000 173.440 650.000 174.040 ;
    END
  END tag_in[3]
  PIN tag_in[40]
    DIRECTION INPUT ;
    USE SIGNAL ;
    ANTENNAGATEAREA 0.196500 ;
    PORT
      LAYER met3 ;
        RECT 646.000 112.240 650.000 112.840 ;
    END
  END tag_in[40]
  PIN tag_in[41]
    DIRECTION INPUT ;
    USE SIGNAL ;
    ANTENNAGATEAREA 0.196500 ;
    PORT
      LAYER met2 ;
        RECT 454.110 0.000 454.390 4.000 ;
    END
  END tag_in[41]
  PIN tag_in[42]
    DIRECTION INPUT ;
    USE SIGNAL ;
    ANTENNAGATEAREA 0.196500 ;
    PORT
      LAYER met2 ;
        RECT 586.130 0.000 586.410 4.000 ;
    END
  END tag_in[42]
  PIN tag_in[43]
    DIRECTION INPUT ;
    USE SIGNAL ;
    ANTENNAGATEAREA 0.196500 ;
    PORT
      LAYER met3 ;
        RECT 646.000 23.840 650.000 24.440 ;
    END
  END tag_in[43]
  PIN tag_in[44]
    DIRECTION INPUT ;
    USE SIGNAL ;
    ANTENNAGATEAREA 0.196500 ;
    PORT
      LAYER met2 ;
        RECT 557.150 0.000 557.430 4.000 ;
    END
  END tag_in[44]
  PIN tag_in[45]
    DIRECTION INPUT ;
    USE SIGNAL ;
    ANTENNAGATEAREA 0.196500 ;
    PORT
      LAYER met2 ;
        RECT 479.870 0.000 480.150 4.000 ;
    END
  END tag_in[45]
  PIN tag_in[46]
    DIRECTION INPUT ;
    USE SIGNAL ;
    ANTENNAGATEAREA 0.196500 ;
    PORT
      LAYER met2 ;
        RECT 531.390 0.000 531.670 4.000 ;
    END
  END tag_in[46]
  PIN tag_in[47]
    DIRECTION INPUT ;
    USE SIGNAL ;
    ANTENNAGATEAREA 0.196500 ;
    PORT
      LAYER met3 ;
        RECT 646.000 156.440 650.000 157.040 ;
    END
  END tag_in[47]
  PIN tag_in[48]
    DIRECTION INPUT ;
    USE SIGNAL ;
    ANTENNAGATEAREA 0.196500 ;
    PORT
      LAYER met3 ;
        RECT 646.000 163.240 650.000 163.840 ;
    END
  END tag_in[48]
  PIN tag_in[49]
    DIRECTION INPUT ;
    USE SIGNAL ;
    ANTENNAGATEAREA 0.196500 ;
    PORT
      LAYER met3 ;
        RECT 646.000 159.840 650.000 160.440 ;
    END
  END tag_in[49]
  PIN tag_in[4]
    DIRECTION INPUT ;
    USE SIGNAL ;
    ANTENNAGATEAREA 0.196500 ;
    PORT
      LAYER met3 ;
        RECT 646.000 244.840 650.000 245.440 ;
    END
  END tag_in[4]
  PIN tag_in[50]
    DIRECTION INPUT ;
    USE SIGNAL ;
    ANTENNAGATEAREA 0.196500 ;
    PORT
      LAYER met2 ;
        RECT 573.250 0.000 573.530 4.000 ;
    END
  END tag_in[50]
  PIN tag_in[51]
    DIRECTION INPUT ;
    USE SIGNAL ;
    ANTENNAGATEAREA 0.196500 ;
    PORT
      LAYER met3 ;
        RECT 646.000 193.840 650.000 194.440 ;
    END
  END tag_in[51]
  PIN tag_in[52]
    DIRECTION INPUT ;
    USE SIGNAL ;
    ANTENNAGATEAREA 0.196500 ;
    PORT
      LAYER met3 ;
        RECT 646.000 241.440 650.000 242.040 ;
    END
  END tag_in[52]
  PIN tag_in[53]
    DIRECTION INPUT ;
    USE SIGNAL ;
    ANTENNAGATEAREA 0.196500 ;
    PORT
      LAYER met3 ;
        RECT 646.000 248.240 650.000 248.840 ;
    END
  END tag_in[53]
  PIN tag_in[54]
    DIRECTION INPUT ;
    USE SIGNAL ;
    ANTENNAGATEAREA 0.196500 ;
    PORT
      LAYER met3 ;
        RECT 646.000 255.040 650.000 255.640 ;
    END
  END tag_in[54]
  PIN tag_in[55]
    DIRECTION INPUT ;
    USE SIGNAL ;
    ANTENNAGATEAREA 0.196500 ;
    PORT
      LAYER met3 ;
        RECT 646.000 207.440 650.000 208.040 ;
    END
  END tag_in[55]
  PIN tag_in[56]
    DIRECTION INPUT ;
    USE SIGNAL ;
    ANTENNAGATEAREA 0.196500 ;
    PORT
      LAYER met3 ;
        RECT 646.000 74.840 650.000 75.440 ;
    END
  END tag_in[56]
  PIN tag_in[57]
    DIRECTION INPUT ;
    USE SIGNAL ;
    ANTENNAGATEAREA 0.196500 ;
    PORT
      LAYER met3 ;
        RECT 646.000 221.040 650.000 221.640 ;
    END
  END tag_in[57]
  PIN tag_in[58]
    DIRECTION INPUT ;
    USE SIGNAL ;
    ANTENNAGATEAREA 0.196500 ;
    PORT
      LAYER met3 ;
        RECT 646.000 119.040 650.000 119.640 ;
    END
  END tag_in[58]
  PIN tag_in[59]
    DIRECTION INPUT ;
    USE SIGNAL ;
    ANTENNAGATEAREA 0.196500 ;
    PORT
      LAYER met3 ;
        RECT 646.000 295.840 650.000 296.440 ;
    END
  END tag_in[59]
  PIN tag_in[5]
    DIRECTION INPUT ;
    USE SIGNAL ;
    ANTENNAGATEAREA 0.196500 ;
    PORT
      LAYER met3 ;
        RECT 646.000 132.640 650.000 133.240 ;
    END
  END tag_in[5]
  PIN tag_in[60]
    DIRECTION INPUT ;
    USE SIGNAL ;
    ANTENNAGATEAREA 0.196500 ;
    PORT
      LAYER met3 ;
        RECT 646.000 414.840 650.000 415.440 ;
    END
  END tag_in[60]
  PIN tag_in[61]
    DIRECTION INPUT ;
    USE SIGNAL ;
    ANTENNAGATEAREA 0.213000 ;
    PORT
      LAYER met3 ;
        RECT 646.000 646.040 650.000 646.640 ;
    END
  END tag_in[61]
  PIN tag_in[62]
    DIRECTION INPUT ;
    USE SIGNAL ;
    ANTENNAGATEAREA 0.196500 ;
    PORT
      LAYER met3 ;
        RECT 646.000 20.440 650.000 21.040 ;
    END
  END tag_in[62]
  PIN tag_in[63]
    DIRECTION INPUT ;
    USE SIGNAL ;
    ANTENNAGATEAREA 0.196500 ;
    PORT
      LAYER met3 ;
        RECT 646.000 105.440 650.000 106.040 ;
    END
  END tag_in[63]
  PIN tag_in[6]
    DIRECTION INPUT ;
    USE SIGNAL ;
    ANTENNAGATEAREA 0.213000 ;
    PORT
      LAYER met3 ;
        RECT 646.000 625.640 650.000 626.240 ;
    END
  END tag_in[6]
  PIN tag_in[7]
    DIRECTION INPUT ;
    USE SIGNAL ;
    ANTENNAGATEAREA 0.196500 ;
    PORT
      LAYER met3 ;
        RECT 646.000 108.840 650.000 109.440 ;
    END
  END tag_in[7]
  PIN tag_in[8]
    DIRECTION INPUT ;
    USE SIGNAL ;
    ANTENNAGATEAREA 0.196500 ;
    PORT
      LAYER met3 ;
        RECT 646.000 224.440 650.000 225.040 ;
    END
  END tag_in[8]
  PIN tag_in[9]
    DIRECTION INPUT ;
    USE SIGNAL ;
    ANTENNAGATEAREA 0.196500 ;
    PORT
      LAYER met2 ;
        RECT 486.310 0.000 486.590 4.000 ;
    END
  END tag_in[9]
  PIN valid
    DIRECTION OUTPUT ;
    USE SIGNAL ;
    ANTENNADIFFAREA 0.445500 ;
    PORT
      LAYER met3 ;
        RECT 646.000 350.240 650.000 350.840 ;
    END
  END valid
  OBS
      LAYER nwell ;
        RECT 5.330 10.795 644.650 636.565 ;
      LAYER li1 ;
        RECT 5.520 10.795 644.460 636.565 ;
      LAYER met1 ;
        RECT 0.070 0.380 647.610 640.860 ;
      LAYER met2 ;
        RECT 0.650 645.720 3.030 646.525 ;
        RECT 3.870 645.720 6.250 646.525 ;
        RECT 7.090 645.720 9.470 646.525 ;
        RECT 10.310 645.720 12.690 646.525 ;
        RECT 13.530 645.720 15.910 646.525 ;
        RECT 16.750 645.720 19.130 646.525 ;
        RECT 19.970 645.720 22.350 646.525 ;
        RECT 23.190 645.720 25.570 646.525 ;
        RECT 26.410 645.720 28.790 646.525 ;
        RECT 29.630 645.720 32.010 646.525 ;
        RECT 32.850 645.720 35.230 646.525 ;
        RECT 36.070 645.720 38.450 646.525 ;
        RECT 39.290 645.720 41.670 646.525 ;
        RECT 42.510 645.720 44.890 646.525 ;
        RECT 45.730 645.720 48.110 646.525 ;
        RECT 48.950 645.720 51.330 646.525 ;
        RECT 52.170 645.720 54.550 646.525 ;
        RECT 55.390 645.720 57.770 646.525 ;
        RECT 58.610 645.720 60.990 646.525 ;
        RECT 61.830 645.720 64.210 646.525 ;
        RECT 65.050 645.720 67.430 646.525 ;
        RECT 68.270 645.720 70.650 646.525 ;
        RECT 71.490 645.720 73.870 646.525 ;
        RECT 74.710 645.720 77.090 646.525 ;
        RECT 77.930 645.720 80.310 646.525 ;
        RECT 81.150 645.720 83.530 646.525 ;
        RECT 84.370 645.720 86.750 646.525 ;
        RECT 87.590 645.720 89.970 646.525 ;
        RECT 90.810 645.720 93.190 646.525 ;
        RECT 94.030 645.720 96.410 646.525 ;
        RECT 97.250 645.720 99.630 646.525 ;
        RECT 100.470 645.720 102.850 646.525 ;
        RECT 103.690 645.720 106.070 646.525 ;
        RECT 106.910 645.720 109.290 646.525 ;
        RECT 110.130 645.720 112.510 646.525 ;
        RECT 113.350 645.720 115.730 646.525 ;
        RECT 116.570 645.720 118.950 646.525 ;
        RECT 119.790 645.720 122.170 646.525 ;
        RECT 123.010 645.720 125.390 646.525 ;
        RECT 126.230 645.720 128.610 646.525 ;
        RECT 129.450 645.720 131.830 646.525 ;
        RECT 132.670 645.720 135.050 646.525 ;
        RECT 135.890 645.720 138.270 646.525 ;
        RECT 139.110 645.720 141.490 646.525 ;
        RECT 142.330 645.720 144.710 646.525 ;
        RECT 145.550 645.720 147.930 646.525 ;
        RECT 148.770 645.720 151.150 646.525 ;
        RECT 151.990 645.720 154.370 646.525 ;
        RECT 155.210 645.720 157.590 646.525 ;
        RECT 158.430 645.720 160.810 646.525 ;
        RECT 161.650 645.720 164.030 646.525 ;
        RECT 164.870 645.720 167.250 646.525 ;
        RECT 168.090 645.720 170.470 646.525 ;
        RECT 171.310 645.720 173.690 646.525 ;
        RECT 174.530 645.720 176.910 646.525 ;
        RECT 177.750 645.720 180.130 646.525 ;
        RECT 180.970 645.720 183.350 646.525 ;
        RECT 184.190 645.720 186.570 646.525 ;
        RECT 187.410 645.720 189.790 646.525 ;
        RECT 190.630 645.720 193.010 646.525 ;
        RECT 193.850 645.720 196.230 646.525 ;
        RECT 197.070 645.720 199.450 646.525 ;
        RECT 200.290 645.720 202.670 646.525 ;
        RECT 203.510 645.720 205.890 646.525 ;
        RECT 206.730 645.720 209.110 646.525 ;
        RECT 209.950 645.720 212.330 646.525 ;
        RECT 213.170 645.720 215.550 646.525 ;
        RECT 216.390 645.720 218.770 646.525 ;
        RECT 219.610 645.720 221.990 646.525 ;
        RECT 222.830 645.720 225.210 646.525 ;
        RECT 226.050 645.720 228.430 646.525 ;
        RECT 229.270 645.720 231.650 646.525 ;
        RECT 232.490 645.720 234.870 646.525 ;
        RECT 235.710 645.720 238.090 646.525 ;
        RECT 238.930 645.720 241.310 646.525 ;
        RECT 242.150 645.720 244.530 646.525 ;
        RECT 245.370 645.720 247.750 646.525 ;
        RECT 248.590 645.720 250.970 646.525 ;
        RECT 251.810 645.720 254.190 646.525 ;
        RECT 255.030 645.720 257.410 646.525 ;
        RECT 258.250 645.720 260.630 646.525 ;
        RECT 261.470 645.720 263.850 646.525 ;
        RECT 264.690 645.720 267.070 646.525 ;
        RECT 267.910 645.720 270.290 646.525 ;
        RECT 271.130 645.720 273.510 646.525 ;
        RECT 274.350 645.720 276.730 646.525 ;
        RECT 277.570 645.720 279.950 646.525 ;
        RECT 280.790 645.720 283.170 646.525 ;
        RECT 284.010 645.720 286.390 646.525 ;
        RECT 287.230 645.720 289.610 646.525 ;
        RECT 290.450 645.720 292.830 646.525 ;
        RECT 293.670 645.720 296.050 646.525 ;
        RECT 296.890 645.720 299.270 646.525 ;
        RECT 300.110 645.720 302.490 646.525 ;
        RECT 303.330 645.720 305.710 646.525 ;
        RECT 306.550 645.720 308.930 646.525 ;
        RECT 309.770 645.720 312.150 646.525 ;
        RECT 312.990 645.720 315.370 646.525 ;
        RECT 316.210 645.720 318.590 646.525 ;
        RECT 319.430 645.720 321.810 646.525 ;
        RECT 322.650 645.720 325.030 646.525 ;
        RECT 325.870 645.720 328.250 646.525 ;
        RECT 329.090 645.720 331.470 646.525 ;
        RECT 332.310 645.720 334.690 646.525 ;
        RECT 335.530 645.720 337.910 646.525 ;
        RECT 338.750 645.720 341.130 646.525 ;
        RECT 341.970 645.720 344.350 646.525 ;
        RECT 345.190 645.720 347.570 646.525 ;
        RECT 348.410 645.720 350.790 646.525 ;
        RECT 351.630 645.720 354.010 646.525 ;
        RECT 354.850 645.720 357.230 646.525 ;
        RECT 358.070 645.720 360.450 646.525 ;
        RECT 361.290 645.720 363.670 646.525 ;
        RECT 364.510 645.720 366.890 646.525 ;
        RECT 367.730 645.720 370.110 646.525 ;
        RECT 370.950 645.720 373.330 646.525 ;
        RECT 374.170 645.720 376.550 646.525 ;
        RECT 377.390 645.720 379.770 646.525 ;
        RECT 380.610 645.720 382.990 646.525 ;
        RECT 383.830 645.720 386.210 646.525 ;
        RECT 387.050 645.720 389.430 646.525 ;
        RECT 390.270 645.720 392.650 646.525 ;
        RECT 393.490 645.720 395.870 646.525 ;
        RECT 396.710 645.720 399.090 646.525 ;
        RECT 399.930 645.720 402.310 646.525 ;
        RECT 403.150 645.720 405.530 646.525 ;
        RECT 406.370 645.720 408.750 646.525 ;
        RECT 409.590 645.720 411.970 646.525 ;
        RECT 412.810 645.720 415.190 646.525 ;
        RECT 416.030 645.720 418.410 646.525 ;
        RECT 419.250 645.720 421.630 646.525 ;
        RECT 422.470 645.720 424.850 646.525 ;
        RECT 425.690 645.720 428.070 646.525 ;
        RECT 428.910 645.720 431.290 646.525 ;
        RECT 432.130 645.720 434.510 646.525 ;
        RECT 435.350 645.720 437.730 646.525 ;
        RECT 438.570 645.720 440.950 646.525 ;
        RECT 441.790 645.720 444.170 646.525 ;
        RECT 445.010 645.720 447.390 646.525 ;
        RECT 448.230 645.720 450.610 646.525 ;
        RECT 451.450 645.720 453.830 646.525 ;
        RECT 454.670 645.720 457.050 646.525 ;
        RECT 457.890 645.720 460.270 646.525 ;
        RECT 461.110 645.720 463.490 646.525 ;
        RECT 464.330 645.720 466.710 646.525 ;
        RECT 467.550 645.720 469.930 646.525 ;
        RECT 470.770 645.720 473.150 646.525 ;
        RECT 473.990 645.720 476.370 646.525 ;
        RECT 477.210 645.720 479.590 646.525 ;
        RECT 480.430 645.720 482.810 646.525 ;
        RECT 483.650 645.720 486.030 646.525 ;
        RECT 486.870 645.720 489.250 646.525 ;
        RECT 490.090 645.720 492.470 646.525 ;
        RECT 493.310 645.720 495.690 646.525 ;
        RECT 496.530 645.720 498.910 646.525 ;
        RECT 499.750 645.720 502.130 646.525 ;
        RECT 502.970 645.720 505.350 646.525 ;
        RECT 506.190 645.720 508.570 646.525 ;
        RECT 509.410 645.720 511.790 646.525 ;
        RECT 512.630 645.720 515.010 646.525 ;
        RECT 515.850 645.720 518.230 646.525 ;
        RECT 519.070 645.720 521.450 646.525 ;
        RECT 522.290 645.720 524.670 646.525 ;
        RECT 525.510 645.720 527.890 646.525 ;
        RECT 528.730 645.720 531.110 646.525 ;
        RECT 531.950 645.720 534.330 646.525 ;
        RECT 535.170 645.720 537.550 646.525 ;
        RECT 538.390 645.720 540.770 646.525 ;
        RECT 541.610 645.720 543.990 646.525 ;
        RECT 544.830 645.720 547.210 646.525 ;
        RECT 548.050 645.720 550.430 646.525 ;
        RECT 551.270 645.720 553.650 646.525 ;
        RECT 554.490 645.720 556.870 646.525 ;
        RECT 557.710 645.720 560.090 646.525 ;
        RECT 560.930 645.720 563.310 646.525 ;
        RECT 564.150 645.720 566.530 646.525 ;
        RECT 567.370 645.720 569.750 646.525 ;
        RECT 570.590 645.720 572.970 646.525 ;
        RECT 573.810 645.720 576.190 646.525 ;
        RECT 577.030 645.720 579.410 646.525 ;
        RECT 580.250 645.720 582.630 646.525 ;
        RECT 583.470 645.720 585.850 646.525 ;
        RECT 586.690 645.720 589.070 646.525 ;
        RECT 589.910 645.720 592.290 646.525 ;
        RECT 593.130 645.720 595.510 646.525 ;
        RECT 596.350 645.720 598.730 646.525 ;
        RECT 599.570 645.720 601.950 646.525 ;
        RECT 602.790 645.720 605.170 646.525 ;
        RECT 606.010 645.720 608.390 646.525 ;
        RECT 609.230 645.720 611.610 646.525 ;
        RECT 612.450 645.720 614.830 646.525 ;
        RECT 615.670 645.720 618.050 646.525 ;
        RECT 618.890 645.720 621.270 646.525 ;
        RECT 622.110 645.720 624.490 646.525 ;
        RECT 625.330 645.720 627.710 646.525 ;
        RECT 628.550 645.720 630.930 646.525 ;
        RECT 631.770 645.720 634.150 646.525 ;
        RECT 634.990 645.720 637.370 646.525 ;
        RECT 638.210 645.720 640.590 646.525 ;
        RECT 641.430 645.720 643.810 646.525 ;
        RECT 644.650 645.720 647.030 646.525 ;
        RECT 0.100 4.280 647.580 645.720 ;
        RECT 0.100 0.155 57.770 4.280 ;
        RECT 58.610 0.155 60.990 4.280 ;
        RECT 61.830 0.155 64.210 4.280 ;
        RECT 65.050 0.155 67.430 4.280 ;
        RECT 68.270 0.155 70.650 4.280 ;
        RECT 71.490 0.155 73.870 4.280 ;
        RECT 74.710 0.155 77.090 4.280 ;
        RECT 77.930 0.155 80.310 4.280 ;
        RECT 81.150 0.155 83.530 4.280 ;
        RECT 84.370 0.155 86.750 4.280 ;
        RECT 87.590 0.155 89.970 4.280 ;
        RECT 90.810 0.155 93.190 4.280 ;
        RECT 94.030 0.155 96.410 4.280 ;
        RECT 97.250 0.155 99.630 4.280 ;
        RECT 100.470 0.155 102.850 4.280 ;
        RECT 103.690 0.155 106.070 4.280 ;
        RECT 106.910 0.155 109.290 4.280 ;
        RECT 110.130 0.155 112.510 4.280 ;
        RECT 113.350 0.155 115.730 4.280 ;
        RECT 116.570 0.155 118.950 4.280 ;
        RECT 119.790 0.155 122.170 4.280 ;
        RECT 123.010 0.155 125.390 4.280 ;
        RECT 126.230 0.155 128.610 4.280 ;
        RECT 129.450 0.155 131.830 4.280 ;
        RECT 132.670 0.155 135.050 4.280 ;
        RECT 135.890 0.155 138.270 4.280 ;
        RECT 139.110 0.155 141.490 4.280 ;
        RECT 142.330 0.155 144.710 4.280 ;
        RECT 145.550 0.155 147.930 4.280 ;
        RECT 148.770 0.155 151.150 4.280 ;
        RECT 151.990 0.155 154.370 4.280 ;
        RECT 155.210 0.155 157.590 4.280 ;
        RECT 158.430 0.155 160.810 4.280 ;
        RECT 161.650 0.155 164.030 4.280 ;
        RECT 164.870 0.155 167.250 4.280 ;
        RECT 168.090 0.155 170.470 4.280 ;
        RECT 171.310 0.155 173.690 4.280 ;
        RECT 174.530 0.155 176.910 4.280 ;
        RECT 177.750 0.155 180.130 4.280 ;
        RECT 180.970 0.155 183.350 4.280 ;
        RECT 184.190 0.155 186.570 4.280 ;
        RECT 187.410 0.155 189.790 4.280 ;
        RECT 190.630 0.155 193.010 4.280 ;
        RECT 193.850 0.155 196.230 4.280 ;
        RECT 197.070 0.155 199.450 4.280 ;
        RECT 200.290 0.155 202.670 4.280 ;
        RECT 203.510 0.155 205.890 4.280 ;
        RECT 206.730 0.155 209.110 4.280 ;
        RECT 209.950 0.155 212.330 4.280 ;
        RECT 213.170 0.155 215.550 4.280 ;
        RECT 216.390 0.155 218.770 4.280 ;
        RECT 219.610 0.155 221.990 4.280 ;
        RECT 222.830 0.155 225.210 4.280 ;
        RECT 226.050 0.155 228.430 4.280 ;
        RECT 229.270 0.155 231.650 4.280 ;
        RECT 232.490 0.155 234.870 4.280 ;
        RECT 235.710 0.155 238.090 4.280 ;
        RECT 238.930 0.155 241.310 4.280 ;
        RECT 242.150 0.155 244.530 4.280 ;
        RECT 245.370 0.155 247.750 4.280 ;
        RECT 248.590 0.155 250.970 4.280 ;
        RECT 251.810 0.155 254.190 4.280 ;
        RECT 255.030 0.155 257.410 4.280 ;
        RECT 258.250 0.155 260.630 4.280 ;
        RECT 261.470 0.155 263.850 4.280 ;
        RECT 264.690 0.155 267.070 4.280 ;
        RECT 267.910 0.155 270.290 4.280 ;
        RECT 271.130 0.155 273.510 4.280 ;
        RECT 274.350 0.155 276.730 4.280 ;
        RECT 277.570 0.155 279.950 4.280 ;
        RECT 280.790 0.155 283.170 4.280 ;
        RECT 284.010 0.155 286.390 4.280 ;
        RECT 287.230 0.155 289.610 4.280 ;
        RECT 290.450 0.155 292.830 4.280 ;
        RECT 293.670 0.155 296.050 4.280 ;
        RECT 296.890 0.155 299.270 4.280 ;
        RECT 300.110 0.155 302.490 4.280 ;
        RECT 303.330 0.155 305.710 4.280 ;
        RECT 306.550 0.155 308.930 4.280 ;
        RECT 309.770 0.155 312.150 4.280 ;
        RECT 312.990 0.155 315.370 4.280 ;
        RECT 316.210 0.155 318.590 4.280 ;
        RECT 319.430 0.155 321.810 4.280 ;
        RECT 322.650 0.155 325.030 4.280 ;
        RECT 325.870 0.155 328.250 4.280 ;
        RECT 329.090 0.155 331.470 4.280 ;
        RECT 332.310 0.155 334.690 4.280 ;
        RECT 335.530 0.155 337.910 4.280 ;
        RECT 338.750 0.155 341.130 4.280 ;
        RECT 341.970 0.155 344.350 4.280 ;
        RECT 345.190 0.155 347.570 4.280 ;
        RECT 348.410 0.155 350.790 4.280 ;
        RECT 351.630 0.155 354.010 4.280 ;
        RECT 354.850 0.155 357.230 4.280 ;
        RECT 358.070 0.155 360.450 4.280 ;
        RECT 361.290 0.155 363.670 4.280 ;
        RECT 364.510 0.155 366.890 4.280 ;
        RECT 367.730 0.155 370.110 4.280 ;
        RECT 370.950 0.155 373.330 4.280 ;
        RECT 374.170 0.155 376.550 4.280 ;
        RECT 377.390 0.155 379.770 4.280 ;
        RECT 380.610 0.155 382.990 4.280 ;
        RECT 383.830 0.155 386.210 4.280 ;
        RECT 387.050 0.155 389.430 4.280 ;
        RECT 390.270 0.155 392.650 4.280 ;
        RECT 393.490 0.155 395.870 4.280 ;
        RECT 396.710 0.155 399.090 4.280 ;
        RECT 399.930 0.155 402.310 4.280 ;
        RECT 403.150 0.155 405.530 4.280 ;
        RECT 406.370 0.155 408.750 4.280 ;
        RECT 409.590 0.155 411.970 4.280 ;
        RECT 412.810 0.155 415.190 4.280 ;
        RECT 416.030 0.155 418.410 4.280 ;
        RECT 419.250 0.155 421.630 4.280 ;
        RECT 422.470 0.155 424.850 4.280 ;
        RECT 425.690 0.155 428.070 4.280 ;
        RECT 428.910 0.155 431.290 4.280 ;
        RECT 432.130 0.155 434.510 4.280 ;
        RECT 435.350 0.155 437.730 4.280 ;
        RECT 438.570 0.155 440.950 4.280 ;
        RECT 441.790 0.155 444.170 4.280 ;
        RECT 445.010 0.155 447.390 4.280 ;
        RECT 448.230 0.155 450.610 4.280 ;
        RECT 451.450 0.155 453.830 4.280 ;
        RECT 454.670 0.155 457.050 4.280 ;
        RECT 457.890 0.155 460.270 4.280 ;
        RECT 461.110 0.155 463.490 4.280 ;
        RECT 464.330 0.155 466.710 4.280 ;
        RECT 467.550 0.155 469.930 4.280 ;
        RECT 470.770 0.155 473.150 4.280 ;
        RECT 473.990 0.155 476.370 4.280 ;
        RECT 477.210 0.155 479.590 4.280 ;
        RECT 480.430 0.155 482.810 4.280 ;
        RECT 483.650 0.155 486.030 4.280 ;
        RECT 486.870 0.155 489.250 4.280 ;
        RECT 490.090 0.155 492.470 4.280 ;
        RECT 493.310 0.155 495.690 4.280 ;
        RECT 496.530 0.155 498.910 4.280 ;
        RECT 499.750 0.155 502.130 4.280 ;
        RECT 502.970 0.155 505.350 4.280 ;
        RECT 506.190 0.155 508.570 4.280 ;
        RECT 509.410 0.155 511.790 4.280 ;
        RECT 512.630 0.155 515.010 4.280 ;
        RECT 515.850 0.155 518.230 4.280 ;
        RECT 519.070 0.155 521.450 4.280 ;
        RECT 522.290 0.155 524.670 4.280 ;
        RECT 525.510 0.155 527.890 4.280 ;
        RECT 528.730 0.155 531.110 4.280 ;
        RECT 531.950 0.155 534.330 4.280 ;
        RECT 535.170 0.155 537.550 4.280 ;
        RECT 538.390 0.155 540.770 4.280 ;
        RECT 541.610 0.155 543.990 4.280 ;
        RECT 544.830 0.155 547.210 4.280 ;
        RECT 548.050 0.155 550.430 4.280 ;
        RECT 551.270 0.155 553.650 4.280 ;
        RECT 554.490 0.155 556.870 4.280 ;
        RECT 557.710 0.155 560.090 4.280 ;
        RECT 560.930 0.155 563.310 4.280 ;
        RECT 564.150 0.155 566.530 4.280 ;
        RECT 567.370 0.155 569.750 4.280 ;
        RECT 570.590 0.155 572.970 4.280 ;
        RECT 573.810 0.155 576.190 4.280 ;
        RECT 577.030 0.155 579.410 4.280 ;
        RECT 580.250 0.155 582.630 4.280 ;
        RECT 583.470 0.155 585.850 4.280 ;
        RECT 586.690 0.155 589.070 4.280 ;
        RECT 589.910 0.155 592.290 4.280 ;
        RECT 593.130 0.155 595.510 4.280 ;
        RECT 596.350 0.155 643.810 4.280 ;
        RECT 644.650 0.155 647.030 4.280 ;
      LAYER met3 ;
        RECT 4.400 645.640 645.600 646.505 ;
        RECT 3.990 643.640 646.000 645.640 ;
        RECT 4.400 642.240 645.600 643.640 ;
        RECT 3.990 640.240 646.000 642.240 ;
        RECT 4.400 638.840 645.600 640.240 ;
        RECT 3.990 636.840 646.000 638.840 ;
        RECT 4.400 635.440 645.600 636.840 ;
        RECT 3.990 633.440 646.000 635.440 ;
        RECT 4.400 632.040 645.600 633.440 ;
        RECT 3.990 630.040 646.000 632.040 ;
        RECT 4.400 628.640 645.600 630.040 ;
        RECT 3.990 626.640 646.000 628.640 ;
        RECT 4.400 625.240 645.600 626.640 ;
        RECT 3.990 623.240 646.000 625.240 ;
        RECT 4.400 621.840 645.600 623.240 ;
        RECT 3.990 619.840 646.000 621.840 ;
        RECT 4.400 618.440 645.600 619.840 ;
        RECT 3.990 616.440 646.000 618.440 ;
        RECT 4.400 615.040 645.600 616.440 ;
        RECT 3.990 613.040 646.000 615.040 ;
        RECT 4.400 611.640 645.600 613.040 ;
        RECT 3.990 609.640 646.000 611.640 ;
        RECT 4.400 608.240 645.600 609.640 ;
        RECT 3.990 606.240 646.000 608.240 ;
        RECT 4.400 604.840 645.600 606.240 ;
        RECT 3.990 602.840 646.000 604.840 ;
        RECT 4.400 601.440 645.600 602.840 ;
        RECT 3.990 599.440 646.000 601.440 ;
        RECT 4.400 598.040 645.600 599.440 ;
        RECT 3.990 596.040 646.000 598.040 ;
        RECT 4.400 594.640 645.600 596.040 ;
        RECT 3.990 592.640 646.000 594.640 ;
        RECT 4.400 591.240 645.600 592.640 ;
        RECT 3.990 589.240 646.000 591.240 ;
        RECT 4.400 587.840 645.600 589.240 ;
        RECT 3.990 585.840 646.000 587.840 ;
        RECT 4.400 584.440 645.600 585.840 ;
        RECT 3.990 582.440 646.000 584.440 ;
        RECT 4.400 581.040 645.600 582.440 ;
        RECT 3.990 579.040 646.000 581.040 ;
        RECT 4.400 577.640 645.600 579.040 ;
        RECT 3.990 575.640 646.000 577.640 ;
        RECT 4.400 574.240 645.600 575.640 ;
        RECT 3.990 572.240 646.000 574.240 ;
        RECT 4.400 570.840 645.600 572.240 ;
        RECT 3.990 568.840 646.000 570.840 ;
        RECT 4.400 567.440 645.600 568.840 ;
        RECT 3.990 565.440 646.000 567.440 ;
        RECT 4.400 564.040 645.600 565.440 ;
        RECT 3.990 562.040 646.000 564.040 ;
        RECT 4.400 560.640 645.600 562.040 ;
        RECT 3.990 558.640 646.000 560.640 ;
        RECT 4.400 557.240 645.600 558.640 ;
        RECT 3.990 555.240 646.000 557.240 ;
        RECT 4.400 553.840 645.600 555.240 ;
        RECT 3.990 551.840 646.000 553.840 ;
        RECT 4.400 550.440 645.600 551.840 ;
        RECT 3.990 548.440 646.000 550.440 ;
        RECT 4.400 547.040 645.600 548.440 ;
        RECT 3.990 545.040 646.000 547.040 ;
        RECT 4.400 543.640 645.600 545.040 ;
        RECT 3.990 541.640 646.000 543.640 ;
        RECT 4.400 540.240 645.600 541.640 ;
        RECT 3.990 538.240 646.000 540.240 ;
        RECT 4.400 536.840 645.600 538.240 ;
        RECT 3.990 534.840 646.000 536.840 ;
        RECT 4.400 533.440 645.600 534.840 ;
        RECT 3.990 531.440 646.000 533.440 ;
        RECT 4.400 530.040 645.600 531.440 ;
        RECT 3.990 528.040 646.000 530.040 ;
        RECT 4.400 526.640 645.600 528.040 ;
        RECT 3.990 524.640 646.000 526.640 ;
        RECT 4.400 523.240 645.600 524.640 ;
        RECT 3.990 521.240 646.000 523.240 ;
        RECT 4.400 519.840 645.600 521.240 ;
        RECT 3.990 517.840 646.000 519.840 ;
        RECT 4.400 516.440 645.600 517.840 ;
        RECT 3.990 514.440 646.000 516.440 ;
        RECT 4.400 513.040 645.600 514.440 ;
        RECT 3.990 511.040 646.000 513.040 ;
        RECT 4.400 509.640 645.600 511.040 ;
        RECT 3.990 507.640 646.000 509.640 ;
        RECT 4.400 506.240 645.600 507.640 ;
        RECT 3.990 504.240 646.000 506.240 ;
        RECT 4.400 502.840 645.600 504.240 ;
        RECT 3.990 500.840 646.000 502.840 ;
        RECT 4.400 499.440 645.600 500.840 ;
        RECT 3.990 497.440 646.000 499.440 ;
        RECT 4.400 496.040 645.600 497.440 ;
        RECT 3.990 494.040 646.000 496.040 ;
        RECT 4.400 492.640 645.600 494.040 ;
        RECT 3.990 490.640 646.000 492.640 ;
        RECT 4.400 489.240 645.600 490.640 ;
        RECT 3.990 487.240 646.000 489.240 ;
        RECT 4.400 485.840 645.600 487.240 ;
        RECT 3.990 483.840 646.000 485.840 ;
        RECT 4.400 482.440 645.600 483.840 ;
        RECT 3.990 480.440 646.000 482.440 ;
        RECT 4.400 479.040 645.600 480.440 ;
        RECT 3.990 477.040 646.000 479.040 ;
        RECT 4.400 475.640 645.600 477.040 ;
        RECT 3.990 473.640 646.000 475.640 ;
        RECT 4.400 472.240 645.600 473.640 ;
        RECT 3.990 470.240 646.000 472.240 ;
        RECT 4.400 468.840 645.600 470.240 ;
        RECT 3.990 466.840 646.000 468.840 ;
        RECT 4.400 465.440 645.600 466.840 ;
        RECT 3.990 463.440 646.000 465.440 ;
        RECT 4.400 462.040 645.600 463.440 ;
        RECT 3.990 460.040 646.000 462.040 ;
        RECT 4.400 458.640 645.600 460.040 ;
        RECT 3.990 456.640 646.000 458.640 ;
        RECT 4.400 455.240 645.600 456.640 ;
        RECT 3.990 453.240 646.000 455.240 ;
        RECT 4.400 451.840 645.600 453.240 ;
        RECT 3.990 449.840 646.000 451.840 ;
        RECT 4.400 448.440 645.600 449.840 ;
        RECT 3.990 446.440 646.000 448.440 ;
        RECT 4.400 445.040 645.600 446.440 ;
        RECT 3.990 443.040 646.000 445.040 ;
        RECT 4.400 441.640 645.600 443.040 ;
        RECT 3.990 439.640 646.000 441.640 ;
        RECT 4.400 438.240 645.600 439.640 ;
        RECT 3.990 436.240 646.000 438.240 ;
        RECT 4.400 434.840 645.600 436.240 ;
        RECT 3.990 432.840 646.000 434.840 ;
        RECT 4.400 431.440 645.600 432.840 ;
        RECT 3.990 429.440 646.000 431.440 ;
        RECT 4.400 428.040 645.600 429.440 ;
        RECT 3.990 426.040 646.000 428.040 ;
        RECT 4.400 424.640 645.600 426.040 ;
        RECT 3.990 422.640 646.000 424.640 ;
        RECT 4.400 421.240 645.600 422.640 ;
        RECT 3.990 419.240 646.000 421.240 ;
        RECT 4.400 417.840 645.600 419.240 ;
        RECT 3.990 415.840 646.000 417.840 ;
        RECT 4.400 414.440 645.600 415.840 ;
        RECT 3.990 412.440 646.000 414.440 ;
        RECT 4.400 411.040 645.600 412.440 ;
        RECT 3.990 409.040 646.000 411.040 ;
        RECT 4.400 407.640 645.600 409.040 ;
        RECT 3.990 405.640 646.000 407.640 ;
        RECT 4.400 404.240 645.600 405.640 ;
        RECT 3.990 402.240 646.000 404.240 ;
        RECT 4.400 400.840 645.600 402.240 ;
        RECT 3.990 398.840 646.000 400.840 ;
        RECT 4.400 397.440 645.600 398.840 ;
        RECT 3.990 395.440 646.000 397.440 ;
        RECT 4.400 394.040 645.600 395.440 ;
        RECT 3.990 392.040 646.000 394.040 ;
        RECT 4.400 390.640 645.600 392.040 ;
        RECT 3.990 388.640 646.000 390.640 ;
        RECT 4.400 387.240 645.600 388.640 ;
        RECT 3.990 385.240 646.000 387.240 ;
        RECT 4.400 383.840 645.600 385.240 ;
        RECT 3.990 381.840 646.000 383.840 ;
        RECT 4.400 380.440 645.600 381.840 ;
        RECT 3.990 378.440 646.000 380.440 ;
        RECT 4.400 377.040 645.600 378.440 ;
        RECT 3.990 375.040 646.000 377.040 ;
        RECT 4.400 373.640 645.600 375.040 ;
        RECT 3.990 371.640 646.000 373.640 ;
        RECT 4.400 370.240 645.600 371.640 ;
        RECT 3.990 368.240 646.000 370.240 ;
        RECT 4.400 366.840 645.600 368.240 ;
        RECT 3.990 364.840 646.000 366.840 ;
        RECT 4.400 363.440 645.600 364.840 ;
        RECT 3.990 361.440 646.000 363.440 ;
        RECT 4.400 360.040 645.600 361.440 ;
        RECT 3.990 358.040 646.000 360.040 ;
        RECT 4.400 356.640 645.600 358.040 ;
        RECT 3.990 354.640 646.000 356.640 ;
        RECT 4.400 353.240 645.600 354.640 ;
        RECT 3.990 351.240 646.000 353.240 ;
        RECT 4.400 349.840 645.600 351.240 ;
        RECT 3.990 347.840 646.000 349.840 ;
        RECT 4.400 346.440 645.600 347.840 ;
        RECT 3.990 344.440 646.000 346.440 ;
        RECT 4.400 343.040 645.600 344.440 ;
        RECT 3.990 341.040 646.000 343.040 ;
        RECT 4.400 339.640 645.600 341.040 ;
        RECT 3.990 337.640 646.000 339.640 ;
        RECT 4.400 336.240 645.600 337.640 ;
        RECT 3.990 334.240 646.000 336.240 ;
        RECT 4.400 332.840 645.600 334.240 ;
        RECT 3.990 330.840 646.000 332.840 ;
        RECT 4.400 329.440 645.600 330.840 ;
        RECT 3.990 327.440 646.000 329.440 ;
        RECT 4.400 326.040 645.600 327.440 ;
        RECT 3.990 324.040 646.000 326.040 ;
        RECT 4.400 322.640 645.600 324.040 ;
        RECT 3.990 320.640 646.000 322.640 ;
        RECT 4.400 319.240 645.600 320.640 ;
        RECT 3.990 317.240 646.000 319.240 ;
        RECT 4.400 315.840 645.600 317.240 ;
        RECT 3.990 313.840 646.000 315.840 ;
        RECT 4.400 312.440 645.600 313.840 ;
        RECT 3.990 310.440 646.000 312.440 ;
        RECT 4.400 309.040 645.600 310.440 ;
        RECT 3.990 307.040 646.000 309.040 ;
        RECT 4.400 305.640 645.600 307.040 ;
        RECT 3.990 303.640 646.000 305.640 ;
        RECT 4.400 302.240 645.600 303.640 ;
        RECT 3.990 300.240 646.000 302.240 ;
        RECT 4.400 298.840 645.600 300.240 ;
        RECT 3.990 296.840 646.000 298.840 ;
        RECT 4.400 295.440 645.600 296.840 ;
        RECT 3.990 293.440 646.000 295.440 ;
        RECT 4.400 292.040 645.600 293.440 ;
        RECT 3.990 290.040 646.000 292.040 ;
        RECT 4.400 288.640 645.600 290.040 ;
        RECT 3.990 286.640 646.000 288.640 ;
        RECT 4.400 285.240 645.600 286.640 ;
        RECT 3.990 283.240 646.000 285.240 ;
        RECT 4.400 281.840 645.600 283.240 ;
        RECT 3.990 279.840 646.000 281.840 ;
        RECT 4.400 278.440 645.600 279.840 ;
        RECT 3.990 276.440 646.000 278.440 ;
        RECT 4.400 275.040 645.600 276.440 ;
        RECT 3.990 273.040 646.000 275.040 ;
        RECT 4.400 271.640 645.600 273.040 ;
        RECT 3.990 269.640 646.000 271.640 ;
        RECT 4.400 268.240 645.600 269.640 ;
        RECT 3.990 266.240 646.000 268.240 ;
        RECT 4.400 264.840 645.600 266.240 ;
        RECT 3.990 262.840 646.000 264.840 ;
        RECT 4.400 261.440 645.600 262.840 ;
        RECT 3.990 259.440 646.000 261.440 ;
        RECT 4.400 258.040 645.600 259.440 ;
        RECT 3.990 256.040 646.000 258.040 ;
        RECT 4.400 254.640 645.600 256.040 ;
        RECT 3.990 252.640 646.000 254.640 ;
        RECT 4.400 251.240 645.600 252.640 ;
        RECT 3.990 249.240 646.000 251.240 ;
        RECT 4.400 247.840 645.600 249.240 ;
        RECT 3.990 245.840 646.000 247.840 ;
        RECT 4.400 244.440 645.600 245.840 ;
        RECT 3.990 242.440 646.000 244.440 ;
        RECT 4.400 241.040 645.600 242.440 ;
        RECT 3.990 239.040 646.000 241.040 ;
        RECT 4.400 237.640 645.600 239.040 ;
        RECT 3.990 235.640 646.000 237.640 ;
        RECT 4.400 234.240 645.600 235.640 ;
        RECT 3.990 232.240 646.000 234.240 ;
        RECT 4.400 230.840 645.600 232.240 ;
        RECT 3.990 228.840 646.000 230.840 ;
        RECT 4.400 227.440 645.600 228.840 ;
        RECT 3.990 225.440 646.000 227.440 ;
        RECT 4.400 224.040 645.600 225.440 ;
        RECT 3.990 222.040 646.000 224.040 ;
        RECT 4.400 220.640 645.600 222.040 ;
        RECT 3.990 218.640 646.000 220.640 ;
        RECT 4.400 217.240 645.600 218.640 ;
        RECT 3.990 215.240 646.000 217.240 ;
        RECT 4.400 213.840 645.600 215.240 ;
        RECT 3.990 211.840 646.000 213.840 ;
        RECT 4.400 210.440 645.600 211.840 ;
        RECT 3.990 208.440 646.000 210.440 ;
        RECT 4.400 207.040 645.600 208.440 ;
        RECT 3.990 205.040 646.000 207.040 ;
        RECT 4.400 203.640 645.600 205.040 ;
        RECT 3.990 201.640 646.000 203.640 ;
        RECT 4.400 200.240 645.600 201.640 ;
        RECT 3.990 198.240 646.000 200.240 ;
        RECT 4.400 196.840 645.600 198.240 ;
        RECT 3.990 194.840 646.000 196.840 ;
        RECT 4.400 193.440 645.600 194.840 ;
        RECT 3.990 191.440 646.000 193.440 ;
        RECT 4.400 190.040 645.600 191.440 ;
        RECT 3.990 188.040 646.000 190.040 ;
        RECT 4.400 186.640 645.600 188.040 ;
        RECT 3.990 184.640 646.000 186.640 ;
        RECT 4.400 183.240 645.600 184.640 ;
        RECT 3.990 181.240 646.000 183.240 ;
        RECT 4.400 179.840 645.600 181.240 ;
        RECT 3.990 177.840 646.000 179.840 ;
        RECT 4.400 176.440 645.600 177.840 ;
        RECT 3.990 174.440 646.000 176.440 ;
        RECT 4.400 173.040 645.600 174.440 ;
        RECT 3.990 171.040 646.000 173.040 ;
        RECT 4.400 169.640 645.600 171.040 ;
        RECT 3.990 167.640 646.000 169.640 ;
        RECT 4.400 166.240 645.600 167.640 ;
        RECT 3.990 164.240 646.000 166.240 ;
        RECT 4.400 162.840 645.600 164.240 ;
        RECT 3.990 160.840 646.000 162.840 ;
        RECT 4.400 159.440 645.600 160.840 ;
        RECT 3.990 157.440 646.000 159.440 ;
        RECT 4.400 156.040 645.600 157.440 ;
        RECT 3.990 154.040 646.000 156.040 ;
        RECT 4.400 152.640 645.600 154.040 ;
        RECT 3.990 150.640 646.000 152.640 ;
        RECT 4.400 149.240 645.600 150.640 ;
        RECT 3.990 147.240 646.000 149.240 ;
        RECT 4.400 145.840 645.600 147.240 ;
        RECT 3.990 143.840 646.000 145.840 ;
        RECT 4.400 142.440 645.600 143.840 ;
        RECT 3.990 140.440 646.000 142.440 ;
        RECT 4.400 139.040 645.600 140.440 ;
        RECT 3.990 137.040 646.000 139.040 ;
        RECT 4.400 135.640 645.600 137.040 ;
        RECT 3.990 133.640 646.000 135.640 ;
        RECT 4.400 132.240 645.600 133.640 ;
        RECT 3.990 130.240 646.000 132.240 ;
        RECT 4.400 128.840 645.600 130.240 ;
        RECT 3.990 126.840 646.000 128.840 ;
        RECT 4.400 125.440 645.600 126.840 ;
        RECT 3.990 123.440 646.000 125.440 ;
        RECT 4.400 122.040 645.600 123.440 ;
        RECT 3.990 120.040 646.000 122.040 ;
        RECT 4.400 118.640 645.600 120.040 ;
        RECT 3.990 116.640 646.000 118.640 ;
        RECT 4.400 115.240 645.600 116.640 ;
        RECT 3.990 113.240 646.000 115.240 ;
        RECT 4.400 111.840 645.600 113.240 ;
        RECT 3.990 109.840 646.000 111.840 ;
        RECT 4.400 108.440 645.600 109.840 ;
        RECT 3.990 106.440 646.000 108.440 ;
        RECT 4.400 105.040 645.600 106.440 ;
        RECT 3.990 103.040 646.000 105.040 ;
        RECT 4.400 101.640 645.600 103.040 ;
        RECT 3.990 99.640 646.000 101.640 ;
        RECT 4.400 98.240 645.600 99.640 ;
        RECT 3.990 96.240 646.000 98.240 ;
        RECT 4.400 94.840 645.600 96.240 ;
        RECT 3.990 92.840 646.000 94.840 ;
        RECT 4.400 91.440 645.600 92.840 ;
        RECT 3.990 89.440 646.000 91.440 ;
        RECT 4.400 88.040 645.600 89.440 ;
        RECT 3.990 86.040 646.000 88.040 ;
        RECT 4.400 84.640 645.600 86.040 ;
        RECT 3.990 82.640 646.000 84.640 ;
        RECT 4.400 81.240 645.600 82.640 ;
        RECT 3.990 79.240 646.000 81.240 ;
        RECT 4.400 77.840 645.600 79.240 ;
        RECT 3.990 75.840 646.000 77.840 ;
        RECT 4.400 74.440 645.600 75.840 ;
        RECT 3.990 72.440 646.000 74.440 ;
        RECT 4.400 71.040 645.600 72.440 ;
        RECT 3.990 69.040 646.000 71.040 ;
        RECT 4.400 67.640 645.600 69.040 ;
        RECT 3.990 65.640 646.000 67.640 ;
        RECT 4.400 64.240 645.600 65.640 ;
        RECT 3.990 62.240 646.000 64.240 ;
        RECT 4.400 60.840 645.600 62.240 ;
        RECT 3.990 58.840 646.000 60.840 ;
        RECT 4.400 57.440 645.600 58.840 ;
        RECT 3.990 55.440 646.000 57.440 ;
        RECT 4.400 54.040 645.600 55.440 ;
        RECT 3.990 52.040 646.000 54.040 ;
        RECT 4.400 50.640 645.600 52.040 ;
        RECT 3.990 48.640 646.000 50.640 ;
        RECT 4.400 47.240 645.600 48.640 ;
        RECT 3.990 45.240 646.000 47.240 ;
        RECT 4.400 43.840 645.600 45.240 ;
        RECT 3.990 41.840 646.000 43.840 ;
        RECT 4.400 40.440 645.600 41.840 ;
        RECT 3.990 38.440 646.000 40.440 ;
        RECT 4.400 37.040 645.600 38.440 ;
        RECT 3.990 35.040 646.000 37.040 ;
        RECT 4.400 33.640 645.600 35.040 ;
        RECT 3.990 31.640 646.000 33.640 ;
        RECT 4.400 30.240 645.600 31.640 ;
        RECT 3.990 28.240 646.000 30.240 ;
        RECT 4.400 26.840 645.600 28.240 ;
        RECT 3.990 24.840 646.000 26.840 ;
        RECT 4.400 23.440 645.600 24.840 ;
        RECT 3.990 21.440 646.000 23.440 ;
        RECT 4.400 20.040 645.600 21.440 ;
        RECT 3.990 18.040 646.000 20.040 ;
        RECT 4.400 16.640 645.600 18.040 ;
        RECT 3.990 14.640 646.000 16.640 ;
        RECT 4.400 13.240 645.600 14.640 ;
        RECT 3.990 11.240 646.000 13.240 ;
        RECT 4.400 9.840 645.600 11.240 ;
        RECT 3.990 7.840 646.000 9.840 ;
        RECT 4.400 6.440 645.600 7.840 ;
        RECT 3.990 4.440 646.000 6.440 ;
        RECT 4.400 3.040 645.600 4.440 ;
        RECT 3.990 1.040 646.000 3.040 ;
        RECT 4.400 0.175 645.600 1.040 ;
      LAYER met4 ;
        RECT 7.655 13.095 20.640 635.625 ;
        RECT 23.040 13.095 23.940 635.625 ;
        RECT 26.340 13.095 174.240 635.625 ;
        RECT 176.640 13.095 177.540 635.625 ;
        RECT 179.940 13.095 327.840 635.625 ;
        RECT 330.240 13.095 331.140 635.625 ;
        RECT 333.540 13.095 481.440 635.625 ;
        RECT 483.840 13.095 484.740 635.625 ;
        RECT 487.140 13.095 635.040 635.625 ;
        RECT 637.440 13.095 638.185 635.625 ;
  END
END tinyjambu_core
END LIBRARY

